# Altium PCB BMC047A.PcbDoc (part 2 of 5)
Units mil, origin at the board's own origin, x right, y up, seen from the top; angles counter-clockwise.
Board outline 4950 x 3450 mil, 6 copper layers (Top Layer, GND Layer 1, Signal Layer 1, Signal Layer 2, GND Layer 2, Bottom Layer), stack 60.7 mil thick; 322 components, 160 nets, 1128 pads, 816 vias.

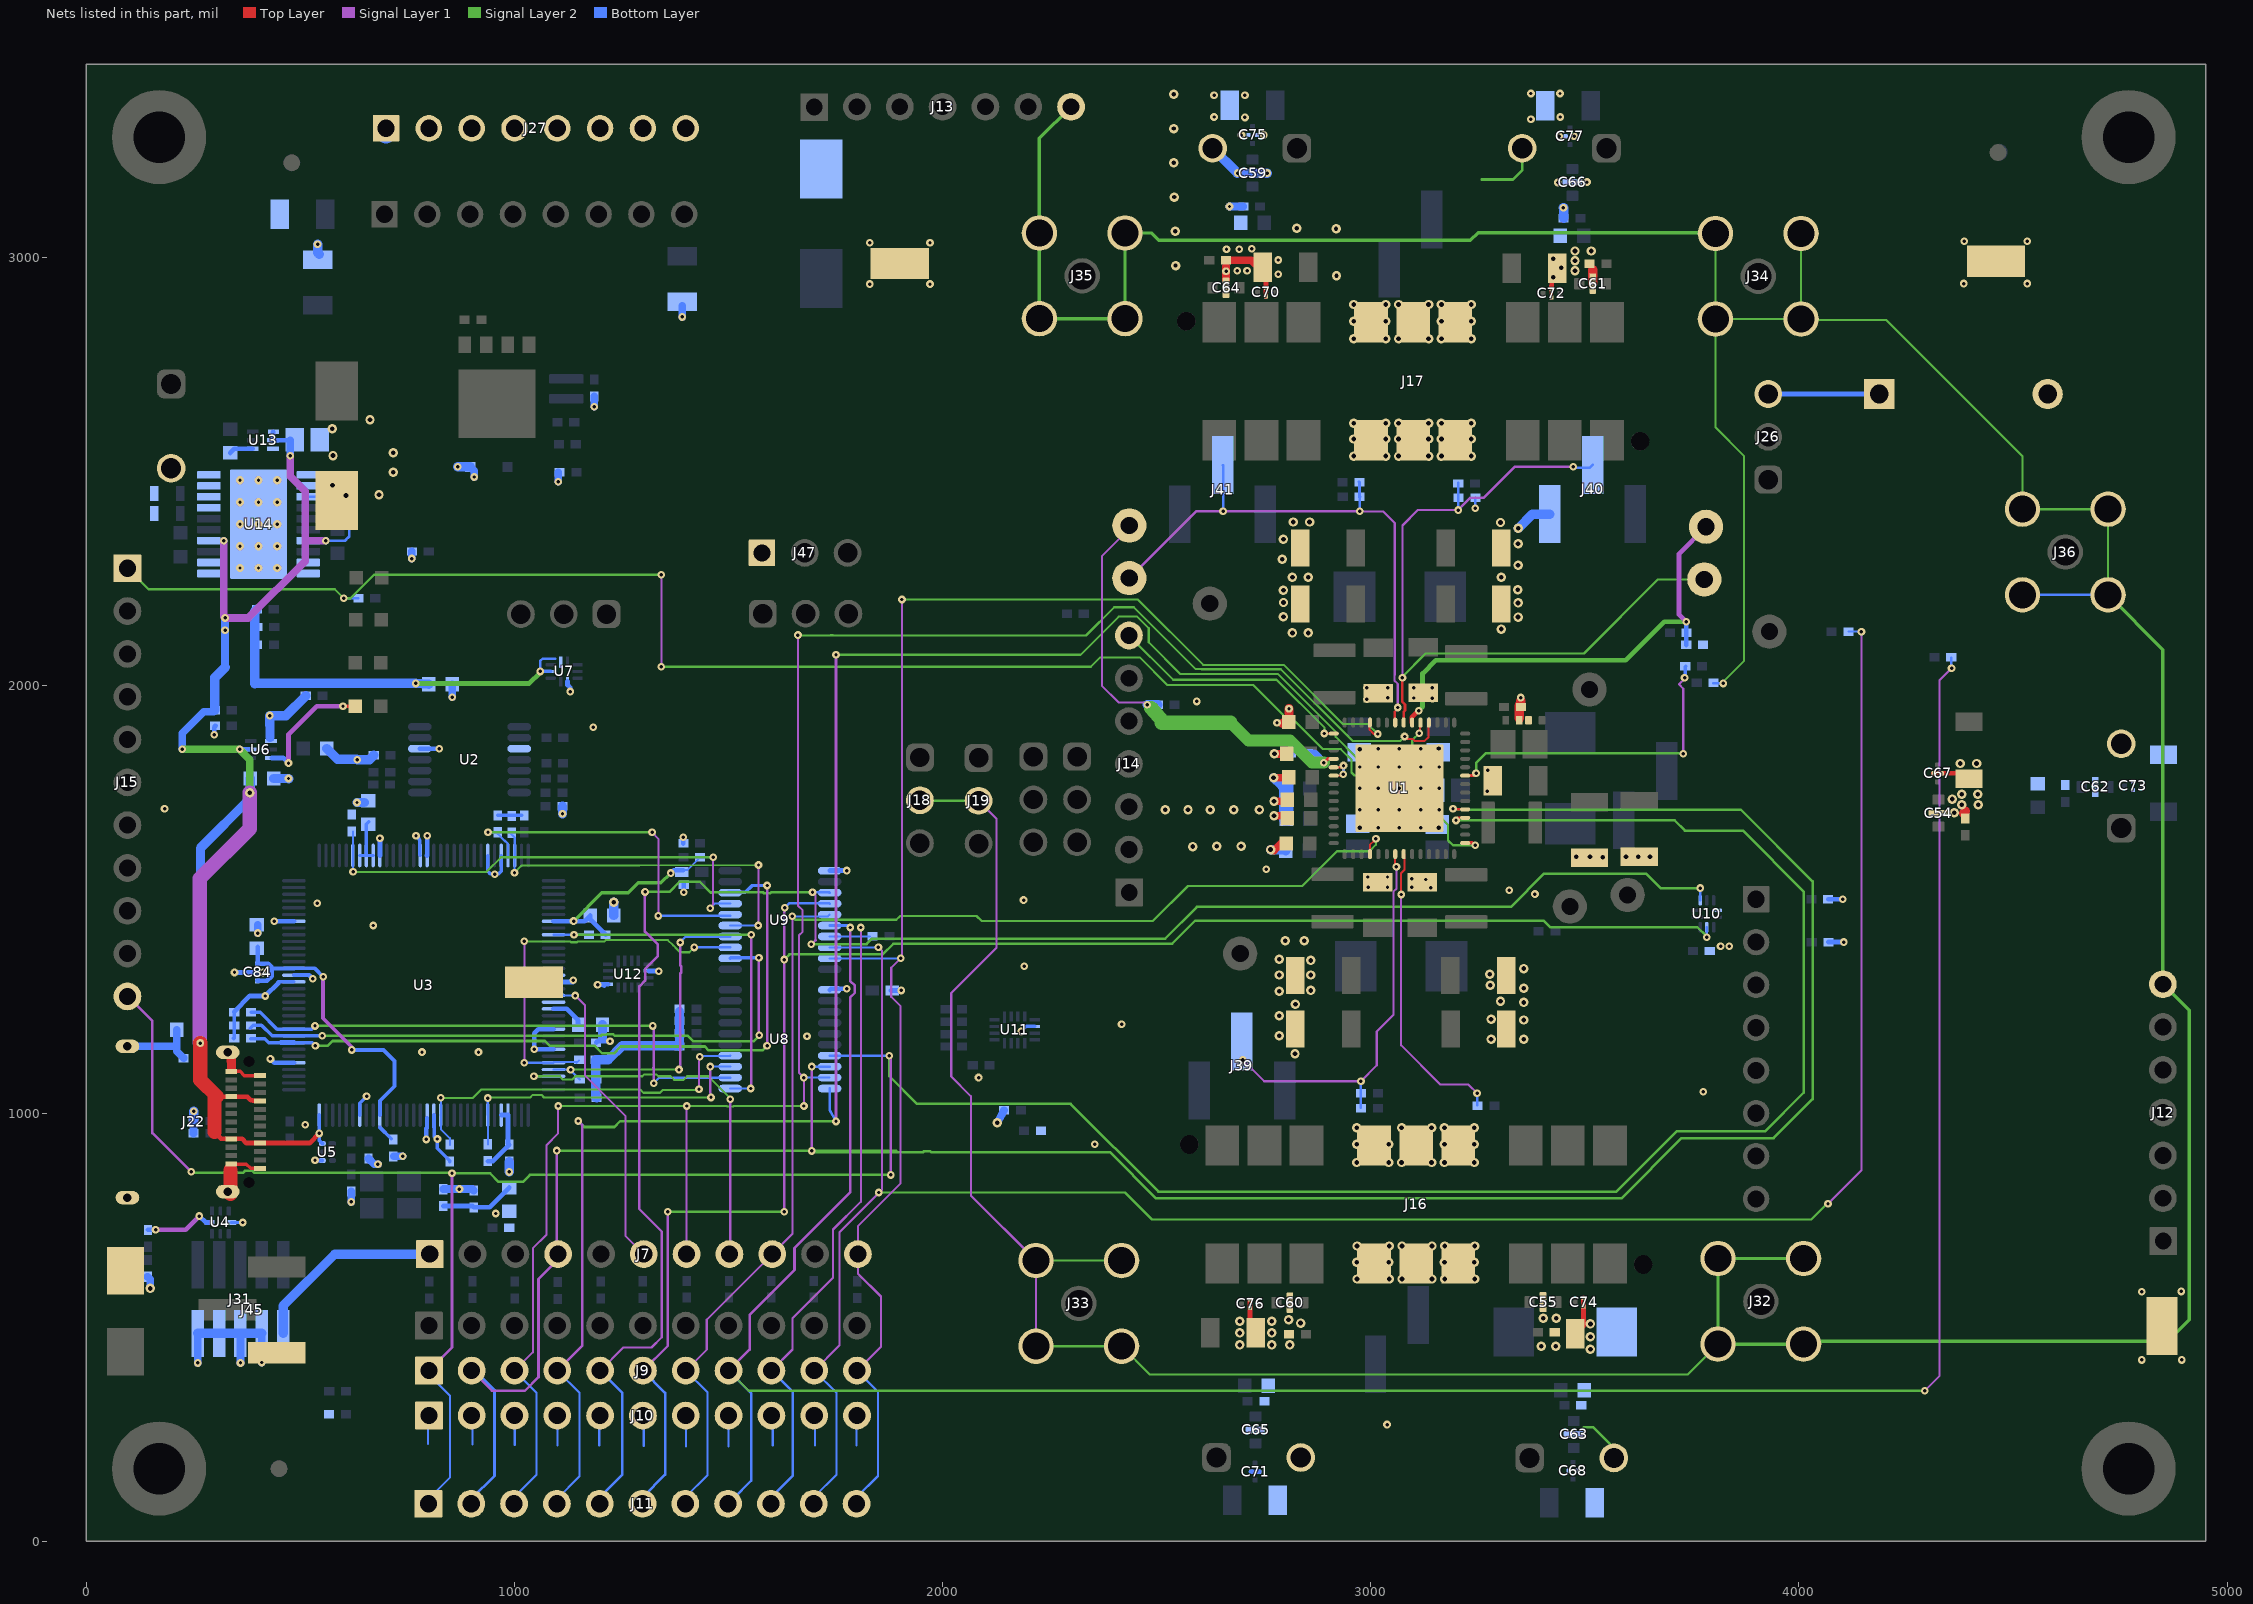
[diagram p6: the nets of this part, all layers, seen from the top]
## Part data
C1 C7 C18 C19 C20 C21 C22 C94: library part CMP-0008770-2, "CAP, CERM, 22 uF, 6.3 V, +/- 10%, X7R, AEC-Q200 Grade 1, 1206", Cap_Case=1206_180, Manufacturer=TDK, Supplier Part Number 1=445-7884-1-ND, TempCo=X7R, Tolerance_%=10%, Value1="0.001872 ohm", Value2=6.3V, ValueDisplayed=22uF
C2: library part CMP-0011150-1, "CAP, AL, 150 uF, 35 V, +/- 20%, 0.17 ohm, SMD", Cap_Case=8x10, Manufacturer=Nichicon, Supplier Part Number 1=493-2291-1-ND, Tolerance_%=20%, Value1="0.17 ohm", Value2=35V, ValueDisplayed=150uF
C3: library part CMP-0012293-3, "CAP, Electric Double Layer, 47000 uF, 5.5 V, +80/-20%, TH", Manufacturer=Elna, Supplier Part Number 1=604-1021-ND, Tolerance_%=80%, Value1=Unknown, Value2=5.5V, ValueDisplayed=47000uF
C4 C5 C6 C8 C10 C11 C12 C13 C15 C81 C85 C86 C88 C91 C96 C97 C109 C111 C115 C116: library part CMP-0007068-4, "CAP, CERM, 2.2 uF, 16 V, +/- 20%, X7S, AEC-Q200 Grade 1, 0603", Cap_Case=0603, Manufacturer=TDK, Supplier Part Number 1=445-16105-1-ND, TempCo=X7S, Tolerance_%=20%, Value1=Unknown, Value2=16V, ValueDisplayed=2.2uF
C9 C14 C108 C110: library part CMP-0064967-2, "CAP, CERM, 0.47 uF, 10 V,+/- 10%, X7S, 0402", Cap_Case=0402, Manufacturer=MuRata, Supplier Part Number 1=490-14427-1-ND, TempCo=X7S, Tolerance_%=10%, Value1=Unknown, Value2=10V, ValueDisplayed=0.47uF
C16 C17: library part CMP-0087302-2, "CAP CER 6PF 50V C0G 0402", Manufacturer=Murata, TempCo=30ppm/°C, ValueDisplayed=6pF
C23 C34 C35 C37 C38 C39 C40 C41 C42 C43 C44 C93 C99 C100 C106: library part CMP-0080702-1, "CAP, CERM, 0.1 µF, 16 V,+/- 5%, X7R, AEC-Q200 Grade 1, 0402", Cap_Case=0402, Manufacturer=MuRata, Supplier Part Number 1=490-16433-1-ND, TempCo=X7R, Tolerance_%=5%, Value2=16V, ValueDisplayed=0.1µF
C24 C25 C26 C27 C28 C29 C30 C31 C32 C33: library part CMP-0009173-2, "CAP, CERM, 47 uF, 6.3 V, +/- 20%, X7R, 1210", Cap_Case=1210, Manufacturer=MuRata, PartNumber=GCM32ER70J476ME19L, Supplier Part Number 1=490-8064-1-ND, TempCo=X7R, Tolerance_%=20%, Value1=Unknown, Value2=6.3V
C36 C47 C58 C69 C78 C114: library part CMP-0007965-2, "CAP, CERM, 10 uF, 16 V, +/- 10%, X7S, AEC-Q200 Grade 1, 0805", Cap_Case=0805, Manufacturer=TDK, Supplier Part Number 1=445-16110-1-ND, TempCo=X7S, Tolerance_%=10%, Value1=Unknown, Value2=16V, ValueDisplayed=10uF
C45 C46 C48 C49 C50 C51 C52 C53 C56 C57: library part CMP-0086484-2, "Chip Multilayer Ceramic Capacitors for Automotive", Manufacturer=Murata, TempCo=+22/-33%, Tolerance_%=20%
C54 C55 C59 C60 C61 C62 C63 C64 C65 C66: library part CMP-0082680-1, "CAP, CERM, 10 µF, 4 V,+/- 20%, 1.6x0.8mm", Cap_Case=0603, Manufacturer=MuRata, PartNumber=NFM18HC106D0G3, TempCo=Unknown, Tolerance_%=20%, Value2=4V, ValueDisplayed=10µF
C67 C68 C70 C71 C72 C73 C74 C75 C76 C77 C84: library part CMP-0086486-3, "3 Terminals Chip Multilayer Ceramic Capacitor (EMIFIL)", Manufacturer=Murata, Tolerance_%=20%, ValueDisplayed=1µF
C79: library part CMP-0750066-1, "CAP, TA, 680 µF, 6.3 V, +/- 10%, 0.023 ohm, AEC-Q200 Grade 1, SMD", Cap_Case=7343, Manufacturer=Kemet, Tolerance_%=10%, Value1="0.023 ohm", Value2=6.3V, ValueDisplayed=680µF
C80 C101 C102 C103 C104 C105: library part CMP-0006922-4, "CAP, CERM, 3300 pF, 50 V, +/- 10%, X7R, 0603", Cap_Case=0603, Manufacturer=Kemet, Supplier Part Number 1=399-1086-1-ND, TempCo=X7R, Tolerance_%=10%, Value1=Unknown, Value2=50V, ValueDisplayed=3300pF
C82 C83 C87 C89 C90 C107: library part CMP-0006351-2, "CAP, CERM, 0.1 uF, 16 V, +/- 10%, X7R, 0402", Cap_Case=0402, Manufacturer=MuRata, Supplier Part Number 1=490-4759-2-ND, TempCo=X7R, Tolerance_%=10%, Value1=Unknown, Value2=16V, ValueDisplayed=0.1uF
C92 C95: library part CMP-0085816-1, "CAP, CERM, 12 pF, 50 V,+/- 5%, C0G/NP0, AEC-Q200 Grade 1, 0402", Cap_Case=0402, Manufacturer=MuRata, TempCo=C0G/NP0, Tolerance_%=5%, Value2=50V, ValueDisplayed=12pF
C98: library part CMP-0006351-2, "CAP, CERM, 0.1 uF, 16 V, +/- 10%, X7R, 0402", Cap_Case=0402, Manufacturer=MuRata, Supplier Part Number 1=490-4759-2-ND, TempCo=X7R, Tolerance_%=10%, Value1=Unknown, Value2=16V
C112 C113: library part CMP-0007306-5, "CAP, CERM, 22 uF, 6.3 V, +/- 20%, X5R, 0603", Cap_Case=0603, Manufacturer=MuRata, Supplier Part Number 1=490-7611-1-ND, TempCo=X5R, Tolerance_%=20%, Value1=Unknown, Value2=6.3V, ValueDisplayed=22uF
C117: library part CMP-0011130-1, "CAP, AL, 470 uF, 16 V, +/- 20%, 0.17 ohm, SMD", Cap_Case=8x10, Manufacturer=Nichicon, Supplier Part Number 1=493-2266-1-ND, Tolerance_%=20%, Value1="0.17 ohm", Value2=16V, ValueDisplayed=470uF
D1: library part CMP-0085753-1, "Diode, Zener, 10 V, 300 mW, SOD-323", Manufacturer="ON Semiconductor", Power_W=300mW, Value1=0.3W
D3 D4 D5 D6: library part CMP-0002849-2, "LED, Blue, SMD", Color=blue, Manufacturer=OSRAM, Value1=W, Value2=2.85V
FID1 FID2 FID3 FID4 FID5 FID6: library part CMP-0077181-1, "Fiducial mark.  There is nothing to buy or mount.", Manufacturer=N/A
J1 J2 J3 J4 J5 J6: library part CMP-0055529-1, "Terminal Block, 5mm, 2x1, R/A, TH", Color=Green, Current_A=16A, Manufacturer="Phoenix Contact", Supplier Part Number 1=277-2518-ND, Voltage_V=400V
J7 J8 J9 J10 J11 J15: library part CMP-0075454-1, "Header, 100mil, 11x1, Gold, TH", Color=Black, Current_A=6.3A, Manufacturer=Samtec, Supplier Part Number 1=SAM1029-11-ND, Voltage_V=550V
J12 J13 J14: library part CMP-0075416-1, "Header, 100mil, 7x1, Gold, TH", Color=Black, Current_A=6.3A, Manufacturer=Samtec, Supplier Part Number 1=SAM1029-07-ND, Voltage_V=550V
J16 J17: library part CMP-0054892-1, "Receptacle, 2.5mm, 3x2, Gold, SMT", Color=Black, Current_A=25A, Manufacturer="TE Connectivity", Supplier Part Number 1=A101959-ND
J18 J19 J20 J21 J26 J30 J37 J47: library part CMP-0054796-2, "Header, 2.54 mm, 3x1, Gold, TH", Color=Black, Manufacturer="Wurth Elektronik", Supplier Part Number 1=732-5316-ND
J22: library part CMP-0075218-1, "Receptacle, 0.5mm, USB TYPE C, R/A, SMT", Color=Black, Current_A=5A, Manufacturer="Amphenol Canada", Supplier Part Number 1=12401610E4#2ACT-ND
J23 J24 J25: library part CMP-0075020-1, "JUMPER TIN SMD", Manufacturer=Harwin, Supplier Part Number 1=952-1740-1-ND
J27 J28 J29: library part CMP-0087040-2, "Board-To-Board Connector, Vertical, ESQ Series, 8 Contacts, Receptacle, 2.54 mm, Through Hole", Current_A=5.7A, Manufacturer=Samtec, Voltage_V=550V
J31: library part CMP-0075670-2, "Header (Shrouded), 1.27mm, 5x2, Gold, SMT", Color=Black, Current_A=3.3A, Manufacturer=Samtec, PartNumber=FTSH-105-01-F-DV-K, Supplier Part Number 1=SAM8796-ND
J32 J33 J34 J35 J36: library part CMP-0075495-1, "SMA Jack, Straight, 50 Ohm, Gold, TH", Manufacturer=Samtec, Supplier Part Number 1=SMA-J-P-H-ST-TH1-ND
J39 J40 J41 J45: library part CMP-0075402-1, "Header, 100mil, 3x1, Gold, SMT", Manufacturer=Samtec, Supplier Part Number 1=TSM-103-01-L-SV-ND
J42 J43 J44: library part CMP-0075491-1, "Header, 100mil, 2x1, Tin, SMD", Color=Black, Current_A=5.4A, Manufacturer=Samtec, Supplier Part Number 1=77P4673, Voltage_V=475V
L1 L2 L3 L4 L5: library part CMP-0085838-1, "Inductor, Thin Film, 470 nH, 5.3 A, 0.021 ohm, AEC-Q200 Grade 0, SMD", Manufacturer=TDK, PartNumber=TFM322512ALMAR47MTAA, Value1="0.021 ohm", Value2=5.3A
LBL1: library part CMP-0003625-1, Manufacturer=Brady, Supplier Part Number 1=97C5133
LOGO1: library part CMP-0074837-1, "IEC 61010-1 Hot Surface Warning"
Logo2: library part CMP-0074838-1, "Texas Instrument Corporate Signature"
Logo3: library part CMP-0074769-1
Logo4: library part CMP-0074844-1
Logo5: library part CMP-0074847-1, "FCC_disclaimer"
NT1 NT2 NT3: library part CMP-0078142-4, "Single point connection between nets.", Manufacturer=N/A
Q1: library part CMP-0100008-1, "MOSFET, N-CH, 30 V, 27.2 A, AEC-Q101, SO-8FL", Alternate Manufacturer=None, Manufacturer="ON Semiconductor", Value1="? ohm", Value2="30 nC"
R1 R2 R3 R4 R5 R6 R7 R19 R26 R35 R36 R39 R40 R58 R65 R67 R83: library part CMP-0027007-2, "RES, 0, 5%, 0.063 W, AEC-Q200 Grade 0, 0402", Manufacturer="KOA Speer", Power_W=63mW, Supplier Part Number 1=660-RK73Z1ETTP, TempCo=ppm/C, Tolerance_%=5%, Value2=0.063W, Value_Code=0000, ValueDisplayed=0
R8 R9 R10 R11 R12 R13 R14 R15 R16 R17 R18 R28 R29 R31 R33 R37 R38 R42 R44 R46 R47 R49 R70 R71 R72 R73 R74 R75 R76 R77 R78 R79 R80 R81 R82 R93 R94 R95: library part CMP-0026825-5, "RES, 10 k, 5%, 0.063 W, AEC-Q200 Grade 0, 0402", Manufacturer=Vishay-Dale, Power_W=63mW, Supplier Part Number 1=541-10KJCT-ND, TempCo="200 ppm/C", Tolerance_%=5%, Value2=0.063W, Value_Code=10k0, ValueDisplayed=10k
R20 R21 R30: library part CMP-0026882-3, "RES, 240, 5%, 0.063 W, AEC-Q200 Grade 0, 0402", Manufacturer=Vishay-Dale, Power_W=63mW, Supplier Part Number 1=541-240JCT-ND, TempCo="200 ppm/C", Tolerance_%=5%, Value2=0.063W, Value_Code=240R, ValueDisplayed=240
R22 R23 R24 R50 R59: library part CMP-0026854-5, "RES, 1.2 k, 5%, 0.063 W, AEC-Q200 Grade 0, 0402", Manufacturer=Vishay-Dale, Power_W=63mW, Supplier Part Number 1=541-1.2KJCT-ND, TempCo="200 ppm/C", Tolerance_%=5%, Value2=0.063W, Value_Code=1k20, ValueDisplayed=1.2k
R25: library part CMP-0015357-3, "RES, 0.002, 2%, 1 W, 0508", Manufacturer="Susumu Co Ltd", PartNumber=KRL2012E-M-R002-G-T5, Power_W=1W, Supplier Part Number 1=408-1592-1-ND, TempCo="100 ppm/C", Tolerance_%=2%, Value_Code=2L000, ValueDisplayed=0.002
R32 R45 R51 R54: library part CMP-0026824-3, "RES, 100, 5%, 0.063 W, AEC-Q200 Grade 0, 0402", Manufacturer=Vishay-Dale, Power_W=63mW, Supplier Part Number 1=541-100JCT-ND, TempCo="200 ppm/C", Tolerance_%=5%, Value2=0.063W, Value_Code=100R, ValueDisplayed=100
R34 R53: library part CMP-0026873-2, "RES, 200 k, 5%, 0.063 W, AEC-Q200 Grade 0, 0402", Manufacturer=Vishay-Dale, Power_W=63mW, Supplier Part Number 1=541-200KJCT-ND, TempCo="200 ppm/C", Tolerance_%=5%, Value2=0.063W, Value_Code=200k
R41 R43 R52: library part CMP-0026413-2, "RES, 4.87 k, 1%, 0.063 W, AEC-Q200 Grade 0, 0402", Manufacturer=Vishay-Dale, Power_W=63mW, Supplier Part Number 1=541-4.87KLCT-ND, TempCo="100 ppm/C", Tolerance_%=1%, Value2=0.063W, Value_Code=4k87, ValueDisplayed=4.87k
R48 R55 R60 R68 R69: library part CMP-0026859-2, "RES, 1.0 M, 5%, 0.063 W, AEC-Q200 Grade 0, 0402", Manufacturer=Vishay-Dale, Power_W=63mW, Supplier Part Number 1=541-1.0MJCT-ND, TempCo="200 ppm/C", Tolerance_%=5%, Value2=0.063W, Value_Code=1M00, ValueDisplayed=1.0M
R61 R62 R63 R64: library part CMP-0026852-3, "RES, 1.0 k, 5%, 0.063 W, AEC-Q200 Grade 0, 0402", Manufacturer=Vishay-Dale, Power_W=63mW, Supplier Part Number 1=541-1.0KJCT-ND, TempCo="200 ppm/C", Tolerance_%=5%, Value2=0.063W, Value_Code=1k00
R66: library part CMP-0026317-2, "RES, 374 k, 1%, 0.063 W, AEC-Q200 Grade 0, 0402", Manufacturer=Vishay-Dale, Power_W=63mW, Supplier Part Number 1=541-374KLCT-ND, TempCo="100 ppm/C", Tolerance_%=1%, Value2=0.063W, Value_Code=374k
S1: library part CMP-0002216-1, "Switch, SPST, Off-On,  50 mA,24V, SMD", CurrentRating_mA=50A, Manufacturer="TE Connectivity", Supplier Part Number 1=23R8896
SH-J1 SH-J2 SH-J3 SH-J4 SH-J5 SH-J6 SH-J7 SH-J8 SH-J9 SH-J10 SH-J11 SH-J12 SH-J13 SH-J14 SH-J15 SH-J16: library part CMP-0003677-2, "Shunt, 100mil, Gold plated, Black", Manufacturer="TE Connectivity", Supplier Part Number 1=A26242-ND
TP1 TP2: library part CMP-0055137-1, "Test Point, Miniature, Red, TH", Color=Red, Manufacturer=Keystone, Supplier Part Number 1=36-5000-ND
TP3 TP4 TP5 TP14: library part CMP-0075188-1, "Test Lead clips and hooks, SMT", Current_A=2A, Manufacturer=Harwin, Supplier Part Number 1=S1751-46-ND
TP6 TP7 TP8 TP9 TP10 TP11 TP12 TP13: library part CMP-0055141-1, "Test Point, Miniature, Yellow, TH", Color=Yellow, Manufacturer=Keystone, Supplier Part Number 1=36-5004-ND
U1: library part CMP-0085385-6, "Power Management IC (PMIC) With 4-Phase 14-A Buck for Processors, RVJ0056A (VQFN-56)", Alternate Manufacturer="Texas Instruments"
U2: library part CMP-0065405-2, "AEC-Q100 Quad Comparator, PW0014A (TSSOP-14)", Alternate Manufacturer="Texas Instruments", Operating Temperature Range="-40 to 125 C", Rating=Automotive
U3: library part CMP-0077954-1, "MSP432E401YTPDT, PDT0128A (TQFP-128)", Alternate Manufacturer="Texas Instruments", Alternate PartNumber=MSP432E401YTPDT
U4: library part CMP-0043125-4, "Low-Capacitance 6-Channel +/-15 kV ESD Protection Array for High-Speed Data Interfaces, RSE0008A (UQFN-8)", Breakdown Voltage(Min)(V)=6, IO Capacitance(Typ)(pF)=1.6, IO Leakage Current(nA)=1, Manufacturer="Texas Instruments"
U5: library part CMP-0043122-3, "4-Channel USB ESD Solution with Power Clamp, DRY0006A (USON-6)", Breakdown Voltage(Min)(V)=6, IO Capacitance(Typ)(pF)=0.8, IO Leakage Current(nA)=10, Manufacturer="Texas Instruments", Operating Temperature Range="-40 to 85 C", Rating=Catalog
U6 U13: library part CMP-0073729-1, "Automotive Catalog, Dual, 200mA, Low-IQ Low-Dropout Regulator for Portable Devices, DSE0006A (WSON-6)", Alternate Manufacturer="Texas Instruments"
U7 U10: library part CMP-0085520-1, "0.5? Dual SPDT Bidirectional Analog Switch, RSW0010A (UQFN-10)", Alternate Manufacturer="Texas Instruments", Operating Temperature Range="-40 to 85 C", Rating=Catalog
U8 U9: library part CMP-0066429-1, "8-BIT BIDIRECTIONAL LOW-VOLTAGE TRANSLATOR, PW0020A (TSSOP-20)", Alternate Manufacturer="Texas Instruments", Alternate PartNumber=SN74GTL2003PW
U11 U12: library part CMP-0067415-1, "10-Ohm Quad SPDT Analog Switch, RSV0016A (UQFN-16)", Alternate Manufacturer="Texas Instruments"
U14: library part CMP-0037269-2, "5 V, Boost Charge Pump, 300 mA, 2.7 to 5.4 V Input with Synchonrization pin, -40 to 85 degC, 20-pin SOP (PWP20), Green (RoHS & no Sb/Br)", Manufacturer="Texas Instruments", Switching Frequency(Max)(kHz)=400
Y1: library part CMP-0860001-1, "Crystal, 32.768 KHz, 9 pF, AEC-Q200 Grade 1, SMD", Frequency_Fixed=32.768kHz, Load Capacitance="9 pF", Manufacturer=NDK
Y2: library part CMP-0004652-3, "Crystal, 25 MHz, 8pF, SMD", Frequency_Fixed=25MHz, Frequency Stability=+/-30ppm, Manufacturer=NDK, Supplier Part Number 1=644-1259-1-ND
ZZ1: library part CMP-0003616-3
ZZ2: library part CMP-0077236-1
ZZ3: library part CMP-0077237-1
ZZ4: library part CMP-0077238-1

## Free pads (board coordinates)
  round 220 hole 120: 1(170,3280) 2(170,170) 3(4770,170) 4(4770,3280)

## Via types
v1: diameter 18, hole 8, Top Layer to Bottom Layer, tented both sides, 476 vias
v2: diameter 22, hole 11, Top Layer to Bottom Layer, tented both sides, 261 vias
v3: diameter 22, hole 10, Top Layer to Bottom Layer, tented both sides, 36 vias
v4: diameter 19.68, hole 8, Top Layer to Bottom Layer, 21 vias
v5: diameter 19.68, hole 7.87, Top Layer to Bottom Layer, 9 vias
v6: diameter 19.68, hole 7.87, Top Layer to Bottom Layer, tented both sides, 6 vias
v7: diameter 20, hole 10, Top Layer to Bottom Layer, tented both sides, 4 vias
v8: diameter 18, hole 8, Top Layer to Bottom Layer, tented top, 2 vias
v9: diameter 66, hole 40, Top Layer to Bottom Layer, tented both sides, 1 vias

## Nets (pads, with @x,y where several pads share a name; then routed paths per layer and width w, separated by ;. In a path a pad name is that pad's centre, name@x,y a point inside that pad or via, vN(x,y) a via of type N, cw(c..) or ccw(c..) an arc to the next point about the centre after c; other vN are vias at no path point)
+VBUS: C80.1 C81.1 C114.1 J22.A4 J22.A9 J22.B4 J22.B9 R39.1 R60.1 U3.96 U5.6 U6.2 U13.1 U13.2 U14.3 U14.7 U14.14 | length 3699.3
  Top Layer w11: 299,956 314.6,940.4 J22.B4@338.52,940.4 363.6,940.4 373.44,930.56 J22.A9@405.45,930.56 521.56,930.56 v1(544,953) ; 299,1038.83 305.17,1038.83 J22.B9@338.52,1038.83 376.17,1038.83 384.5,1030.5 388.08,1030.5 389.08,1029.5 389.49,1029.5 390.01,1028.98 J22.A4@405.45,1028.98
  Top Layer w33: v1(266,1164) 266,1078 305.17,1038.83 ; 299,956 299,1038.83
  Signal Layer 1 w18: v1(321,2337.61) 321,2160 v1(324,2157) 378.39,2157 511,2289.61 511,2338 ; v1(476,2536) 476,2488 511,2453 511,2338 ; v1(559,2337.61) 511.39,2337.61 511,2338
  Signal Layer 1 w22: v1@265,1165 v1(266,1164)
  Signal Layer 1 w33: v1@265,1165 265,1548 381.73,1664.73 v2(381.73,1749)
  Signal Layer 2 w18: v1(224,1850) 357.69,1850 v1(358,1850.33) 358,1849.69 381.73,1825.96 v2(381.73,1749)
  Bottom Layer w6: U14.3@518.3,2439.98 582.02,2439.98 614,2408 614,2347.23 611.29,2344.52 606.61,2339.81 604.39,2337.61 v1(559,2337.61)
  Bottom Layer w9: U3.96@543.91,995.85 543.91,936.44 U5.6@551.29,929.06
  Bottom Layer w11: v1(358,1850.33) U6.2@385.08,1850.33 ; U13.1@436.69,2591.69 435.91,2590.9 U13.2@435.91,2572 C114.1@476,2572 ; U14.7@518.3,2337.61 v1(559,2337.61)
  Bottom Layer w18: v1(224,1850) 224,1888 274,1938 297.32,1938 R39.1@300.32,1941 ; 324,2041.5 v1(324,2128) v1(324,2157) ; v1(476,2536) C114.1@476,2572
  Bottom Layer w22: R60.1@266,1135.68 v1(266,1164) ; C80.1@266.56,1195 266.56,1619.36 381.73,1734.53 v2(381.73,1749) 382.44,1749.71 C81.1@382.44,1782 ; R39.1@300.32,1941 300.32,2017.82 324,2041.5
AMUXOUT: J14.7 U1.1 | length 593.5
  Top Layer w5: v1@2891.68,1884 2894.64,1886.95 U1.1@2913.46,1886.95
  Signal Layer 2 w5: J14.7@2435,2116 2538.31,2012.69 2779.84,2012.69 2892.22,1900.32 2892.22,1884 v1@2891.68,1884 ; v1@2890.26,1882 v1@2892.01,1883.75 ; v1@2892.01,1883.75 2892.76,1883 2893,1883.24 v1@2892.25,1883.99 ; v1@2892.01,1883.75 v1@2892.25,1883.99 ; v1@2892,1883.76 v1@2892.23,1883.99
  Bottom Layer w5: J14.7@2434,2115 J14.7@2435,2116
  other v1: 2891,1887
EN_DRV: J15.1 R35.1 U1.29 | length 3714.9
  Top Layer w8: U1.29@3219.7,1631.5 v1@3237.54,1631.5
  Signal Layer 1 w5: v1(1343,2043) v1(1343,2258)
  Signal Layer 2 w5: J15.1@96,2273 145,2224 580.2,2224 v1(601.2,2203) 617,2203 672,2258 v1(1343,2258) ; v1(1343,2043) 2346,2043 2368,2065 2460.06,2065 2525.06,2000 2726.08,2000 2810.08,1916 2823,1916 2888.5,1850.5 2930.15,1850.5 2955,1825.65 2955,1796 2961.94,1789.06 2986.08,1789.06 2986.14,1789 3021,1789 3043,1767 3043,1749 3054,1738 3115,1738 3135,1718 3135,1705 3151,1689 3165.67,1689 3180.5,1674.17 3180.5,1637.83 3181.5,1636.83 3181.5,1636.17 3191.17,1626.5 3191.83,1626.5 3192.33,1626 v1(3244,1626)
  Bottom Layer w5: v1(601.2,2203) R35.1@635.32,2203
FB_B1: R1.1 U1.22 | length 703
  Top Layer w5: v1(3071,1511) 3071,1561.27 3072,1562.27 3079.05,1569.32 3079.05,1602.86 U1.22@3076,1605.91
  Signal Layer 1 w5: v1(3071,1511) 3071,1158.85 3162.85,1067 3228.32,1067 v1(3248.32,1047)
  Bottom Layer w6: R1.1@3248.32,1019.31 v1(3248.32,1047)
FB_B2: J39.2 R2.1 R3.1 U1.21 | length 931.6
  Top Layer w5: U1.21@3056.31,1605.91 3056.31,1573.24 3059.08,1576 v1(3060,1576)
  Signal Layer 1 w5: v1(2701,1125) 2751,1075 v1(2977,1075) 3014,1112 3014,1191.15 3053.5,1230.65 3053.5,1518.25 3060,1524.75 v1(3060,1576)
  Bottom Layer w6: R3.1@2977,1013 v1(2977,1075)
FB_B3: J40.2 R4.1 R5.1 TP6.1 U1.49 | length 1834.3
  Top Layer w6: v1(3074,2017) 3074,1960.81 3080,1954.81 3080,1940.73 3077,1937.73 3077,1914 U1.49@3076,1913
  Signal Layer 1 w5: v1(3074,2017) 3074,2372.94 3110.06,2409 v1(3204,2409)
  Signal Layer 1 w6: v1(3204,2409) 3233,2438 3264,2438 3336,2510 v1(3473,2510)
  Signal Layer 2 w5: v1(3074,2017) 3074,2020 3128,2074 3498,2074 3671,2247 TP6.1@3779,2247
  Bottom Layer w6: v1(3204,2409) R5.1@3204,2472.68 ; v1@3471.91,2508.09 3511.59,2508.09 J40.2@3518,2514.5
FB_B4: J41.2 R6.1 R7.1 TP7.1 U1.50 | length 1448.5
  Top Layer w5: U1.50@3056.16,1912.54 3056,1912.7 3056,1938 3063,1945 v1(3063,1947.77)
  Signal Layer 1 w5: v1(2974,2406) 3028.63,2406 3055.89,2378.74 3055.89,2024.2 3055.5,2023.81 3055.5,2010.58 3063,2003.08 v1(3063,1947.77)
  Signal Layer 1 w6: TP7.1@2436,2250 2592,2406 2881,2406 ; v1(2655,2406.5) 2757.5,2406.5 ; 2880.91,2406.09 2881,2406 ; v1(2974,2406) 2881,2406
  Bottom Layer w6: J41.2@2654,2514 2655,2513 v1(2655,2406.5) ; R7.1@2972.53,2475.16 R7.1@2973.68,2474 ; R6.1@2973.94,2440 2974,2439.94 v1(2974,2406)
  Bottom Layer w7.87: R7.1@2973.68,2474 2973.68,2440.25 R6.1@2973.94,2440
FB_B5: R67.1 U1.37 | length 761.5
  Top Layer w6: U1.37@3219.7,1788.98 3240.85,1788.98 v1(3245.87,1794)
  Signal Layer 1 w5: v1(3730,1840) 3730,1992 3720,2002 3733,2015 v1(3733,2017)
  Signal Layer 2 w6: v1(3245.87,1794) 3245.87,1818.33 3268.73,1841.2 3728.8,1841.2 v1(3730,1840)
  Bottom Layer w5: v1(3733,2017) v1@3734.07,2017
  Bottom Layer w8: v1@3734.07,2017 3734.07,2042.51 R67.1@3735.31,2043.76
GND: C1.2 C2.2 C3.2 C4.2 C5.2 C6.2 C7.2 C8.2 C9.1 C10.2 C11.2 C12.2 C13.2 C14.1 C15.2 C16.1 C17.1 C18.2 C19.2 C20.2 C21.2 C22.2 C23.2 C24.1 C25.1 C26.1 C27.1 C28.1 C29.1 C30.1 C31.1 C32.1 C33.1 C34.2 C35.2 C36.1 C37.2 C38.2 C39.2 C40.2 C41.2 C42.2 C43.2 C44.2 C45.2 C46.2 C47.2 C48.2 C49.2 C50.2 C51.2 C52.2 C53.2 C54.2 C55.2 C56.2 C57.2 C58.2 C59.2 C60.2 C61.2 C62.2 C63.2 C64.2 C65.2 C66.2 C67.2 C68.2 C69.2 C70.2 C71.2 C72.2 C73.2 C74.2 C75.2 C76.2 C77.2 C78.2 C79.2 C80.2 C81.2 C82.2 C83.2 C84.2 C85.2 C86.2 C87.1 C88.2 C89.2 C90.2 C91.2 C92.2 C93.2 C94.2 C95.2 C96.1 C97.1 C98.2 C99.2 C100.2 C101.2 C102.2 C103.2 C104.2 C105.2 C106.1 C107.1 C108.1 C109.2 C110.1 C111.1 C112.2 C113.2 C114.2 C117.2 D1.2 J1.2 J2.2 J3.2 J4.2 J5.2 J6.2 J10.1 J10.2 J10.3 J10.4 J10.5 J10.6 J10.7 J10.8 J10.9 J10.10 J10.11 J16.3 J16.4 J17.3 J17.4 J22.A1 J22.A12 J22.B1 J22.B12 J22.S1 J22.S2 J22.S3 J22.S4 J27.1 J27.2 J27.3 J27.4 J27.5 J27.6 J27.7 J27.8 J31.3 J31.5 J31.7 J31.9 J40.1 J45.3 J47.1 NT1.2 NT2.2 NT3.1 R4.2 R31.1 R34.1 R38.1 R41.2 R43.2 R46.1 R52.2 R59.2 R60.2 R66.1 R68.1 R69.1 R95.2 S1.1 TP3.1 TP4.1 TP5.1 TP14.1 U1.5 U1.6 U1.57 U2.12 U3.10 U3.17 U3.48 U3.55 U3.58 U3.80 U3.114 U4.4 U5.4 U6.4 U7.6 U8.1 U9.1 U10.6 U11.6 U12.6 U12.13 U13.3 U13.4 U14.1 U14.2 U14.9 U14.10 U14.11 U14.12 U14.17 U14.18 U14.19 U14.20 U14.21@402.16,2376 | length 5189.3
  Top Layer w5: C53.2@2743.91,2967 C53.2@2755.12,2955.8 ; U1.6@2912.63,1789 v1@2934,1789 ; U1.5@2913.46,1808.21 2932.42,1808.21 v1(2936.35,1812.15)
  Top Layer w8: J22.S2@330.25,817.17 337,823.92 J22.S2@338.52,825.44 ; J22.B1@338.52,881.35 373.65,881.35 383.5,871.5 J22.A12@405.45,871.5 ; J22.B12@338.52,1097.88 359.12,1097.88 368.96,1088.04 J22.A1@405.45,1088.04 ; C72.2@3422,2905.16 C72.2@3422,2924.84
  Top Layer w11: C76.2@2718,564.84 C76.2@2718,545.16 2718,500.15 C51.2@2731.15,487 ; C70.2@2755,2908 2755.12,2922.69 C53.2@2755.12,2955.8 ; C72.2@3422,2924.84 3422,2932.12 3422.47,2932.58 C52.2@3422.47,2959.32 ; C50.2@3478,485 3497,504 C74.2@3497,549.16 C74.2@3497,568.84 ; C67.2@4314.16,1794 C67.2@4333.84,1794 4384.11,1794 C49.2@4397,1781.11
  Top Layer w18: C64.2@2662,2947.69 v1(2662,2967) 2662,2977.94 ; C37.2@2662,2992.78 2721.07,2992.78 C53.2@2743.85,2970 ; v2(2766,1616) 2770.51,1616 2772.51,1614 2772.98,1614 2773.75,1613.24 C8.2@2795.44,1634.93 ; v2(2773,1784) 2806.96,1784 C12.2@2807.96,1783 ; v2(2774,1729) 2803.51,1729 C11.2@2804.44,1729.93 ; v2@2779,1695 2797.48,1695 2802.48,1690 C10.2@2804.48,1692 ; v2@2783,1839 C13.2@2807.44,1839 ; C8.2@2796.44,1633 2799.44,1630 C8.2@2804.44,1635
  Top Layer w22: J22.S1@330.25,1142.37 338.52,1134.1 J22.B12@339,1103 ; C15.2@2794.53,1911.29 2808.17,1910.31 2812.44,1910 2809,1913.44 v1(2809,1945) ; C16.1@3346.69,1922.94 3346.69,1950 3346.74,1950.18 3350.69,1963.31 v1@3350,1964 ; C61.2@3518.35,2937.65 3518.35,2970.65 ; 4384.51,1701 4389,1705.49
  Top Layer w33: J22.S2@337,811.09 337,823.92 337,867
  Signal Layer 1 w5: v4@3016.32,1851.98 v4@3016.32,1856.39 ; v4@3158,1759 v4@3158.57,1759.57
  Signal Layer 2 w5: v4(3067,1759) 3076,1768 3076,1780
  Signal Layer 2 w6: 3259,3181 3332,3181 3353.57,3202.57 J3.2@3353.57,3254 ; 3498,267 3519,267 3567.85,218.15 J1.2@3567.85,195
  Bottom Layer w5: 427.68,1879.62 429,1878.31 U6.4@435.62,1871.68 ; 798,227.68 798,292 J10.1@800,294 ; J10.2@900,294 902.09,291.91 902.09,226 ; J10.3@1000,294 1000.6,293.4 1000.6,225.68 ; J10.4@1100,294 1100.63,293.37 1100.63,224.68 ; 1198,223.68 1198,292 J10.5@1200,294 ; J10.6@1300,294 1302,292 1302,222.68 ; J10.7@1400,294 1401,293 1401,221.68 ; 1500,221.68 J10.8@1500,294 ; J10.9@1600,294 1603.19,290.81 1603.19,223.68 ; J10.10@1700,294 1701.65,292.35 1701.65,223.68 ; 1799,224.68 1799,293 J10.11@1800,294
  Bottom Layer w6: v1@3244,2415 3244,2418.08 3244.37,2418.45 R4.2@3244.37,2438
  Bottom Layer w7.87: C6.2@2792,1765 C6.2@2802.44,1765
  Bottom Layer w8: R41.2@250.31,982 R41.2@251,982.69 ; U4.4@338.59,745 v1(365,745) ; v1(2183.54,1191.24) 2195.17,1202.87 U11.6@2215.24,1202.87 ; v1(2936,1792) 2936.35,1792.35 v1(2936.35,1812.15)
  Bottom Layer w9: U3.114@484.85,1322.62 520.38,1322.62 ; v1(534,890) U5.4@550.98,890 ; 795.56,965.83 U3.80@795.56,989.37
  Bottom Layer w11: v1(298.49,1884) 298.49,1900.99 302.5,1905 R31.1@300.32,1905 ; C111.1@336,2542.44 345.87,2552.32 U13.4@388.66,2552.32 ; v1(346,1329) C84.2@389.66,1329 C84.2@409.35,1329 ; 520.38,1322.62 v1(529,1314) ; U3.10@685.64,1602.15 v1(685.64,1642.64) v1@686,1643 ; U2.12@778.86,1851.59 v1(824.49,1851.59) ; v1(794,939) 794,964.27 ; U3.17@795.87,1602.15 796,1602.28 v1(796,1648) ; U3.58@1091.15,1149.39 v1(1046,1149.39) 1046,1186.92 1055.72,1196.64 U3.55@1091.15,1196.64 ; U3.48@1091.15,1306.87 1136.87,1306.87 1137,1307 v1(1137,1311) ; U7.6@1123.94,2008.38 1123.94,2000.5 1130,1994.43 v1(1130,1985) ; R52.2@1190.69,1165.14 1190.83,1165 1193.83,1168 1212,1168 ; 1205.56,1174.44 1212,1168 ; U12.13@1209.78,1297.6 1206.38,1301 1194,1301 U12.13@1218.51,1301.25 ; v1(1223,1168) 1212,1168 ; U12.6@1313,1332.75 1313.25,1333 1313.82,1332.44 1329.57,1332.44 1330.01,1332 v1(1337,1332) ; v1(1394,1645) R66.1@1394.32,1630.32 ; v1@1395.31,1519.69 C98.2@1395.31,1534 C98.2@1395.31,1536 ; U8.1@1736.14,1288.2 1736.34,1288 1739.34,1291 v1(1776,1291) ; U9.1@1736.14,1566.51 1736.63,1567 v1(1776,1567) ; R34.1@1878.68,1287 v1(1903,1287) ; C71.2@2720.16,163 C71.2@2739.84,163 ; R68.1@4068.37,1500.19 v1(4102.69,1500.19) ; R69.1@4069.22,1400 v1(4104.53,1400)
  Bottom Layer w18: J22.S3@96,1156.54 209.98,1156.54 211.44,1158 ; C82.2@143,618.31 149,612.31 v2(149,591) ; C80.2@211.44,1195 211.44,1158 ; R60.2@227.31,1129 211.44,1144.87 211.44,1158 ; R43.2@250.31,953 R41.2@250.31,982 ; v1(260,417) J31.9@260,486 ; v1(360,417) J31.5@360,486 ; v1(400,1421) C86.2@400,1440 ; v1(410,418) J31.3@410,486 ; v1(619,793) C95.2@619,817.31 ; C92.2@659,894.31 672.31,881 v1(681,881) ; C90.2@718,900 v1(739,900) ; v1(760.31,2295.69) C100.2@760.31,2312.2 ; C83.2@834,822.69 834.31,823 v1(871.32,823) 901.68,823 C89.2@905,819.69 ; v1(854.93,1972) C88.2@854.93,2002 ; D1.2@896.69,2509.69 906.15,2500.22 v1(906.15,2486.15) ; v1(1102,2475) 1102,2496.69 C93.2@1102.31,2497 ; v1(1186,2650) C99.2@1186,2674.31 ; v1(1392,2860) C94.2@1392,2885.4 ; v2(2127.68,977.68) C107.1@2143.32,1006.86 ; v1(2670,3118) C42.2@2702.31,3118 ; v1@2688.57,3196 v1(2689,3196) C59.2@2724,3196 ; v2(2775,1840) 2812.84,1840 C14.1@2813.31,1840.47
  Bottom Layer w22: R41.2@251,982.69 v1(251,1005) ; J31.9@260,486 J31.7@310,486 J31.5@360,486 J31.3@410,486 ; 429,1878 429,1878.31 v1(428.6,1929) 466.31,1929 R59.2@512.31,1975 ; C81.2@437.56,1782 v1(472.2,1782) v1@472.56,1781.65 ; v1(540,3030) 540,3010.2 C1.2@543.91,3006.3 ; C109.2@561.56,1852 586.56,1827 631.46,1827 v1(632.46,1826) 661.31,1826 R95.2@671.31,1836 ; v1(632.16,1726) C97.1@649.44,1726 ; v1(867.73,2510) 896.38,2510 D1.2@896.69,2509.69 ; v1(988,863) C87.1@988,887.32 ; v1(1112.1,1699.65) R38.1@1112.1,1717 ; 1205.56,1174.44 C85.2@1205.56,1207 ; C96.1@1232.12,1462 v2(1232.12,1492.88) ; J4.2@2630.57,3254 v1@2688.57,3196 ; C59.2@2724,3196 v1(2758,3196) ; v2(2766,1616) 2798.44,1616 C4.2@2801.44,1613 ; v2(2773,1784) C6.2@2792,1765 ; v2(3344.25,2366.2) 3377.55,2399.5 J40.1@3418,2399.5 ; v1(3450,3115) 3450.31,3114.69 C41.2@3450.31,3091
  Bottom Layer w33: C5.2@2802.44,1688 C6.2@2802.44,1758.78 C6.2@2802.44,1765
  Bottom Layer w44: J27.1@700,3287.15 J27.1@700,3300.54
  other v1: 3038,273 4801,424 4894,424 4801,583 4893,584 956,766 2355,928 510.99,973 3776.55,1050 2084,1083.47 784,1143 916,1143 1683.25,1180 2418,1208.29 1194,1300 412,1329 2190.77,1343.77 3817,1390 3837,1390 670,1438.56 539,1490.68 2189,1498 3383.4,1512 1395,1516 3323.3,1521.09 3140,1527 2994,1528 3039,1528 3096,1528 3128,1546 3096,1548 2993,1552 3039,1552 2756,1570 182.77,1711 3272,1752 3273,1801 1183.62,1902 2781,1912 2593.23,1962.02 2991,1967 3144,1969 3100.5,1970 3040,1971 3350,1971 2991,1994 3040,1994 3100,1994 3144,1994 3244,2413 1829.54,2936.81 1970.46,2936.81 4385,2938 4533,2938 2784,2960.05 2688,2968 2711,2968 2784,2993 2663,3018 2693,3018 2722,3019 1829.54,3033.19 1970.46,3033.19 4386,3037 4533,3037 3437,3174 3505,3175 3440,3282 3474.84,3282 2697.84,3285 2750.16,3285 3374,3322 2706,3326 2634,3327 3442.44,3327 2634,3378 2706,3378 3374,3382 3442,3382
  other v2: 3513,449 3398,456 3432,456 2694,459 2769,459 2811,459 3513,478 2694,487 2769,487 3513,508 2836,510 2694,514 2769,514 2808,518 3403,521 3433,521 2968,613 3043,613 3073,613 3143,613 3173,613 3243,613 2967,652.41 3042,652.41 3172,652.41 3242,652.41 2968,690 3043,690 3073,690 3143,690 3173,690 3243,690 2967,885 3042,885 3072,885 3142,885 3172,885 3242,885 2967,928 3042,928 3172,928 3242,928 2967,966 3072,966 3142,966 3172,966 3242,966 2823,1139 3281,1173 3357,1173 2786,1181 3357,1218 3281,1220 2786,1228 2824,1255 3357,1259 3303,1262 2786,1285 2860,1287 3357,1292 3279,1299 2786,1323 2860,1323 3278,1325 3357,1338 2860,1357 2786,1360 2800,1403 2844.86,1403 3542,1598 3480,1599 3512,1599 3596,1599 3625,1599 3652,1599 2584,1623 2640,1624 2697,1624 2774,1695 4363,1702 2520,1709 2573.12,1709 2624.85,1709 2680,1709.16 2740,1709 4380,1721 4419,1721 4358,1734 4380,1745 4418,1745 4377,1817 4415,1817 2817,2122 2854,2122 3305,2131 3344,2159 2796,2160 3344,2192 2796.14,2193 2796,2222 3343,2223 2817,2252 2854,2252 3304.96,2252 3344,2280 2793,2294 3344,2330 2796,2341 3303,2380 2819,2381 2857,2381 606.46,2443 683.46,2445 574.91,2466.59 717.13,2497 2960,2535 3035,2535 3065,2535 3135,2535 3165,2535 3235,2535 576,2536.17 716.83,2543 2960,2575 3035,2575 3065,2575 3135,2575 3165,2575 3235,2575 574,2599 2960,2612 3035,2612 3065,2612 3135,2612 3165,2612 3235,2612 662.5,2620 2960,2809 3035,2809 3065,2809 3135,2809 3165,2809 3235,2809 2960,2850 3035,2850 3165,2850 3235,2850 2960,2889 3035,2889 3065,2889 3135,2889 3165,2889 3235,2889 3477,2968 3445,2975 3477,2991 3426,2996 3477,3014 3515,3014
  other v3: 3426,2953 2920,2956 2544.05,2980 2543,3060 2919,3066 2827.43,3067 2541.16,3140 2540,3220 2540,3300 2540,3380
  other v4: 3017.16,1666.48 3067,1666.48 3116.84,1666.48 2974.48,1709.16 3017.16,1709.16 3067,1709.16 3116.84,1709.16 3159.52,1709.16 2974.48,1759 3017.16,1759 3116.84,1759 3159.52,1759 2974.48,1808.84 3017.16,1808.84 3067,1808.84 3116.84,1808.84 3159.52,1808.84 3017.16,1851.52 3067,1851.52 3116.84,1851.52
  other v5: 358.85,2324.82 402.16,2324.82 445.46,2324.82 358.85,2376 402.16,2376 445.46,2376 358.85,2427.18 402.16,2427.18 445.46,2427.18
  other v6: 358.85,2273.64 402.16,2273.64 445.46,2273.64 358.85,2478.36 402.16,2478.36 445.46,2478.36
  other v7: 2974,1667 3159,1667 2974,1850 3159,1852
GNDS: J12.7 J13.7 J18.2 J19.2 J32.2 J32.3 J32.4 J32.5 J33.2 J33.3 J33.4 J33.5 J34.2 J34.3 J34.4 J34.5 J35.2 J35.3 J35.4 J35.5 J36.2 J36.3 J36.4 J36.5 R19.1 | length 11941.4
  Signal Layer 1 w5: J19.2@2083,1731 J19.2@2084,1730 2126,1688 2126,1387 2020,1281 2020,1086 2066,1040 2066,808 J33.2@2218,656 J33.5@2218,456
  Signal Layer 2 w5: J18.2@1947,1731 1947,1730 J19.2@2084,1730 ; J33.5@2218,456 J33.4@2418,456 2484,390 3740.12,390 J32.5@3811,460.88 ; J33.2@2218,656 J33.3@2418,656 ; J34.2@3805,3055 J34.5@3805,2855 ; v1(3823,2004) 3823,2008.07 3872,2057.07 3872,2535 3805,2602 J34.5@3805,2855 ; J34.4@3989,2839 4003,2853 4204,2853 4522.18,2534.82 J36.2@4522.18,2411 J36.3@4722.18,2411 J36.4@4722.18,2211 ; J34.3@4005,3055 J34.4@4005,2855 J34.5@3805,2855
  Signal Layer 2 w7.87: J13.7@2300,3351 2226,3277 J35.2@2226,3056 J35.5@2226,2856 J35.4@2426,2856 J35.3@2426,3056 2488,3056 2505,3039 3232.87,3039 3250.87,3057 3803,3057 J34.2@3805,3055 ; J32.3@4011,660.88 J32.2@3811,660.88 J32.5@3811,460.88 J32.4@4011,460.88 4018.12,468 4862,468 4912,518 4912,1241 4851.5,1301.5 J12.7@4850,1301.5 4850,2083.18 J36.4@4722.18,2211
  Bottom Layer w5: R19.1@3798.97,2004.4 3819.33,2004.4 3819.73,2004 v1(3823,2004) ; J36.5@4522.18,2211 J36.4@4722.18,2211
GPIO1: J9.1 J11.1 J15.11 U1.32 U8.7 | length 7167
  Top Layer w6: v1(3199,1684) v1@3200.12,1684 ; v1@3203,1681.12 v1@3200.12,1684 ; U1.32@3219.7,1690.56 3203.56,1690.56 3201,1688 3202,1687 3199.56,1684.56 v1@3200.12,1684
  Signal Layer 1 w6: J15.11@96,1300 96,1274 154,1216 154,954 v1@244.26,863.74 ; J9.1@800,399 854,453 854,814.86 853.32,815.54 853.32,830.45 854,831.13 v1(854,860) ; v1@1876,1134 1879,1131 v1(1879,856)
  Signal Layer 2 w6: v1@244.26,863.74 v1(245,863.74) 247.74,861 365.7,861 370.44,865.74 388.49,865.74 393.23,861 849,861 850,860 v1(854,860) 943,860 963,840 1020.04,840 1036.04,856 v1(1879,856) ; v1(1875.35,1134.65) 1875.35,1086.65 1940,1022 2299,1022 2503.83,817.17 3573.77,817.17 3714.6,958 3921,958 4011,1048 4011,1517.9 3868.9,1660 3734,1660 3710,1684 v1(3199,1684)
  Bottom Layer w5: J11.1@800,100 849,149 849,341 800,390 J9.1@800,399
  Bottom Layer w6: U8.7@1736.14,1134.65 v1(1875.35,1134.65)
GPIO2: J7.4 J9.2 J11.2 U1.33 U8.8 | length 6037.7
  Top Layer w6: v1(3192,1711) 3192,1710 3193,1709 3194.24,1710.24 U1.33@3219.7,1710.24
  Signal Layer 1 w6: J9.2@900,399 947,352 1024.31,352 1056,383.69 1056,613 1102,659 J7.4@1102,671 1099,674 v1(1099,913) ; 1694.06,921.06 v1(1694.06,1109.06)
  Signal Layer 2 w6: v1(1099,913) 1891,913 ; v1(1694.06,912.06) 1696.63,909.5 1955.04,909.5 1956.54,911 1971.46,911 1972.96,909.5 2390.86,909.5 2498.86,801.5 3585.44,801.5 3725.94,942 3940.84,942 4032,1033.16 4032,1541.53 3864.53,1709 3193,1709 3192,1710 v1(3192,1711)
  Bottom Layer w6: J11.2@900,100 953.35,153.35 953.35,353.35 907.71,399 J9.2@900,399 ; v1(1694.06,1109.06) U8.8@1736.14,1109.06
GPIO3: J7.7 J9.3 J11.3 U1.46 U8.9 | length 4771.1
  Top Layer w5: v1(3079,1880) 3084.46,1874.54 3097.46,1874.54 3102.18,1869.82 3125.82,1869.82 3135.06,1879.06 U1.46@3135.06,1913
  Signal Layer 1 w5: J9.3@1000,399 1043,442 1043,685 1075,717 1075,926 1102,953 v1(1102,1017) ; J7.7@1402,671 v1(1402,1017) ; v1(1662,2117) 1662,1485 1673,1474 1673,1424 1664.5,1415.5 1664.5,1094.44 v1(1675.47,1083.47) ; v1(1676,1017) v1@1676,1082.94
  Signal Layer 2 w5: v1(1102,1017) v1(1402,1017) 1495.25,1017 1496.75,1015.5 1511.25,1015.5 1512.75,1017 v1(1676,1017) ; v1@1668,2116 1743.25,2116 1743.75,2116.5 ; v1(1675.47,1083.47) v1@1676,1082.94 ; 1738.5,2116.5 1743.75,2116.5 ; v1@3079,1877 v1(3079,1880) 3068.5,1869.5 2957.62,1869.5 2789.83,2037.29 2604.27,2037.29 2604.07,2037.5 2590.96,2037.5 2446.46,2182 2401,2182 2335,2116 1744.25,2116 1743.75,2116.5
  Bottom Layer w5: J11.3@1000,104 1051,155 1051,348 J9.3@1000,399 ; v1(1675.47,1083.47) U8.9@1736.14,1083.47
GPIO4: J9.4 J11.4 U1.47 U8.10 | length 4365.6
  Top Layer w5: v1@3114,1885 3114,1887.93 3115.37,1889.3 U1.47@3115.37,1913
  Signal Layer 1 w6: J9.4@1100,399 1158,457 1158,973 v1(1149,982) ; v1(1751,981) v1(1751,2071)
  Signal Layer 2 w5: v1(1751,2071) 2322.3,2071 2411.29,2159.99 2454.19,2159.99 2481.39,2132.79 2481.39,2099.91 2555.46,2025.84 2783.54,2025.84 2918,1891.38 2918,1879.35 2967.35,1830 3075.48,1830 3097,1851.52 3097,1872 v1(3113,1888)
  Signal Layer 2 w6: v1(1149,982) 1163,968 1233.16,968 1247,981.84 v1(1751,981)
  Bottom Layer w5: J9.4@1100,399 1152,347 1152,152 1100,100 J11.4@1102,100
  Bottom Layer w6: U8.10@1736.14,1057.88 1736.14,1006.86 v1(1751,981)
GPIO5: J9.5 J11.5 U9.3 U10.3 | length 4376.3
  Signal Layer 1 w5: J9.5@1200,399 1254,453 1320,453 1344,477 1344,724 1291.5,776.5 1291.5,1296.5 ; v1(1696,1516) 1703,1509 1703,1404.14
  Signal Layer 1 w6: 1291.5,1296.5 1305,1310 1305,1337.04 1334.98,1367.02 1334.98,1394.02 1304.5,1424.5 1304.5,1508.01 1305,1508.51 v1(1305,1517) ; v1@1695.86,1397 1703,1404.14
  Signal Layer 2 w6: v1(1305,1517) 1362,1517 1386,1541 1432.69,1541 1458.69,1515 1459.69,1516 1580.54,1516 1582.54,1514 1597.46,1514 1599.46,1516 v1(1696,1516) ; v1(1693,1395) v1@1695,1395 ; v1@1693,1397 v1@1695,1395 ; v1(3769.25,1526) 3677,1526 3643,1560 3405,1560 3327,1482 2594,1482 2520,1408 1835.5,1408 1822.5,1395 v1@1695,1395
  Bottom Layer w6: J11.5@1200,104 1252,156 1252,347 J9.5@1200,399 ; v1(1696,1516) 1734.81,1516 1735.81,1515 U9.3@1736.14,1515.33 ; U10.3@3769.25,1497.5 v1(3769.25,1526)
GPIO6: J9.6 J11.6 U9.4 U10.9 | length 4052.7
  Signal Layer 1 w6: J9.6@1300,399 1358,457 v1(1358,770) ; v1(1630,770) v1(1630,1359) 1630,1473 v1@1631,1474
  Signal Layer 2 w6: v1(1358,770) v1(1630,770) ; v1(1630,1359) 1642,1371 1860,1371 1885,1396 2536,1396 2590,1450 3403.85,1450 3418.85,1435 3762.54,1435 3785,1412.54 v1(3785,1411)
  Bottom Layer w6: J11.6@1300,104 1352,156 1352,347 J9.6@1300,399 ; v1(1631,1480) 1631.7,1480 1642.39,1490.68 1735.2,1490.68 U9.4@1736.14,1489.74 ; v1(3785,1411) U10.9@3785,1434.5
GPIO7: J7.9 J9.7 J11.7 U1.18 U9.5 | length 3103.4
  Top Layer w5: U1.18@2998.1,1605.46 2998,1605.56 2998,1606.65 2998,1627 3007.74,1636.74 v1(3012,1641)
  Top Layer w8: U1.18@2997.26,1605.91 U1.18@2998,1606.65 ; v1@3007.74,1636.74 v1@3007.74,1643.74
  Signal Layer 1 w5: J9.7@1400,399 1449,448 1449,518 J7.9@1602,671 1649,718 1649,724 v1(1649,1460)
  Signal Layer 2 w5: v1(1649,1460) 1649,1458.35 1655.35,1452 1892,1452 1901,1461 2079,1461 2091,1449 2491.12,1449 2573.12,1531 2840,1531 2921,1612 2997,1612 3012,1627 v1(3012,1641)
  Bottom Layer w5: J11.7@1400,104 1451,155 1451,348 J9.7@1400,399 ; v1(1649,1460) 1731.99,1460 U9.5@1736.14,1464.15
GPIO8: J9.8 J11.8 R51.1 U9.6 | length 6115.8
  Signal Layer 1 w5: v1(4294,352) 4328,386 4328,2010.84 v1(4356.58,2039.42)
  Signal Layer 1 w6: J9.8@1500,399 1549,448 1549,529 1654,634 1654,685.39 1784,815.39 1784,1270.54 1795,1281.54 1795,1298 1784,1309 v1(1784,1434)
  Signal Layer 2 w5: J9.8@1500,399 1547,352 v1(4294,352)
  Bottom Layer w5: J11.8@1500,100 J11.8@1511,100 ; R51.1@4355.7,2065 4355.7,2040.3 v1(4356.58,2039.42)
  Bottom Layer w6: J9.8@1500,399 1553,346 1553,142 J11.8@1511,100 ; U9.6@1736.14,1438.56 1783.56,1438.56 v1(1784,1434)
GPIO9: J9.9 J11.9 R54.1 U9.7 | length 1572.9
  Signal Layer 1 w5: J9.9@1600,399 1649.2,448.2 1649.2,521.2 1744,616 1744,728.46 1809,793.46 v1(1809,1434)
  Bottom Layer w5: U9.7@1736.14,1412.97 1809,1412.97 ; v1(1809,1434) 1809,1412.97 ; R54.1@1830.03,1412.97 1809,1412.97
  Bottom Layer w6: J11.9@1600,104 1650,154 1650,349 J9.9@1600,399
GPIO10: J9.10 J11.10 R32.1 U9.8 | length 5163.6
  Signal Layer 1 w5: J9.10@1700,399 1759,458 1759,722 1858,821 1858,1380 v1(1850,1388) ; v1(4068,789) 4146,867 v1(4146,2125)
  Signal Layer 2 w5: v1(1851,815) 2426,815 2489,752 4029,752 v1@4065,788
  Bottom Layer w5: J11.10@1700,104 1752,156 1752,347 J9.10@1700,399 ; U9.8@1736.14,1387.38 1849.38,1387.38 v1(1850,1388) ; R32.1@4115.68,2125 v1(4146,2125)
GPIO11: J7.11 J9.11 J11.11 U1.53 U9.9 | length 3690.1
  Top Layer w5: U1.53@2997.26,1913 2997.26,1895.74 3007,1886 v1(3016,1886)
  Signal Layer 1 w5: J9.11@1800,399 1856,455 1856,572 1802,626 J7.11@1802,671 1802,736.26 1902,836.26 1902,1250 1880,1272 1880,1340 v1(1902,1362) 1905,1365 v1(1905,2200)
  Signal Layer 2 w5: v1(1905,2200) 2455.71,2200 2608.41,2047.29 2796.97,2047.29 2935.26,1909 2993,1909 v1(3016,1886)
  Bottom Layer w5: U9.9@1736.14,1361.79 1901.79,1361.79 v1(1902,1362) ; J11.11@1800,104 1849,153 1849,350 J9.11@1800,399
IO1: R74.1 U3.78 U8.14 | length 887.6
  Signal Layer 1 w5: v1(1431,1056) v1@1431,1134
  Signal Layer 2 w5: v1(828,1036) 903,1036 923,1056 1293,1056 1301,1048 1340,1048 1346.5,1054.5 1429.5,1054.5 v1(1431,1056)
  Bottom Layer w5: v1(828,1036) 828,996.48 U3.78@827.37,995.85 828,995.22 828,963 849,942 R74.1@849,926.68 ; v1@1431,1134 1503.2,1134 U8.14@1503.86,1134.65
  other v1: 1433,1132
IO2: R75.1 U3.71 U8.13 | length 754.7
  Signal Layer 1 w5: v1(1457.06,1109.06) 1457.06,1038.94 v1(1459,1037)
  Signal Layer 2 w5: v1(937.61,1035.61) 939,1037 1037,1037 1043,1043 1063,1043 1069,1037 v1(1459,1037)
  Bottom Layer w5: v1(937.61,1035.61) U3.71@937.61,995.85 938,995.46 R75.1@938,927.68 ; v1(1457.06,1109.06) U8.13@1503.86,1109.06
IO3: R76.1 U3.106 U8.12 | length 1280.5
  Signal Layer 1 w6: v1(1323,1204) v1@1325,1202 ; 1324.47,1106 1325,1105.47 ; v1(1325,1070) 1325,1105.47 ; v1@1327,1200 v1@1325,1202 ; 1325,1105.47 v1@1325,1202
  Signal Layer 2 w6: v1(534,1204) v1(1323,1204)
  Bottom Layer w6: v1(1325,1070) 1338,1083 1503.39,1083 U8.12@1503.86,1083.47
  Bottom Layer w8: R76.1@384.68,1236 406,1236 445.36,1196.64 U3.106@484.85,1196.64 526.64,1196.64 v1(534,1204)
IO4: R77.1 U3.41 U8.11 | length 904.2
  Signal Layer 1 w5: v1(1552,1058) 1553,1059 v1(1553,1417.11)
  Signal Layer 2 w5: v1(1139,1417.11) v1(1553,1417.11)
  Bottom Layer w5: U3.41@1091.15,1417.11 v1(1139,1417.11) 1173.52,1417.11 R77.1@1173.63,1417 ; U8.11@1503.86,1057.88 1551.88,1057.88 v1(1552,1058)
IO5: R78.2 U3.104 U9.18 | length 1716.8
  Signal Layer 1 w6: v1(1590,1158) v1(1590,1532)
  Signal Layer 2 w6: v1(535,1158) 564.29,1158 575.18,1168.89 1071.11,1168.89 1082,1158 1187,1158 1205,1140 1232,1140 1248,1156 1444.64,1156 1453.64,1147 1579,1147 v1(1590,1158) v1@1591,1158
  Bottom Layer w8: R78.2@383.69,1174 416.73,1174 425.59,1165.14 454.43,1165.14 ; U3.104@484.85,1165.14 527.86,1165.14 v1(535,1158) ; U9.18@1499.19,1516 1539,1516 1555,1532 v1(1590,1532)
  Bottom Layer w11: 454.43,1165.14 U3.104@484.85,1165.14
IO6: R79.2 U3.6 U9.17 | length 1122.9
  Signal Layer 1 w5: v1(1457.06,1479) 1457.06,1481.01 1463.99,1487.94 v1(1463.99,1598.14)
  Signal Layer 2 w5: v1(623,1564) 934.78,1564 968.92,1598.14 v1(1463.99,1598.14)
  Bottom Layer w5: v1(623,1564) 623,1601.8 U3.6@622.65,1602.15 R79.2@623,1658.3 ; v1(1457.06,1479) 1467.8,1489.74 U9.17@1503.86,1489.74
IO7: R80.2 U3.29 U9.16 | length 839.9
  Signal Layer 1 w5: v1(1321.31,1656.31) 1321,1656 1336,1641 v1(1336,1461)
  Signal Layer 2 w5: v1(938.18,1656.31) v1(1321.31,1656.31)
  Bottom Layer w5: v1(938.18,1656.31) R80.2@961,1656.31 961,1652.78 976.47,1637.32 976.8,1637.32 984.85,1629.27 U3.29@984.85,1602.15
  Bottom Layer w6: v1(1336,1461) U9.16@1504,1461
IO8: R81.2 U3.30 U9.15 | length 882.7
  Signal Layer 1 w5: v1(1569.56,1438.56) 1570,1439 v1(1570,1580)
  Signal Layer 2 w5: v1(1000,1562) 1016.1,1578.1 v1(1570,1580)
  Bottom Layer w5: R81.2@989,1655.63 1000.6,1644.03 U3.30@1000.6,1602.15 1000,1601.55 v1(1000,1562) ; U9.15@1503.86,1438.56 v1(1569.56,1438.56)
IO9: R82.2 U3.61 U9.14 | length 746.9
  Signal Layer 1 w6: v1(1384.15,1102.15) 1387,1105 1387,1326.54 1389,1328.54 1389,1343.46 1387,1345.46 v1(1387,1399)
  Signal Layer 2 w5: v1(1131,1102) 1384,1102 v1(1384.15,1102.15)
  Bottom Layer w5: U3.61@1091.15,1102.15 1091.3,1102 v1(1131,1102) 1131,1100.31 R82.2@1152.31,1079
  Bottom Layer w6: v1@1387,1400 1399.97,1412.97 U9.14@1503.86,1412.97
IO10: R49.2 U3.60 U9.13 | length 913.5
  Signal Layer 1 w5: v1(1023.1,1117.9) v1(1023.1,1401.9)
  Signal Layer 2 w5: v1(1023.1,1401.9) 1032.39,1401.61 1129.75,1401.61 1131.75,1399.61 1146.25,1399.61 1148.25,1401.61 1210.11,1401.61 1213,1404.5 1358.24,1404.5 1370.5,1392.24 1370.5,1392.17 1380.17,1382.5 1380.24,1382.5 1386.74,1376 1408.39,1376 v1(1419.76,1387.38)
  Bottom Layer w5: v1(1023.1,1117.9) U3.60@1091.15,1117.9 ; U3.60@1090.94,1120 R49.2@1145,1120 ; R49.2@1145.21,1117.9 R49.2@1150.31,1123
  Bottom Layer w6: v1(1419.76,1387.38) U9.13@1503.86,1387.38
IO11: R42.2 U3.105 U9.12 | length 1468.3
  Signal Layer 1 w6: v1(1571,1363) 1571,1185 v1@1573,1183
  Signal Layer 1 w8: v1(1572,1182) v1@1573,1183
  Signal Layer 2 w6: v1(550.89,1180.89) 1202.15,1180.89 1204.4,1183.14 1214.1,1183.14 1215.96,1185 1230.04,1185 1234.15,1180.89 1405.11,1180.89 1418,1168 1558,1168 v1(1572,1182)
  Signal Layer 2 w8: v1(550.89,1180.89) v1@551.78,1180
  Bottom Layer w8: R42.2@382.69,1199 389.63,1205.94 409.06,1205.94 434.11,1180.89 U3.105@484.85,1180.89 v1(550.89,1180.89) ; U9.12@1503.86,1361.79 1505.07,1363 v1(1571,1363)
MCUVCC: C83.1 C85.1 C87.2 C88.1 C89.1 C91.1 C96.2 C97.2 D6.1 J7.1 J31.1 R22.2 R23.2 R24.2 R42.1 R44.1 R47.2 R48.2 R49.1 R53.1 R55.2 R70.1 R71.1 R72.1 R73.1 R74.2 R75.2 R76.2 R77.2 R78.1 R79.1 R80.1 R81.1 R82.1 U2.3 U3.7 U3.8 U3.9 U3.16 U3.26 U3.28 U3.39 U3.47 U3.51 U3.52 U3.68 U3.69 U3.79 U3.90 U3.101 U3.113 U3.122 U4.8 U6.6 U7.1 U7.9 | length 4024.6
  Top Layer w8: v1(599.4,1951) D6.1@628.47,1951
  Signal Layer 1 w11: v1(161.68,727.69) 231.69,727.69 v1(264,760) ; v1(472.2,1818) 472.2,1885.2 538,1951 v1(599.4,1951)
  Signal Layer 2 w8: v1(1138,1449.01) 1203.99,1515 1266,1515 1289,1538 1341.9,1538 v1(1365,1561.1)
  Signal Layer 2 w11: v1(769.26,2004) 1034.66,2004 1060,2029.34 v1(1060,2032)
  Bottom Layer w5: R53.1@1394.31,1568 1403.68,1568 R55.2@1433.68,1598
  Bottom Layer w6: v1(1060,2032) 1060,2056 1066,2062 1095.25,2062
  Bottom Layer w8: R78.1@343.31,1175 R78.1@344.32,1174 ; R78.1@345.31,1175 R42.1@345.31,1205 R76.2@345.31,1236 ; 448.5,1305.17 448.5,1305.3 450.07,1306.87 U3.113@484.85,1306.87 ; U3.90@638.39,995.85 638.39,1023.89 v1(654.5,1040) ; U3.7@638.39,1602.15 U3.8@654.14,1602.15 ; C97.2@660,1681.44 654.14,1675.58 U3.8@654.14,1602.15 ; U3.9@669.89,1602.15 U3.8@654.14,1602.15 ; v1(770,1648) 777,1641 777,1640.13 778.87,1638.26 778.87,1603.4 U3.16@780.13,1602.15 ; 811.62,967.38 813,966 813,945 818,940 v1(820,940) 820,918.31 849,889.31 R74.2@849,887.31 ; U3.26@937.61,1602.15 937.61,1565.39 944,1559 962.4,1559 969.1,1565.7 U3.28@969.1,1602.15 ; R80.1@961,1695.68 R44.1@1017,1695.68 ; v1(1060,2032) U7.9@1084.57,2032
  Bottom Layer w9: 811.62,967.38 U3.79@811.62,995.85
  Bottom Layer w11: R47.2@144,727.69 v1(161.68,727.69) ; v1(264,760) 279,745 U4.8@287.41,745 ; R76.2@345.31,1236 345.31,1237.16 382.16,1274 v1(417.7,1274) 449,1305.3 ; v1(430,1127) 439.1,1117.9 U3.101@484.85,1117.9 ; U6.6@432.97,1830 460.2,1830 v1(472.2,1818) ; v1(439,1448.61) U3.122@484.85,1448.61 ; C83.1@834,783.32 902,783.32 C89.1@905,780.32 941.76,780.32 C91.1@988,826.56 ; R75.2@938,888.31 949.63,888.31 C87.2@988,926.69 984.85,929.83 U3.68@984.85,995.85 U3.69@969.1,995.85 ; U3.52@1091.15,1243.88 1122.25,1243.88 1148.56,1217.57 1148.56,1208.88 C85.1@1150.44,1207 ; U3.39@1091.15,1448.61 1163.61,1448.61 C96.2@1177,1462 1177,1453 R77.2@1213,1417 ; v1(1365,1561.1) 1371.9,1568 R53.1@1394.31,1568
  Bottom Layer w22: R22.2@398.31,2177 393.49,2172.18 393.49,2003 394.49,2004 v1(769.26,2004) C88.1@799.81,2002 ; J31.1@460,486 460,550.85 580.15,671 J7.1@802,671 ; R49.1@1189.68,1123 1189.68,1037.89 R48.2@1191.68,1035.89 ; R49.1@1189.68,1125 1219,1125 1252,1158 R73.1@1385.31,1158 ; R73.1@1385.31,1156 R73.1@1385.31,1158 ; R70.1@1385.32,1237.02 R73.1@1385.32,1158 ; R73.1@1386.32,1157 R73.1@1385.32,1158
  other v1: 954,1558
nERR_MCU: J7.8 U3.62 | length 907.4
  Signal Layer 1 w5: J7.8@1502,671 1504,673 v1(1504,1033)
  Signal Layer 2 w5: v1(1045.4,1086.4) 1105.6,1086.4 1113,1079 1135,1079 1142.4,1086.4 1298.4,1086.4 1303,1091 1331.38,1091 1335.98,1086.4 1364.6,1086.4 1373,1078 1395,1078 1403.4,1086.4 1452.6,1086.4 1504,1035 v1(1504,1033)
  Bottom Layer w5: v1(1045.4,1086.4) U3.62@1091.15,1086.4
nERR_SoC: J7.6 U3.50 | length 723.3
  Signal Layer 1 w5: v1(1141.68,1275) 1165,1251.68 1165,1088 1259,994 1259,714 J7.6@1302,671 J7.6@1303,672
  Bottom Layer w5: U3.50@1091.15,1275.38 1090.77,1275 v1(1141.68,1275)
NetC3_1: C3.1 J26.3 | length 258.9
  Bottom Layer w11: J26.3@3928.37,2680 C3.1@4187.26,2680
NetC9_2: C9.2 R65.2 TP2.1 U1.48 | length 1100.7
  Top Layer w11: U1.48@3095.68,1913 3095.68,1924.93 v1@3112,1941.24
  Signal Layer 1 w11: v1(3736.78,2148.11) 3720,2164.89 3720,2307 TP2.1@3783,2370
  Signal Layer 2 w11: v1(3112,1940) 3120.5,1948.5 3120.5,1949.08 3121,1949.58 3121,2027 3152,2058 3265.49,2058 3265.99,2058.5 3595.56,2058.5 3685.17,2148.11 v1(3736.78,2148.11)
  Bottom Layer w11: C9.2@3736.78,2094 v1(3736.78,2148.11)
NetC14_2: C14.2 R58.2 TP1.1 U1.4 | length 1081
  Top Layer w8: v1(2890.31,1819) 2890.31,1819.31 2899.35,1828.35 U1.4@2912.61,1828.35
  Signal Layer 1 w5: TP1.1@2436,2373 2436,2365 2372,2301 2372,1998.48 2411.02,1959.46 2472.54,1959.46 v1(2478,1954)
  Signal Layer 2 w28: 2672.78,1912.22 2714,1871 2811,1871 2863,1819 v1(2890.31,1819)
  Signal Layer 2 w33: 2487,1947 2513.78,1916.22 ; 2511.78,1912.22 2672.78,1912.22
  Bottom Layer w5: R58.2@2508.5,1952 R58.2@2508.81,1952.31
  Bottom Layer w18: C14.2@2852.68,1840.47 2868.53,1840.47 2890,1819 v1(2890.31,1819)
  Bottom Layer w22: v1(2478,1954) R58.2@2502.31,1954
NetC84_1: C84.1 C84.3 C86.1 C90.1 U3.87 U3.115 | length 751.5
  Signal Layer 1 w9: v1(553,1319) 553,1222 620,1155 v1(620,1148)
  Bottom Layer w8: U3.115@484.85,1338.37 533.63,1338.37
  Bottom Layer w9: 433,1341 435.63,1338.37 U3.115@484.85,1338.37 ; 533.63,1338.37 v1(553,1319) ; v1(620,1148) 694.17,1148 719.69,1122.49 719.69,1063.29 685.64,1029.24 U3.87@685.64,995.85 ; 685.64,966.88 C90.1@712,940.52
  Bottom Layer w11: C84.3@399.5,1309.32 421.82,1309.32 433,1320.5 433,1341 424.5,1349.5 C84.1@400,1349.5 ; C84.1@399.5,1348.68 399.5,1349.5 C84.1@400,1349.5 ; C86.1@400,1388.44 C84.1@400,1349.5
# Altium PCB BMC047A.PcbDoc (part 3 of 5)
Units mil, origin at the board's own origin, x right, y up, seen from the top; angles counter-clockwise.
Board outline 4950 x 3450 mil, 6 copper layers (Top Layer, GND Layer 1, Signal Layer 1, Signal Layer 2, GND Layer 2, Bottom Layer), stack 60.7 mil thick; 322 components, 160 nets, 1128 pads, 816 vias.

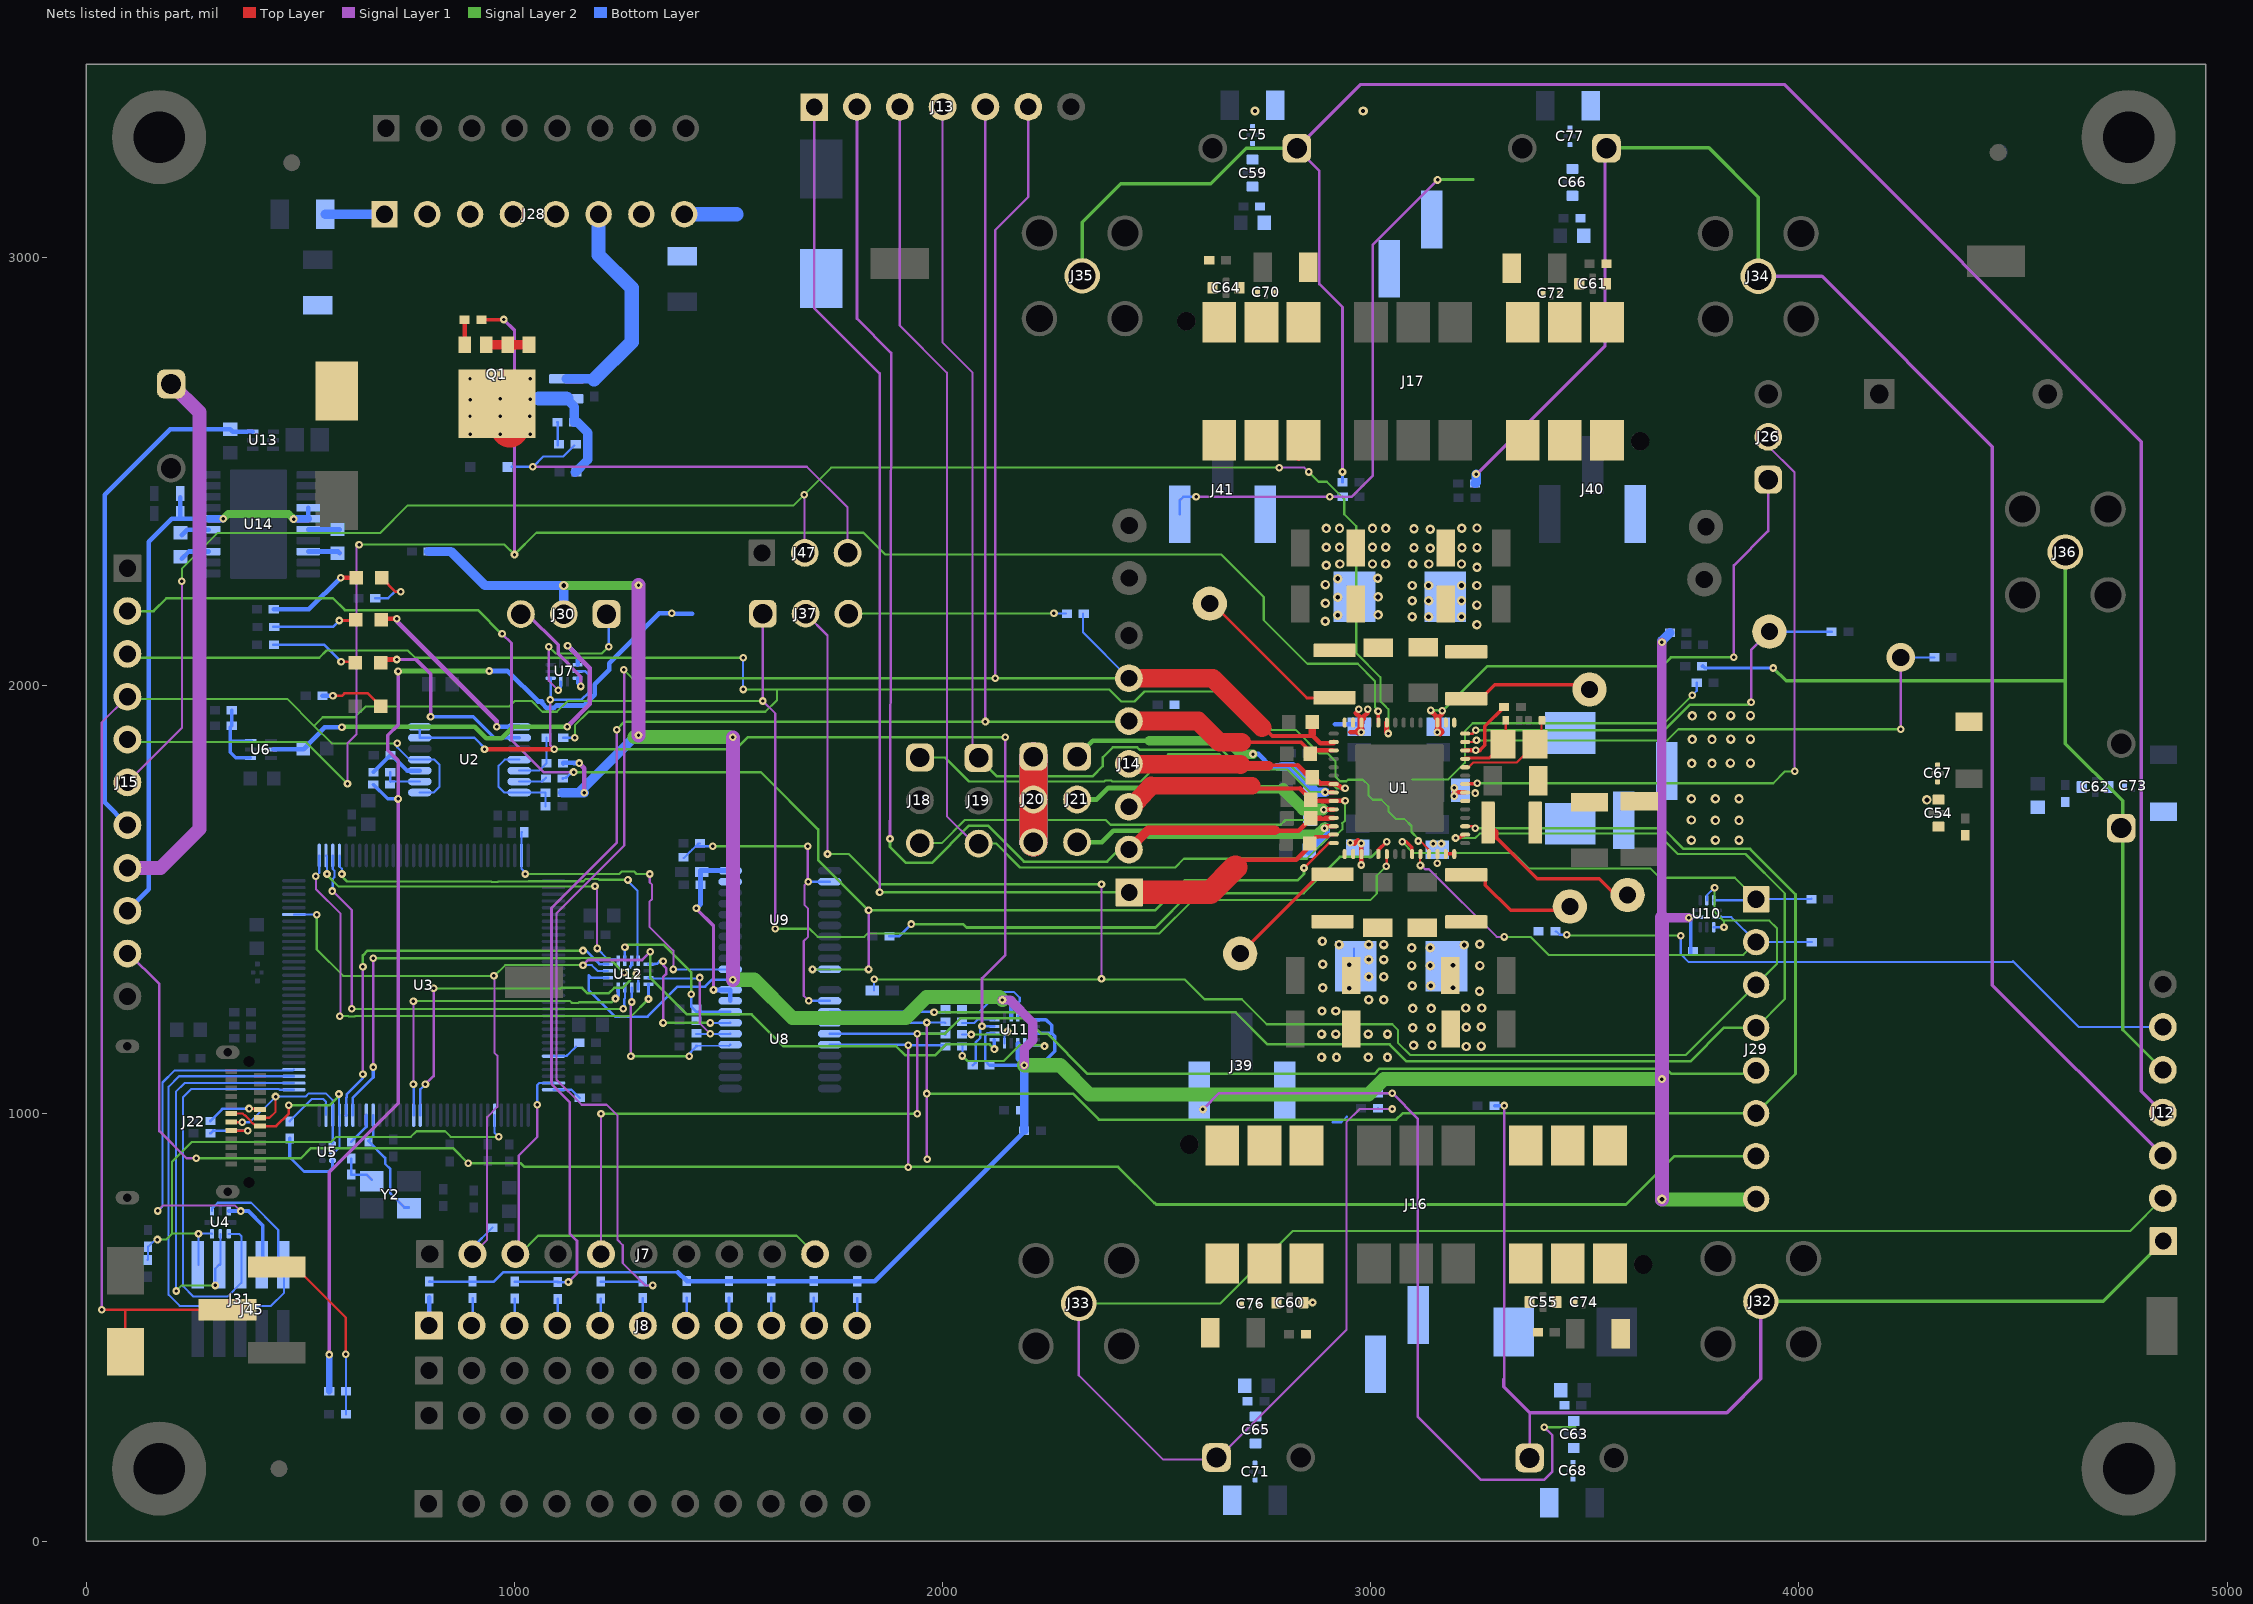
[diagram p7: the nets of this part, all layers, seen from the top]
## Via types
v1: diameter 18, hole 8, Top Layer to Bottom Layer, tented both sides, 476 vias
v2: diameter 22, hole 11, Top Layer to Bottom Layer, tented both sides, 261 vias
v3: diameter 22, hole 10, Top Layer to Bottom Layer, tented both sides, 36 vias
v4: diameter 19.68, hole 8, Top Layer to Bottom Layer, 21 vias
v5: diameter 19.68, hole 7.87, Top Layer to Bottom Layer, 9 vias
v6: diameter 19.68, hole 7.87, Top Layer to Bottom Layer, tented both sides, 6 vias
v7: diameter 20, hole 10, Top Layer to Bottom Layer, tented both sides, 4 vias
v8: diameter 18, hole 8, Top Layer to Bottom Layer, tented top, 2 vias
v9: diameter 66, hole 40, Top Layer to Bottom Layer, tented both sides, 1 vias

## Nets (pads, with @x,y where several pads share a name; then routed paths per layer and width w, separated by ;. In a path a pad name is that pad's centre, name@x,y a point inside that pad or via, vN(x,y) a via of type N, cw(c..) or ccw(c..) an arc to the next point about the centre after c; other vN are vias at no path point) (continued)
NetC92_1: C92.1 U3.88 Y2.1 | length 265.6
  Bottom Layer w6: U3.88@669.89,995.85 669.89,946.89 658.5,935.5 698,896 698,882.18 710,870.18 710,813 743,780 Y2.1@753,780
NetC95_1: C95.1 R50.2 Y2.3 | length 90.4
  Bottom Layer w6: R50.2@619,894.31 C95.1@619,856.68 654.5,856.68 Y2.3@666.69,844.5
NetC98_1: C98.1 R53.2 U8.19 U8.20 U9.19 U9.20 | length 459.3
  Signal Layer 1 w8: v1@1425,1477.69 1464.8,1437.88 v1(1464.8,1288.2)
  Signal Layer 1 w11: v1@1425,1477.69 v1(1425,1479)
  Bottom Layer w6: U9.20@1503.37,1567 U9.20@1503.86,1566.51
  Bottom Layer w11: v1(1425,1479) 1425.69,1479 1434.68,1488 1434.68,1536 1434.69,1567 U9.20@1503.37,1567 ; v1(1464.8,1288.2) U8.20@1503.86,1288.2 U8.19@1503.86,1262.61 ; U9.19@1503.86,1540.92 U9.20@1503.86,1566.51
NetC106_2: C106.2 J45.1 R33.2 | length 436.5
  Top Layer w5: J45.1@444.5,641 488,641 606,523 v1(606,437)
  Bottom Layer w5: v1(606,437) 606.24,436.76 C106.2@606.24,297
NetC115_1: C115.1 U14.13 | length 70
  Bottom Layer w6: U14.13@285.83,2312.2 U14.13@286.02,2312.02
  Bottom Layer w11: C115.1@223,2295.44 239.76,2312.2 U14.13@285.83,2312.2
NetC115_2: C115.2 U14.15 | length 68.3
  Bottom Layer w11: C115.2@223,2350.56 235.65,2363.2 U14.15@286.02,2363.2
NetC116_1: C116.1 U14.8 | length 75.2
  Bottom Layer w11: U14.8@518.3,2312.02 588.42,2312.02 C116.1@592,2308.44
NetC116_2: C116.2 U14.6 | length 73.8
  Bottom Layer w11: U14.6@518.3,2363.2 518.65,2363.56 C116.2@592,2363.56
NetD1_1: D1.1 J47.3 R21.2 | length 1048.6
  Signal Layer 1 w5: v1(1042.93,2510) 1683,2510 1778,2415 J47.3@1778,2309
  Bottom Layer w5: D1.1@992.77,2510 v1(1042.93,2510) 1043.24,2509.69 1067.56,2534 1114,2534 R21.2@1140,2560
NetD3_1: D3.1 R22.1 | length 223.4
  Top Layer w11: v1(594,2251) D3.1@630.47,2251
  Bottom Layer w11: R22.1@437.68,2177 520,2177 v1(594,2251)
NetD3_2: D3.2 R35.2 | length 123.7
  Top Layer w6: D3.2@689.53,2251 722.53,2218 v1(734,2218)
  Bottom Layer w6: R35.2@674.69,2203 704.73,2203 719.73,2218 v1(734,2218)
NetD4_1: D4.1 R23.1 | length 199.8
  Top Layer w6: v1(591,2151) 627.47,2151 D4.1@629.47,2153
  Bottom Layer w6: R23.1@436.68,2136 437.68,2136 576,2136 v1(591,2151)
NetD4_2: D4.2 U2.1 | length 439.5
  Top Layer w11: D4.2@688.53,2153 690.53,2155 v1(725,2155)
  Signal Layer 1 w11: v1(725,2155) 725,2149.36 957.68,1916.68 957.73,1916.73 958.23,1916.22 v1(958.23,1902.77)
  Bottom Layer w11: v1@958,1903 v1(958.23,1902.77) U2.1@1011.14,1902.77
NetD5_1: D5.1 R24.1 | length 209.2
  Top Layer w6: v1(595,2055) 625.47,2055 D5.1@628.47,2052
  Bottom Layer w6: R24.1@436.68,2094 556,2094 v1(595,2055)
NetD5_2: D5.2 U2.2 | length 465.9
  Top Layer w11: D5.2@679.53,2060 v1(725,2060)
  Signal Layer 1 w8: v1(725,2060) 770,2060 804,2026 v1(804,1926)
  Bottom Layer w8: v1(804,1926) 904,1926 952.82,1877.18 U2.2@1011.14,1877.18
NetD6_2: D6.2 R59.1 | length 150.8
  Top Layer w6: v1(576,1975) 597,1975 603,1981 657.53,1981 D6.2@687.53,1951
  Bottom Layer w11: R59.1@551.68,1975 v1(576,1975)
NetJ8_1: J8.1 R8.1 | length 69.1
  Bottom Layer w11: J8.1@801.18,501.18 R8.1@801.18,570.32
NetJ8_2: J8.2 R9.1 | length 65.1
  Bottom Layer w6: J8.2@900,504 902,506 R9.1@902,568.32
NetJ8_3: J8.3 R10.1 | length 63.7
  Bottom Layer w6: J8.3@1000,504 1001,505 R10.1@1001,567.32
NetJ8_4: J8.4 R11.1 | length 62.7
  Bottom Layer w6: J8.4@1100,504 1101,505 R11.1@1101,566.32
NetJ8_5: J8.5 R12.1 | length 63.7
  Bottom Layer w6: J8.5@1200,504 1201,505 R12.1@1201,567.32
NetJ8_6: J8.6 R13.1 | length 64.3
  Bottom Layer w6: J8.6@1300,504 R13.1@1300,568.32
NetJ8_7: J8.7 R14.1 | length 66.1
  Bottom Layer w6: J8.7@1400,504 1402,506 R14.1@1402,569.32
NetJ8_8: J8.8 R15.1 | length 65.7
  Bottom Layer w6: J8.8@1500,504 1501,505 R15.1@1501,569.32
NetJ8_9: J8.9 R16.1 | length 65.3
  Bottom Layer w6: J8.9@1600,504 R16.1@1600,569.32
NetJ8_10: J8.10 R17.1 | length 65.7
  Bottom Layer w6: R17.1@1699,569.32 1699,505 J8.10@1700,504
NetJ8_11: J8.11 R18.1 | length 64.7
  Bottom Layer w6: J8.11@1800,504 1801,505 R18.1@1801,568.32
NetJ22_A5: J22.A5 R41.1 | length 128.7
  Top Layer w6: v1(380,1011) 403.15,1011 404.15,1010 405.15,1009 J22.A5@405.45,1009.3
  Bottom Layer w6: R41.1@289.68,982 316.68,1009 317.68,1010 318.68,1011 v1(380,1011)
NetJ22_B5: J22.B5 R43.1 | length 129.6
  Top Layer w6: J22.B5@338.52,960.09 338.61,960 339.61,959 v1(377,959)
  Bottom Layer w6: R43.1@289.68,953 296.77,960.09 296.86,960 297.86,959 v1(377,959)
NetJ26_2: J26.2 U1.36 | length 1570.3
  Top Layer w8: U1.36@3217.22,1769.3 U1.36@3219.7,1769.3 ; U1.36@3219.81,1769.3 3247.7,1769.3 3249,1770.6 v1(3249,1771)
  Signal Layer 1 w5: J26.2@3928.37,2558.34 3990,2496.71 v1(3990,1798.59)
  Signal Layer 2 w5: v1(3249,1771) 3940,1771 3967.59,1798.59 v1(3990,1798.59)
NetJ30_1: J30.1 U7.7 | length 373.3
  Signal Layer 1 w5: v1(1080,2090) 1080,2009.91 v1(1101.91,1988)
  Signal Layer 2 w5: v1(1080,2090) 1096,2074 1204,2074 v1(1220,2090)
  Bottom Layer w5: v1(1101.91,1988) 1108.19,1994.28 U7.7@1108.19,2008.38 ; v1@1220,2088.04 J30.1@1220,2174.04
NetJ30_3: J30.3 U7.5 | length 258.2
  Signal Layer 1 w8: J30.3@1015,2166 1030,2166 1101.91,2094.09 1101.91,2073.09 1155,2020 v1(1155,1997)
  Bottom Layer w8: U7.5@1147.56,2016.25 1147.56,2004.44 v1(1155,1997)
NetJ37_3: J37.3 R30.2 | length 508.6
  Signal Layer 2 w5: J37.3@1780,2167 1780.63,2167.63 v1(2260,2167.63)
  Bottom Layer w5: v1(2260,2167.63) R30.2@2288.32,2167.63
NetJ39_1: J39.1 NT1.1 R2.2 | length 1840
  Signal Layer 1 w6: v1(2608,1009) 2646,1047 v8(3050.29,1047) 3109.54,987.75 3109.54,291.46 3257,144 3405,144 3424,163 3424,248 v1(3405,267)
  Signal Layer 2 w6: v1(3405,267) 3478,267
  Bottom Layer w6: R2.2@3016.81,1047.21 3017.01,1047 v8(3050.29,1047)
NetJ41_1: J41.1 NT2.1 R6.2 | length 1379
  Signal Layer 1 w6: v1@2587.77,2440 v1(2592,2440) v1(2904,2440) 2955.31,2440 3005,2489.69 3005,2662 3005,3029 v1(3156,3180)
  Signal Layer 2 w6: v1(3156,3180) 3157,3181 3239,3181
  Bottom Layer w6: J41.1@2554,2399 2554,2432 2562,2440 v1(2592,2440) ; v1(2904,2440) R6.2@2934.57,2440
NetNT3_2: NT3.2 R19.2 | length 813.3
  Signal Layer 2 w5: 3096,1780 3181,1780 3219.72,1818.72 3219.72,1892.46 3238.17,1910.91 3685.23,1910.91 v1(3751,1976.68)
  Bottom Layer w5: v1(3751,1976.68) 3761.31,1987 R19.2@3761.31,2006
NetQ1_4: Q1.4 R26.2 | length 58.8
  Top Layer w11: Q1.4@884,2794.95 R26.2@884,2853.73
NetR20_2: R20.2 R21.1 | length 54.5
  Bottom Layer w6: R20.2@1100.31,2614.39 1100.63,2614.08 R21.1@1100.63,2560
NetR28_1: R28.1 R36.2 U2.5 | length 130.1
  Bottom Layer w5: U2.5@1011.14,1800.41 1057.54,1800.41 R28.1@1074.32,1817.18 1074.59,1817.46 R36.2@1074.59,1877
NetR31_2: R31.2 R39.2 U6.1 U6.3 | length 198
  Bottom Layer w8: 339.69,1869.41 385.69,1869.41 U6.3@385.72,1869.37 ; R39.2@339.69,1941 R31.2@339.69,1905 336,1901.31 336,1843 349,1830 U6.1@383.03,1830
NetR37_1: R37.1 R38.2 U2.4 U2.7 | length 251.1
  Bottom Layer w5: U2.4@1011.14,1826 977,1826 963,1812 963,1762 975.77,1749.23 U2.7@1011.14,1749.23 1011.37,1749 R37.1@1072.73,1749 R38.2@1072.73,1717
NetR48_1: R48.1 U3.64 | length 69
  Bottom Layer w5: U3.64@1091.15,1054.91 1133.3,1054.91 R48.1@1152.31,1035.89
NetR50_1: R50.1 U3.89 | length 76.7
  Bottom Layer w6: R50.1@619,933.68 U3.89@654.14,968.83
  Bottom Layer w8: U3.89@654.14,968.83 U3.89@654.14,995.85
NetR51_2: R51.2 U1.41 | length 1277.1
  Top Layer w5: U1.41@3219.54,1867.27 U1.41@3220.54,1867.27 3243.27,1867.27 v1(3247,1871)
  Signal Layer 1 w5: v1(4237.91,1897) v9(4237.91,2065)
  Signal Layer 2 w5: v1(3247,1871) 3692.42,1871 3718.42,1897 v1(4237.91,1897)
  Bottom Layer w5: v9(4237.91,2065) R51.2@4316.33,2065
NetR52_1: R52.1 U3.59 | length 61.9
  Bottom Layer w5: U3.59@1091.15,1133.65 1121.65,1133.65 1128,1140 R52.1@1143.85,1155.85
NetR54_2: R54.2 U1.19 | length 1287.4
  Top Layer w8: U1.19@3016.94,1613.94 v1(3037,1634)
  Signal Layer 2 w6: v1(1927,1442) 2048,1442 2056,1434 2497,1434 2577,1514 2843,1514 2928,1599 3002,1599 v1(3037,1634)
  Bottom Layer w6: R54.2@1875.68,1414 1899,1414 v1(1927,1442)
NetR55_1: R55.1 R66.2 U8.2 U9.2 | length 791.5
  Signal Layer 1 w5: v1(1685.86,1540.92) 1677,1532.07 1677,1487 1685.86,1478.14 1685.86,1412.6 1675.5,1402.25 1675.5,1274.5 v1(1687.39,1262.61)
  Signal Layer 1 w6: v1(1684.86,1624) 1684.86,1541.92 v1(1685.86,1540.92)
  Signal Layer 2 w6: v1(1463,1624) v1(1684.86,1624)
  Bottom Layer w5: R55.1@1395.32,1596 1408.47,1609.16 1415.13,1615.81 1423.32,1624 1429.63,1630.32 R66.2@1433.69,1630.32
  Bottom Layer w6: R66.2@1423.32,1624 v1(1463,1624) ; v1(1685.86,1540.92) U9.2@1736.14,1540.92 ; v1(1687.39,1262.61) U8.2@1736.14,1262.61
NetR61_1: R61.1 U11.16 | length 79.5
  Bottom Layer w5: R61.1@2045.68,1211 2074.06,1211 2082.56,1219.5 2120.75,1219.5 U11.16@2120.75,1218.62
NetR62_1: R62.1 U11.3 | length 204
  Bottom Layer w5: R62.1@2045.68,1237.02 2085.93,1237.02 2131.92,1283 2167,1283 2180,1270 2180,1261 2177.16,1258.16 2177.16,1227.78 U11.3@2175.87,1226.5
NetR63_1: R63.1 U11.9 | length 288
  Signal Layer 2 w5: v1(2046,1134) 2058,1122 2142.46,1122 2179.46,1159 v1@2234.38,1159
  Bottom Layer w5: R63.1@2045.68,1158 2046,1157.68 v1(2046,1134) ; U11.9@2191.62,1163.5 2198.12,1157 ; U11.9@2192,1157 v1(2238,1157)
NetR64_1: R64.1 U11.12 | length 139.5
  Signal Layer 2 w5: v1(2067,1184) 2144.22,1184 v1(2151.46,1191.24)
  Bottom Layer w5: R64.1@2045.68,1184 v1(2067,1184) ; U11.12@2144.38,1163.5 2144.38,1181 2151.46,1188.09 v1(2151.46,1191.24)
NetR83_2: R83.2 U2.6 | length 66.2
  Bottom Layer w5: U2.6@1011.14,1774.82 1064.32,1774.82 R83.2@1073.5,1784
NetR93_2: R93.2 R94.2 U2.9 | length 91.7
  Bottom Layer w5: R94.2@709.69,1797 709.69,1774.78 710,1774.46 710.36,1774.82 U2.9@778.86,1774.82
NetR94_1: R94.1 R95.1 U2.10 | length 140.7
  Bottom Layer w9: R94.1@670.32,1797 709.32,1836 R95.1@710.68,1836 ; R95.1@710.68,1839 749.28,1800.41
  Bottom Layer w11: 749.28,1800.41 U2.10@778.86,1800.41
nINT: J15.2 R83.1 U1.14 U9.10 | length 3710.7
  Top Layer w6: v1(2844,1573) 2876.27,1605.27 2876.62,1605.27 2881.31,1609.95 2881.31,1610.31 2902.5,1631.5 U1.14@2912.61,1631.5
  Signal Layer 1 w6: v1(971,2120) 993,2098 993,1872.24 1068.24,1797 v1(1138,1797) ; v1(1827,1336) v1(1827,1474)
  Signal Layer 2 w5: v1(1696,1336) v1@1824,1336
  Signal Layer 2 w6: J15.2@96,2173 157,2173 187,2203 575.73,2203 603.73,2175 915,2175 970,2120 v1(971,2120) ; v1(1138,1797) 1575.19,1797 1709.19,1663 1709.19,1591.81 v1(1827,1474) ; v1@1832,1474 2496,1474 2566,1544 2829,1544 2844,1559 v1(2844,1573)
  Bottom Layer w5: v1(1696,1336) 1735.94,1336 U9.10@1736.14,1336.2
  Bottom Layer w6: R83.1@1112.68,1782 1121,1784.27 1124,1787.27 1130.68,1794 1133.68,1797 v1(1138,1797)
nINT3P3: R44.2 U3.31 U9.11 | length 781.2
  Signal Layer 1 w5: v1(1316,1559) 1316,1539 1321.5,1533.5 1321.5,1500.5 1315,1494 1315,1435.9 1371,1379.9 v1(1371,1336)
  Signal Layer 2 w5: v1(1025,1559) 1245,1559 1251,1565 1279,1565 1285,1559 v1(1316,1559)
  Bottom Layer w5: R44.2@1017,1656.31 1016.35,1655.66 U3.31@1016.35,1602.15 1016.35,1571.25 1025,1562.6 v1(1025,1559) ; v1(1371,1336) 1503.66,1336 U9.11@1503.86,1336.2
nPWRON: J15.4 J37.1 J45.2 S1.2 U1.20 U2.8 U2.11 | length 6153.6
  Top Layer w5: v1(36,541) 93,541 ; 91,539 93,541 ; J45.2@329.5,541 175,541 93,541 ; v1(3036,1577) 3037.47,1578.47 U1.20@3037.47,1605.46
  Top Layer w6: 91,539 S1.2@91,443.12 S1.2@93.62,440.5
  Signal Layer 1 w5: v1(36,541) 36,1913 J15.4@96,1973 ; J37.1@1580,2167 v1(1580,1963) 1609,1934 v1(1609,1431)
  Signal Layer 2 w5: J15.4@96,1973 101,1968 469,1968 531.5,1905.5 ; v1(726,1864) 573,1864 531.5,1905.5 ; v1(1580,1963) 1124,1963 1099,1938 1065,1938 1040,1963 1000.42,1963 987.42,1950 652.25,1950 627.25,1925 552,1925 532.5,1905.5 531.5,1905.5 ; v1(1609,1431) 1689,1431 1708,1412 1817,1412 1825,1420 2506,1420 2583.82,1497.82 2998.82,1497.82 3014,1513 3014,1555 v1(3036,1577)
  Bottom Layer w5: v1(726,1864) 726,1855.09 755.09,1826 U2.11@778.86,1826 813,1826 825,1814 825,1763 811.23,1749.23 U2.8@778.86,1749.23
nPWRON_S: J29.3 J37.2 R34.2 U10.4 U10.8 | length 4161.2
  Signal Layer 1 w5: J37.2@1680,2167 1731,2116 v1(1731,1605.67) ; v1(2371,1314) v1(2371,1535)
  Signal Layer 2 w5: v1(1731,1605.67) 1780.83,1605.67 1851.5,1535 v1@2367,1535 ; v1(1840,1313) 2371,1312.55 2565.62,1312.38 2611.5,1266.5 2698.5,1266.5 2757,1208 3050,1208 3064,1194 3064,1164 3092,1136 3736,1136 3949,1349 3949,1432 3931,1450 3824,1450 ; v1(3803,1527) 3803,1471 3824,1450 ; v1(3825,1434.5) 3825,1449 3824,1450
  Bottom Layer w5: R34.2@1839.31,1287 1839.31,1312.31 v1(1840,1313) ; U10.4@3785,1497.5 3785,1509 v1(3803,1527) ; U10.8@3800.75,1434.5 v1(3825,1434.5)
nRST_MCU: C82.1 J31.10 R47.1 U3.70 U4.7 | length 1289.1
  Signal Layer 2 w5: v1(166,705) 186,705 200,719 ; v1(262,719) 200,719 ; v1(963,945) 851,945 838,958 771,958 758,945 584,945 572,933 246,933 200,887 200,719
  Bottom Layer w5: C82.1@143,657.68 144,658.68 R47.1@144,688.32 144.32,688.32 162,706 164,704 165,705 v1(166,705) ; J31.10@262,645.53 v1(262,719) 292.74,719 U4.7@293.31,718.43 ; U3.70@953.35,995.85 953.35,954.65 v1(963,945)
nRSTOUT: J15.3 R36.1 U1.25 | length 3954
  Top Layer w5: v1(3111,1636) 3111,1637 3112,1638 3113,1637 3114,1638 3134.9,1617.1 U1.25@3134.9,1605.46
  Signal Layer 2 w5: J15.3@96,2073 105,2064 544,2064 561,2081 751,2081 768,2064 v1(1534,2064) ; J15.3@96,2098.5 J15.3@96,2100 ; v1(1141,1877) 1141,1906 1173,1938 1586,1938 1613,1965 1613,1990 ; v1(1534,1990) 1613,1990 ; v1(3111,1636) 3111,1641 3095,1657 3095,1671 3079,1687 3059,1687 3041,1705 3041,1716 3024.5,1732.5 3004.5,1732.5 2995,1742 2995,1766 2981.94,1779.06 2946.4,1779.06 2942.83,1775.5 2927.94,1775.5 2918,1785.44 2918,1821.71 2899.21,1840.5 2879.5,1840.5 2824.5,1895.5 2768.22,1895.5 2678.38,1985.34 2471.34,1985.34 2448,1962 2417,1962 2389,1990 1613,1990
  Bottom Layer w5: R36.1@1113.96,1877 v1(1141,1877) ; v1(1534,1990) v1(1534,2064)
OSC32KCAP: C23.1 U1.40 | length 159.1
  Top Layer w8: 3254.04,1848.04 3266,1860 3266,1903.68 C23.1@3311.32,1949
  Top Layer w11: U1.40@3219.7,1848.04 3219.74,1848 v1(3245,1848) 3254,1848 3254.04,1848.04
OSC32KIN: C17.2 U1.38 Y1.1 | length 232.2
  Top Layer w5: U1.38@3229.03,1808.67 3239.75,1819.39 3340.79,1819.39 Y1.1@3383.4,1862 ; Y1.1@3391,1874.79 3398.75,1882.54 C17.2@3398.75,1918
  Top Layer w6: U1.38@3219.7,1808.67 U1.38@3229.03,1808.67
OSC32KOUT: C16.2 U1.39 Y1.2 | length 167.5
  Top Layer w6: U1.39@3219.7,1828.35 3219.7,1829.89 3276.48,1829.89 Y1.2@3308.6,1862 3315.25,1868.65 C16.2@3315.25,1918 ; Y1.2@3284.79,1862 Y1.2@3284.79,1867
OVPGDRV: J15.5 R26.1 U1.52 | length 4416.2
  Top Layer w7.87: R26.1@922.68,2853.73 974.83,2853.73 v1(975.1,2854)
  Top Layer w8: U1.52@3016.94,1913 3017,1913.06 v1(3017,1939)
  Signal Layer 1 w5: v1(610,1770) 610,1864.27 631,1885.27 631,2322.2 v1(637,2328.2)
  Signal Layer 1 w7.87: v1(975.1,2854) 1000,2829.1 v1(1000,2305)
  Signal Layer 2 w5: J15.5@96,1873 102,1867 513,1867 v1(610,1770) ; v1(637,2328.2) 976.8,2328.2 v1(1000,2305) 1051,2356 1815,2356 1866,2305 2651,2305 2750.16,2205.84 2750.16,2151.84 2852,2050 2969.48,2050 3010,2009.48 3010,1949 3017,1942 v1(3017,1939)
PB0: R45.1 U3.95 | length 140.9
  Bottom Layer w5: R45.1@475,980.68 475,982 526,1033 554,1033 559.65,1027.35 U3.95@559.65,995.85
PVIN_LDO3: C5.1 J18.3 J21.2 U1.10 | length 1671.2
  Top Layer w9: v1(2890,1709) v1@2890.79,1709.79
  Top Layer w11: v1@2890.79,1709.79 U1.10@2913.46,1709.79
  Signal Layer 2 w5: J18.3@1947,1631 1998,1631 2052,1685 2381,1685 2392,1674 2790,1674 2801,1685 2867.51,1685 v1@2891.51,1709 ; v1(2890,1709) v1@2891.51,1709 ; v1@2891.51,1709 v1@2892.49,1709 ; v1@2891.51,1709 2892,1709.49 v1@2892.49,1709 ; v1@2892.49,1709 2893.87,1709 2894,1708.87 2893.31,1708.18 v1@2892.49,1709
  Signal Layer 2 w11: J21.2@2314,1733 2359.94,1733 2386.94,1760 2476,1760
  Signal Layer 2 w20: 2476,1757 2795,1757
  Signal Layer 2 w22: v1@2887,1710 2889,1708 v1(2890,1709)
  Signal Layer 2 w28: 2795,1757 2842,1710 v1@2887,1710
  Bottom Layer w22: C5.1@2854.56,1688 2876.8,1710.24 2879.05,1708 2880.05,1709 v1(2890,1709)
PVIN_LDO4: C6.1 J18.1 J21.1 U1.8 | length 1711.5
  Top Layer w11: v1@2891.77,1749 v1@2892.39,1749.61 ; v1(2893.31,1750.31) 2893.08,1750.31 v1@2892.39,1749.61 ; U1.8@2912.61,1749.61 v1@2892.39,1749.61
  Signal Layer 2 w5: J18.1@1947,1831 2005.45,1831 2061.45,1775 2377.76,1775 2379.86,1777.09 2394.08,1777.09 2396.17,1775 2463,1775 2526.74,1838.74 2646.63,1838.74 2682.5,1802.87 2691.2,1802.87 2691.33,1803 2805,1803 2857.69,1750.31 v1(2893.31,1750.31)
  Signal Layer 2 w11: J21.1@2314,1833 2351,1870 2483,1870
  Signal Layer 2 w22: 2483,1870 2660,1870 ; 2664,1870 2695,1839 v1(2725,1839)
  Bottom Layer w11: J21.1@2302,1810.74 J21.1@2302,1827 ; v1(2725,1839) 2737.82,1839 2766.82,1810 2782,1810
  Bottom Layer w18: 2782.38,1809.62 2789.77,1809.62
  Bottom Layer w22: 2792,1810 2817.14,1810 ; 2816.87,1807.66 C6.1@2857.54,1766.98 ; C6.1@2856.56,1766 2873.56,1749 2874.87,1750.31 v1(2893.31,1750.31)
PVIN_LDO12: C4.1 J21.3 U1.12 | length 693.9
  Top Layer w11: v1(2892,1666) 2896.42,1670.42 U1.12@2913.46,1670.42
  Signal Layer 2 w11: J21.3@2314,1633 2372,1633 2399,1660 2474,1660 2482,1652
  Signal Layer 2 w22: 2482,1652 2874.62,1652 2890.39,1667.77 v1@2893.49,1667.77
  Bottom Layer w22: C4.1@2856.56,1613 2893.49,1649.93 v1@2893.49,1667.77
S/P: R29.2 U2.13 U2.14 U7.4 U7.8 U11.15 | length 2586.9
  Top Layer w11: v1(930,1850) v1(1093,1850)
  Signal Layer 1 w6: v1(1083.83,1966) 1083.83,1859.17 v1(1093,1850) ; v1(2092,1203) 2092,1315 2146,1369 v1(2146,1878.5)
  Signal Layer 2 w6: v1(1093,1850) 1516.64,1850 1545.14,1878.5 v1(2146,1878.5)
  Bottom Layer w6: U2.14@778.86,1902.77 U2.13@778.86,1877.18 906.33,1877.18 933.51,1850 v1(930,1850) ; U7.8@1084.57,2016.25 1084.57,1966.74 v1(1083.83,1966) 1156.35,1966 1173.73,1983.38 1173.73,2023.79 1165.52,2032 U7.4@1147.56,2032 ; R29.2@2070.31,1111.96 2077,1118.65 2077,1165.54 2087.94,1176.49 2087.94,1198.94 v1(2092,1203) 2120.63,1203 U11.15@2120.75,1202.87
SCL1: U3.91 U12.3 | length 1023.1
  Signal Layer 1 w6: v1(670,1108) v1(670,1362)
  Signal Layer 2 w5: v1(670,1362) 1152.67,1362 1153.17,1362.5 1166.83,1362.5 1167.33,1362 1222,1362
  Signal Layer 2 w6: 1222,1362 v1(1256,1328)
  Bottom Layer w6: U3.91@622.65,995.85 622.65,1036.65 670,1084 ; v1(1256,1328) 1263.56,1335.56 1265.55,1335.56 1270.82,1340.83 1270.82,1342.82 1273.63,1345.63 U12.3@1273.63,1356.37
  Bottom Layer w8: 670,1084 v1(670,1108)
SCL1/SCK: R71.2 U8.17 U12.5 | length 380.5
  Signal Layer 1 w6: v1(1347,1211) 1347,1317.96 1354,1324.96 1354,1339.04 1347,1346.04 v1(1347,1355)
  Signal Layer 2 w6: v1(1347,1211) v1(1457,1211)
  Bottom Layer w5: R71.2@1424.69,1211 v1(1457,1211) 1503.43,1211 U8.17@1503.86,1211.43
  Bottom Layer w6: U12.5@1313,1348.5 1327.45,1348.5 1327.96,1349 1332.74,1349 1338.74,1355 v1(1347,1355) ; R71.2@1420,1211 R71.2@1424.69,1211
SCL2: U3.82 U12.12 | length 774.3
  Signal Layer 1 w5: v1@760,1068 764,1072 v1(764,1262)
  Signal Layer 2 w5: v1(764,1262) 1129.94,1262 1134.44,1257.5 1148.93,1257.5 1150.93,1259.5 1226,1259.5
  Signal Layer 2 w6: 1227.5,1259.5 v1(1236,1268)
  Bottom Layer w6: v1@760,1068 764.38,1063.62 U3.82@764.38,995.85
  Bottom Layer w8: v1(1236,1268) 1242.13,1274.13 U12.12@1242.13,1293.38
  other v1: 764,1068
SCL2/CS: R73.2 U8.15 U12.10 | length 419
  Signal Layer 1 w6: v1(1272,1133) 1272,1258 v1(1274,1260)
  Signal Layer 2 w6: v1(1272,1133) v1(1408,1133)
  Bottom Layer w5: R73.2@1423.69,1158 1425.7,1157.97 1500.61,1157 U8.15@1503.86,1160.24
  Bottom Layer w6: U12.10@1273.63,1293.38 1273.63,1270.37 v1(1274,1260) ; v1(1408,1133) 1401.69,1133 R73.2@1425.69,1157
SCL_I2C1/SCK_SPI: J29.6 R61.2 U1.31 U8.4 | length 3946.2
  Top Layer w6: U1.31@3219.7,1670.87 v1@3239.67,1670.87
  Signal Layer 1 w6: v1(1963,1212) v1(1963,1046) 1963,895 v1@1964,894
  Signal Layer 2 w6: v1(1963,1046) 2304,1046 2365,985 3059.2,985 3074.2,1000 J29.6@3900,1000 3992,1092 3992,1511.19 3885.78,1617.41 3730.59,1617.41 3682,1666 v1(3244,1666) ; v1(3244,1666) 3242.04,1666 3244,1667.96 v1(3244,1666)
  Bottom Layer w5: U8.4@1736.44,1211.72 U8.4@1736.14,1211.43 1962.43,1211.43 v1(1963,1212) 2005.31,1212 R61.2@2006.31,1211
  other v1: 1964,893
SCL_I2C2/CS_SPI: J15.10 J29.7 R63.2 U8.6 | length 4897.7
  Signal Layer 1 w6: J15.10@96,1400 96,1376 170.46,1301.54 170.46,958.54 234,895 v1(257,895) ; v1(1920,874) v1(1920,1159)
  Signal Layer 2 w6: v1(257,895) 501,895 524,918 857,918 v1(892,883) 1015,883 1023,875 1916,875 1917,874 v1(1920,874) 1920,875 2409.8,875 2494.3,790.5 2495.5,790.5 2499,787 3596,787 3709,900 J29.7@3900,900
  Bottom Layer w5: U8.6@1737.16,1159.22 U8.6@1736.14,1160.24 1918.76,1160.24 v1(1920,1159) 2005.31,1159 R63.2@2006.31,1158
SCLK_SPMI: J29.1 R68.2 U1.23 U10.5 | length 1161.8
  Top Layer w7.87: v1(3073.75,1634.07) 3082.93,1634.07 3095.68,1621.32 U1.23@3095.68,1605.91
  Signal Layer 1 w5: J29.1@3893.87,1506.13 J29.1@3900,1500
  Signal Layer 2 w5: v1(3073.75,1634.07) 3099.83,1608 3333,1608 3369,1572 3653,1572 3675,1550 3850,1550 J29.1@3900,1500
  Bottom Layer w5: U10.5@3800.75,1497.5 3895.5,1497.5 J29.1@3899,1501 ; J29.1@3900,1500.19 R68.2@4029,1500.19
SDA1: U3.92 U12.16 | length 971.5
  Signal Layer 1 w6: v1(646,1091) v1(646,1342)
  Signal Layer 2 w6: v1(646,1342) 646,1369 657,1380 v1(1160,1380)
  Bottom Layer w6: U3.92@607,995.95 607,1036.54 608,1037.54 608,1044 646,1082 ; v1(646,1091) v1@647,1091 ; v1(1160,1380) 1167,1380 1198.5,1348.5 U12.16@1218.51,1348.5
  Bottom Layer w8: U3.92@606.9,995.85 U3.92@607,995.95
SDA1/SDI: R70.2 U8.18 U12.2 | length 392.2
  Signal Layer 2 w6: v1(1257.88,1388) 1263.88,1394 1348,1394 1413,1329 v1(1413,1278)
  Bottom Layer w6: U12.2@1257.88,1356.37 v1(1257.88,1388) ; v1(1413,1278) 1413,1248.7 1424.69,1237.02 U8.18@1503.86,1237.02
SDA2: U3.81 U12.9 | length 850.7
  Signal Layer 1 w6: v1(792,1068) 811,1087 v1(811,1292)
  Signal Layer 2 w6: v1(811,1292) 1107.2,1291 1109.2,1293 1157.86,1293 1170.86,1280 1220,1280 1233,1293 1252,1293 v1(1285,1326) v1@1289,1326
  Bottom Layer w6: U3.81@780.13,995.85 780.13,1056.13 v1(792,1068) ; v1(1285,1326) 1289.38,1321.62 U12.9@1289.38,1293.38 U12.9@1289.38,1289.31
SDA2/SDO: R72.2 U8.16 U12.7 | length 343.8
  Signal Layer 1 w5: v1(1432.69,1317) 1432.69,1210.38 v1(1457.06,1186)
  Bottom Layer w5: U12.7@1313,1317 1313,1314.5 1430.19,1314.5 v1(1432.69,1317) ; R72.2@1424.69,1185 1503.02,1185 U8.16@1503.86,1185.83
SDA_I2C1/SDI_SPI: J29.4 R62.2 U1.30 U8.3 | length 3465.6
  Top Layer w8: v1(3198,1643) 3206,1643 3207.77,1644.77 3210.28,1644.77 U1.30@3212.51,1647 ; U1.30@3215.51,1648 3216.01,1648.5 3216.51,1648 U1.30@3219.7,1651.19
  Signal Layer 2 w5: v1(3198,1643) 3244.33,1643 3254.6,1653.27 3669.73,1653.27 3717.33,1605.67 3875.11,1605.67 3967,1513.78 3967,1267 J29.4@3900,1200
  Signal Layer 2 w6: v1(1980,1236) 2684,1236 2759,1161 3044,1161 3083.5,1121.5 3746.78,1121.5 3825.28,1200 J29.4@3900,1200
  Bottom Layer w6: U8.3@1736.14,1237.02 1978.98,1237.02 v1(1980,1236) 2005.3,1236 R62.2@2006.31,1237.02
SDA_I2C2/SDO_SPI: J7.5 J29.5 R64.2 U8.5 | length 3566.6
  Signal Layer 1 w5: J7.5@1202,671 v1(1202,999)
  Signal Layer 1 w6: v1(1941,999) v1(1941,1186)
  Signal Layer 2 w6: v1(1202,999) v1(1941,999) ; v1(1941,1186) 2006,1186 2042,1222 2194,1222 2230,1186 2244.5,1186 2338.52,1091.98 2969.93,1091.98 2984.04,1092 3008.33,1091.98 3020.85,1104.5 3690.15,1104.5 3702.67,1091.98 3891.98,1091.98 J29.5@3900,1100
  Bottom Layer w6: U8.5@1736.14,1185.83 1940.83,1185.83 v1(1941,1186) 2004.31,1186 R64.2@2006.31,1184
SDATA_SPMI: J29.2 R69.2 U1.24 U10.7 | length 1157.1
  Top Layer w5: U1.24@3115.21,1605.46 3115.21,1578.79 3116,1578 v1(3116,1579)
  Signal Layer 1 w5: v1(3116,1579) 3117.72,1579 3126.78,1569.94 3136.06,1569.94 3294,1412 v1(3312,1412)
  Signal Layer 2 w5: v1(3312,1412) 3373,1412 3415,1370 3870,1370 J29.2@3900,1400
  Bottom Layer w5: U10.7@3808.62,1458.13 3841.87,1458.13 J29.2@3900,1400 R69.2@4029.85,1400
SPI_CLK: U3.4 U12.4 | length 935.1
  Signal Layer 2 w5: v1(597,1559) 592.7,1559 592,1558.3 608.8,1541.5 945.75,1541.5 946.75,1540.5 961.25,1540.5 962.25,1541.5 1032.25,1541.5 1032.75,1542 1161,1542 1166.5,1547.5 1195.25,1547.5 1197.25,1545.5 1261.5,1545.5 v1@1265,1542
  Bottom Layer w5: U3.4@591.15,1602.15 592,1601.3 592,1575.84 597,1570.84 v1(597,1559) ; v1(1265,1545) 1265,1541.78 1287.5,1519.28 1287.5,1358.25 U12.4@1289.38,1356.37
SPI_CS: U3.3 U12.11 | length 1067.1
  Signal Layer 1 w5: v1(574,1519) 576,1519 620,1475 v1(620,1244)
  Signal Layer 2 w5: v1(620,1244) v1@1253,1244
  Bottom Layer w5: v1(574,1519) 575.4,1520.4 575.4,1547.65 579.5,1551.75 579.5,1566.25 575.4,1570.35 U3.3@575.4,1602.15 ; v1@1255,1244 1257.88,1246.88 1257.88,1251.37 1256.5,1252.75 1256.5,1267.25 1257.88,1268.63 U12.11@1257.88,1293.38
  other v1: 1254,1244
SPI_EN: J7.2 R46.2 U3.123 U11.13 U12.15 | length 2760.5
  Signal Layer 1 w5: J7.2@902,671 936,705 936,991 960,1015 960,1134.5 953,1141.5 953,1320 v1(952,1321)
  Signal Layer 1 w6: v1(1160,1346) 1172,1358 1298,1358 v8(1317,1377)
  Signal Layer 2 w5: v1(538,1464) 538,1384 537.5,1383.5 600,1321 v1(952,1321) 953.25,1321 978.25,1346 v1(1160,1346)
  Signal Layer 2 w6: v8(1317,1377) 1317,1317 1403,1231 1553.91,1231 1628.36,1156.54 1891.7,1156.54 1912.24,1136 1983,1136 2008,1161 2110,1161 v1(2121,1150)
  Bottom Layer w5: U3.123@484.85,1464.35 485.2,1464 v1(538,1464) ; J7.2@902,671 902,686.69 R46.2@948.31,733 ; v1(1160,1346) 1180.5,1346 1193.75,1332.75 U12.15@1218.51,1332.75
  Bottom Layer w8: U11.13@2120.75,1171.38 2121,1171.13 v1(2121,1150)
SPI_MISO: U3.1 U12.8 | length 1175.9
  Signal Layer 1 w5: v1(536,1554) 536,1524 594,1466 594,1229 v1(592,1227)
  Signal Layer 2 w5: v1(592,1227) 612.25,1227 612.75,1226.5 627.25,1226.5 627.75,1227 1246.25,1227 1246.75,1226.5 1261.25,1226.5 1261.75,1227 1273,1227 v1(1313,1267)
  Bottom Layer w5: v1(536,1554) 543.91,1561.91 U3.1@543.91,1602.15
  Bottom Layer w6: v1(1313,1267) U12.8@1313,1301.25
SPI_MOSI: U3.2 U12.1 | length 891.8
  Signal Layer 1 w5: v1(1188,1530) 1193,1525 v1(1193,1385)
  Signal Layer 2 w5: v1(562,1559) 562,1556.65 588.65,1530 941.69,1530 942.19,1529.5 965.81,1529.5 966.31,1530 v1@1187,1530
  Bottom Layer w5: U3.2@559.65,1602.15 562,1599.8 v1(562,1559) ; v1(1193,1385) 1218.07,1359.93 1236.6,1359.93 U12.1@1242.13,1354.4
SW_B1: L1.1 TP9.1 U1.27 U1.28 | length 248.1
  Top Layer w7.87: U1.27@3174.43,1605.91 U1.28@3194.11,1605.91 ; L1.1@3267,1550 3267.2,1532.34 3326.86,1474 3440,1474 TP9.1@3450,1484
SW_B2: L2.1 TP10.1 U1.15 U1.16 | length 290.9
  Top Layer w7.87: L2.1@2899.88,1547 L2.1@2911,1558.12
  Top Layer w8: TP10.1@2695,1373 2870,1548 L2.1@2897.73,1548
SW_B3: L3.1 TP11.1 U1.43 U1.44 | length 315
  Top Layer w7.87: L3.1@3221,1957.88 L3.1@3227,1963.88 ; L3.1@3223,1967.88 3256.57,1967.88 3289.98,2001.29 3499.71,2001.29 TP11.1@3511,1990
SW_B4: L4.1 TP12.1 U1.55 U1.56 | length 389.7
  Top Layer w6: TP12.1@2648,2190 2624.85,2166.85 2654.06,2166.85 2850.91,1970 ; 2851,1969.91 2850.91,1970 ; L4.1@2900.1,1970 2874.26,1970 2850.91,1970
SW_B5: L5.1 TP13.1 U1.34 | length 429.1
  Top Layer w7.87: L5.1@3273.88,1679 3294,1658.88 3294,1643 3389,1548 3533.6,1548 3574.6,1507 3595,1507 3600,1512 TP13.1@3585.31,1512 ; 3290,1645 3294,1641
SYNCCLKIN: R32.2 TP8.1 U1.42 | length 1027
  Top Layer w6: U1.42@3219.54,1886.95 U1.42@3220.54,1886.95 3237.54,1886.95 v1(3245,1894.41)
  Signal Layer 1 w6: v1(3888.31,1960) 3888.31,2082.31 TP8.1@3931,2125
  Signal Layer 2 w6: v1(3245,1894.41) 3685.04,1894.41 3744.63,1954 3882.31,1954 v1(3888.31,1960)
  Bottom Layer w6: TP8.1@3931,2125 R32.2@4076.31,2125
TCK: J31.4 U3.100 U4.3 | length 1014
  Signal Layer 1 w5: v1(167,772) 180,785 347,785 v1(360.43,771.57)
  Bottom Layer w5: v1(167,772) 177.79,782.79 177.79,1071.79 206.21,1100.21 482.91,1100.21 U3.100@484.85,1102.15
  Bottom Layer w9: U4.3@332.68,771.57 v1(360.43,771.57) 378.43,771.57 412,738 J31.4@412,645.53
TDI: J31.8 U3.98 U4.6 | length 971.5
  Signal Layer 2 w5: v1(210,585) 223,598 v1(301,598)
  Bottom Layer w5: v1(210,585) 210,588 209,589 209,1050 229.65,1070.65 U3.98@484.85,1070.65 ; v1(301,598) 301,637.24 J31.8@310,646.24 ; J31.8@312,645.53 313,646.53 U4.6@313,718.43
TDO: J31.6 U3.97 U4.5 | length 1009.2
  Bottom Layer w5: U4.5@332.68,718.43 356.92,718.43 362,713.34 362,604 330,572 250,572 226,596 226,1038 244.5,1056.5 383.25,1056.5 383.35,1056.4 385.25,1056.4 385.35,1056.5 449.25,1056.5 450.84,1054.91 U3.97@484.85,1054.91
TMS: J31.2 U3.99 U4.1 | length 1426.2
  Bottom Layer w5: U4.1@293.31,771.57 293.31,777.52 306.7,790.9 384.83,790.9 448.36,727.37 448.36,657.87 J31.2@460,646.24 ; J31.2@462,646.24 462,580.82 431.4,550.23 218.18,550.23 192.12,576.29 192.12,1062.1 216.42,1086.4 U3.99@484.85,1086.4
TRIG_WDG: J7.3 J7.10 U3.63 | length 1191.8
  Signal Layer 1 w5: J7.3@1002,671 1010,679 1010,901.5 1053,944.5 v1(1053,1020)
  Signal Layer 2 w5: J7.3@1002,671 1012,671 1055,714 1659,714 J7.10@1702,671
  Bottom Layer w5: v1(1053,1020) 1053,1066 1057.65,1070.65 U3.63@1091.15,1070.65
USB_ID: R45.2 U5.3 | length 177.8
  Bottom Layer w6: 475,897.56 508.56,864 565.67,864 574.91,873.24 U5.3@574.91,889.69
  Bottom Layer w9: 475,897.56 R45.2@475,941.31
USBD_N: J22.A7 J22.B7 U3.93 U5.2 | length 455.5
  Top Layer w5: J22.B7@338.52,999.46 365.21,999.46 369.17,995.5 370.17,995.5 370.83,995.5 372.83,993.5 373.83,992.5 384.17,982.17 384.17,980.6 388.56,976.21 390.13,976.21 396.41,969.93 J22.A7@405.45,969.93
  Top Layer w6: J22.A7@405.45,969.93 442.93,969.93 473,1000 v1(473,1019)
  Signal Layer 2 w6: v1(473,1019) 569,1019 590,1040 v1(590,1045)
  Bottom Layer w5: U5.2@574.91,909.37 579.69,909.37 591.15,920.83 591.15,921.81 591.29,921.95 591.29,936.16 591.15,936.3 U3.93@591.15,995.85 590,997 v1(590,1045)
USBD_P: J22.A6 J22.B6 U3.94 U5.1 | length 452.7
  Top Layer w5: J22.B6@338.52,979.77 338.75,980 339,979.75 339.25,980 340.25,981 342.25,979 v1(364,979) ; J22.A6@405.45,989.61 427.61,989.61 442,1004 v1(442,1039)
  Bottom Layer w5: v1(364,979) 382,979 v1(442,1039) 511.8,1039 511.9,1038.9 519.54,1046.54 559.46,1046.54 575.4,1030.6 U3.94@575.4,995.85 575.4,930.53 U5.1@573.93,929.06
V3V3: C111.2 J15.7 U13.6 | length 1205.2
  Bottom Layer w11: J15.7@96,1673 43,1726 43,2445 195.56,2597.56 C111.2@336,2597.56 341.87,2591.69 U13.6@388.66,2591.69
V5V0: C112.1 C113.1 J15.9 U14.4 U14.5 U14.16 | length 1362.4
  Signal Layer 2 w18: v1(320,2388.8) 331.2,2400 472,2400 v1(484,2388)
  Bottom Layer w11: J15.9@96,1473 146,1523 146,2335 200,2389 C113.1@219,2389 ; C112.1@219,2438.76 C113.1@219,2401 C113.1@219,2389 ; U14.16@286.02,2388.8 285.81,2389 C113.1@219,2389 ; U14.5@518.3,2388.8 U14.4@518.3,2414.39
  Bottom Layer w18: U14.16@286.02,2388.8 v1(320,2388.8) ; v1@484.01,2389 U14.5@518.3,2388.8
VCC1P8: C109.1 U6.5 U7.3 | length 1018.1
  Signal Layer 1 w11: v1(1123,1903) 1176,1956 1176,2039.87 v1(1123.94,2091.94)
  Signal Layer 2 w11: v1(597,1902) 598,1903 907.5,1903 934.5,1876 970,1876 997,1903 v1(1123,1903)
  Bottom Layer w11: U6.5@436.62,1850 507.44,1850 507.97,1850.56 556.44,1902 v1(597,1902) ; v1@1124,2092 v1(1123.94,2091.94) 1147.56,2068.32 U7.3@1147.56,2047.75
VCCA: C7.1 C36.2 C47.1 C58.1 C69.1 C78.1 C94.1 C99.1 C117.1 J20.1 J20.2 J20.3 J26.1 J28.1 J28.2 J28.3 J28.4 J28.5 J28.6 J28.7 J28.8 Q1.1 Q1.2 Q1.3 R25.2 R33.1 R40.2 R58.1 R93.1 U1.17 U1.26 U1.35 U1.45 U1.54 | length 5835.9
  Top Layer w11: v1(2952,1632) 2954,1632 2956,1630 2958,1632 2959,1631 2960,1632 2962,1630 2970,1638 v1(2977.69,1630.31) 2977.69,1605.91 2978,1605.6 v1(2978,1580) ; 2952.43,1890.23 2965.04,1890.23 2966.4,1891.6 ; 2965.04,1934.85 2973.96,1925.94 2973.96,1899.15 2966.4,1891.6 ; v1@2967,1937.6 2967.6,1937 2972,1941.4 v1(2972,1944) ; v1@2977,1896.29 v1@2978,1897.29 ; v1@2979,1894 v1@2979,1896.29 ; 2980,1899.29 v1@2979,1898.29 ; v1(2993,1944) 2993,1936.06 2982.88,1925.94 2982.88,1920.19 2979,1916.31 2980,1915.31 2977.69,1913 2979.65,1911.04 2977,1908.39 2979,1906.39 v1@2979,1898.29 ; v1(3140,1941) 3140,1940.02 3155,1925.02 3152.51,1922.53 3155,1920.05 v1@3155,1892.41 ; v1@3153,1894.41 v1@3155,1892.41 ; v1(3155,1890) v1@3155,1892.41 ; v1(3167,1940) 3167,1932.89 3160.04,1925.94 3160.04,1899.15 3167,1892.19 3167,1889.59 3162.41,1885 v1@3155,1892.41 ; v1@3194,1748.48 3195.13,1749.61 U1.35@3219.81,1749.61 ; 2966.4,1891.6 2970,1888 v1@2978.65,1896.65 ; v1@2978,1897.29 v1@2979,1898.29 ; v1@2978,1897.29 v1@2978.65,1896.65 ; v1@2978.65,1896.65 v1@2979,1896.29 ; v1@2978.65,1896.65 v1@2979,1897 ; v1@2979,1896.29 v1@2979,1897 ; v1@2979,1897 v1@2979,1898.29 ; v1@2979,1897 2979.65,1897.65 v1@2979,1898.29
  Top Layer w22: Q1.3@934,2794.95 Q1.2@984,2794.95 Q1.1@1034,2794.95
  Top Layer w66: J20.3@2212,1633 J20.2@2212,1733 J20.1@2212,1833
  Signal Layer 1 w6: v1(3848,2065) 3848,2279.78 3928,2359.78 3928,2479.63 J26.1@3928.37,2480
  Signal Layer 1 w8: v1(567.32,436.44) 567.32,862.32 728,1023 v1(728,1734.27) 728,1824 704,1848 704,1883 728,1907 v1(728,2032)
  Signal Layer 1 w66: J20.3@2212,1633 J20.2@2212,1733 J20.1@2212,1833
  Signal Layer 2 w6: v1(3140,1941) 3163,1941 3166,1938 3272,2044 3680,2044 3701,2065 v1(3848,2065)
  Signal Layer 2 w11: v1(728,2032) 729,2033 v1(941,2033)
  Bottom Layer w8: R93.1@670.02,1768 703.82,1734.2 703.9,1734.27 v1(728,1734.27)
  Bottom Layer w11: v1(941,2033) 984,2033 1055,1962 1064.33,1962 1064.33,1957.92 1075.75,1946.5 1091.9,1946.5 1097.9,1952.5 1161.94,1952.5 1187.23,1977.79 1187.23,2001.73 1221,2035.51 1221,2051 1337.63,2167.63 v1(1367,2167.63) 1367.63,2167 1415,2167 ; 2916.68,1909 2972.53,1909 C69.1@2973,1908.53
  Bottom Layer w15: v1@567,436.76 v1(567.32,436.44) R33.1@567.32,351
  Bottom Layer w22: C7.1@557.59,3100 J28.1@696.38,3100 ; R25.2@1121,2715.18 1184.5,2715.18 C99.1@1186,2713.69
  Bottom Layer w33: C99.1@1186,2713.69 1274,2801.69 1274,2927.5 1196.38,3005.12 J28.6@1196.38,3100 ; J28.8@1396.38,3100 1518.4,3100 1518.71,3099.69
  Bottom Layer w66: J20.3@2212,1633 J20.2@2212,1733 J20.1@2212,1833
  other v1: 3155,1584 3146,1630 3165,1630 3195,1741 3244,1748 3195,1760 2978,1890
VCCA_S: J12.6 R40.1 | length 1537.9
  Signal Layer 2 w5: v1(3458,1417) 3460,1415 v1(3724,1415)
  Bottom Layer w5: R40.1@3431.5,1425 3433.5,1425 3441.5,1417 v1(3458,1417) ; v1(3724,1415) 3724,1372 3743,1353 4498,1353 4500,1355 4653.5,1201.5 J12.6@4850,1201.5
VIO_IN: C100.1 C107.2 C108.2 C110.2 J29.8 J30.2 R8.2 R9.2 R14.2 R15.2 R16.2 R17.2 R18.2 R28.2 R29.1 R37.2 R65.1 U10.1 U11.2 U11.5 U11.7 U11.10 U11.14 U12.14 | length 8914.2
  Signal Layer 1 w11: v1(1151.07,1818) 1163,1806.07 v1(1163,1749)
  Signal Layer 1 w22: v1(2139.59,1264.59) 2157.41,1264.59 2210.5,1211.5 2210.5,1170.48 2190.77,1150.75 v1(2190.77,1112.23) ; v1(3680,2100) 3680,1457 3682,1459 3684,1457 v1(3743,1457)
  Signal Layer 1 w33: v1(1289.68,1882.68) v1(1289.68,2233.68) ; v1(1510,1312) v1(1510,1878.04) ; v2(3680,799) v1(3680,1080) 3680,1457
  Signal Layer 2 w22: v2(1115,2232.68) v1(1289.68,2233.68) ; J29.8@3899,799 J29.8@3900,800
  Signal Layer 2 w33: 1280,1879 v1@1502,1879 ; v1(1510,1312) 1560,1312 1649,1223 1914,1223 1962.24,1271.24 2132.94,1271.24 v1(2139.59,1264.59) ; v1(2190.77,1112.23) 2274.77,1112.23 2343,1044 2995,1044 3031,1080 v1(3680,1080) ; v2(3680,799) J29.8@3899,799
  Bottom Layer w6: R8.2@802,607.5 R8.2@801.18,606.69 951.69,606.69 974,629 1381.69,629 ; U12.14@1218.51,1317 1178.62,1317 1173,1322.62 1173,1288 1235,1226 1311,1226 1381,1296 1445,1296 1461,1312 v1(1510,1312) ; R29.1@2109.68,1111.96 2100,1121.65 2100,1181.83 2105.29,1187.13 U11.14@2120.75,1187.13
  Bottom Layer w8: R29.1@2109.68,1111.96 2190.5,1111.96 v1(2190.77,1112.23) ; v1(2190.77,1112.23) 2229.24,1112.24 2262,1145 2262,1179.66 2254.54,1187.13 ; U11.7@2215.24,1187.13 2254.54,1187.13 ; U11.5@2215.24,1218.62 2241.38,1218.62 2254.54,1205.46 2254.54,1187.13 ; C110.2@3746.91,1371.31 v1@3746.91,1457.22
  Bottom Layer w11: R28.2@1113.69,1817.18 1113.69,1818.5 1138.35,1818.5 1138.51,1818.34 1150.73,1818.34 v1(1151.07,1818) ; 1381.69,629 R14.2@1402,608.69 1403,607.69 R18.2@1801,607.69 1841.46,607.69 C108.2@2190.77,957 ; U11.2@2160.12,1226.5 2160.13,1264.06 2160.66,1264.59 ; U11.10@2175.87,1163.5 2175.87,1127.13 v1(2190.77,1112.23)
  Bottom Layer w18: v1(2139.59,1264.59) 2160.66,1264.59
  Bottom Layer w20: C108.2@2190.49,959.24 2191.04,959.79 2191.04,1111.96 v1(2190.77,1112.23)
  Bottom Layer w22: C100.1@799.68,2312.2 851.52,2312.2 931.04,2232.68 v2(1115,2232.68) J30.2@1115,2166 ; R37.2@1112.1,1749 1151.18,1749 ; v1(1163,1749) 1151.18,1749 ; 1280.5,1878.68 1151,1749.18 1151.18,1749 ; v1(3680,2100) 3680,2103.54 R65.1@3698.46,2122
VOUT_B1: C18.1 C24.2 C29.2 C35.1 C39.1 C46.1 C50.1 C55.1 C55.3 C63.1 C63.3 C68.1 C68.3 C74.1 C74.3 C79.1 C103.1 J1.1 J12.1 J16.1 J16.2 J23.1 J24.2 J32.1 J42.2 J43.1 L1.2 R1.2 | length 2623.1
  Signal Layer 1 w6: 3311,379 3312,380 v1(3312,1018) ; J1.1@3371,195 3371,301
  Signal Layer 1 w8: 3311,379 3311,361 3371,301 3832,301 3911,380 J32.1@3911,560.88
  Signal Layer 2 w8: J32.1@3911,560.88 4710.38,560.88 J12.1@4851,701.5
  Bottom Layer w7.87: R1.2@3289,1018 v1(3312,1018)
  other v2: 3223,1156 3258,1157 3100,1159 3143,1159 3098,1200 3141,1200 3223,1201 3258,1202 3098,1245 3141,1245 3222,1246 3259,1246 3254,1285 3192,1293 3097,1298 3140,1298 3096,1345 3139,1345 3255,1345 3192,1346 3096,1387 3139,1387 3218,1393 3254.28,1395
VOUT_B2: C19.1 C25.2 C30.2 C40.1 C43.1 C51.1 C56.1 C60.1 C60.3 C65.1 C65.3 C71.1 C71.3 C76.1 C76.3 C102.1 J2.1 J12.2 J16.5 J16.6 J23.2 J33.1 J39.3 J42.1 L2.2 R3.2 | length 4350.4
  Signal Layer 1 w5: J33.1@2318,556 2318,388 2515,191 2634.57,191 J2.1@2639.57,196 2645,196 2943,494 2943,979 2974,1010 v1(3050,1010)
  Signal Layer 2 w5: J33.1@2318,556 2649,556 2818,725 4773.5,725 J12.2@4850,801.5
  Bottom Layer w5: 2911,979 2931,979 2944,992 ; J23.2@2961.09,1346 J23.2@2961.09,1385.22 ; R3.2@3016.68,1012 3018.69,1010 v1(3050,1010)
  other v1: 2864,558
  other v3: 2885.04,1131 2920.04,1131 2994,1131 3039,1131 2885.04,1185 2918,1185 2994,1185 3039,1185 2886,1239 2918,1239 2995,1265 3030,1265 2950,1292 2888,1293 2995,1319 3030,1319 2950,1347 2888,1348 2995,1359 3030,1359 2926,1394 2995,1394 3030,1394 2887,1402
VOUT_B3: C20.1 C26.2 C31.2 C41.1 C44.1 C52.1 C57.1 C61.1 C61.3 C66.1 C66.3 C72.1 C72.3 C77.1 C77.3 C104.1 J3.1 J12.3 J17.1 J17.2 J24.1 J25.2 J34.1 J40.3 J43.2 J44.1 L3.2 R5.2 | length 4031.1
  Signal Layer 1 w7.87: v1(3246,2493) 3248,2493 3547,2792 3547,3250.57 J3.1@3550.43,3254 ; J34.1@3905,2955 4054,2955 4452,2557 4452,1299.5 J12.3@4850,901.5
  Signal Layer 2 w7.87: J3.1@3550.43,3254 3551.43,3255 3790,3255 3905,3140 J34.1@3905,2955
  Bottom Layer w22: R5.2@3243.68,2471 3245,2472.31 3246,2473.31 v1(3246,2493)
  other v2: 3247.96,2141.05 3097,2160 3135,2160 3212,2160 3248,2187 3097,2197 3135,2197 3212,2197 3097,2232.68 3135,2232.68 3212,2232.68 3247.96,2232.7 3248.07,2275.35 3098,2283 3135.82,2283 3212,2283 3139,2320 3101,2321 3213,2321 3248.1,2321.3 3138.92,2364 3101,2365 3212.61,2366.7 3248.07,2367
VOUT_B4: C21.1 C27.2 C32.2 C37.1 C42.1 C48.1 C53.1 C59.1 C59.3 C64.1 C64.3 C70.1 C70.3 C75.1 C75.3 C105.1 J4.1 J12.4 J17.5 J17.6 J25.1 J35.1 J41.3 J44.2 L4.2 R7.2 | length 5490.9
  Top Layer w22: J17.5@2831.09,2535.41 J17.5@2831.5,2535
  Signal Layer 1 w6: J4.1@2827.43,3254 2880,3201.43 2880,2936.98 2934,2882.98 v1(2934,2498)
  Signal Layer 1 w7.87: J4.1@2827.43,3254 2976.43,3403 3966,3403 4800,2569 4800,1051.5 J12.4@4850,1001.5
  Signal Layer 2 w7.87: J35.1@2326,2956 2326,3081 2416,3171 2626,3171 2709,3254 J4.1@2827.43,3254
  Bottom Layer w6: v1(2934,2498) 2934,2474.31 R7.2@2934.31,2474
  other v2: 2894,2149 2922.92,2163 3017,2164 2894.08,2191 2923,2205 3017,2206 2894.08,2235 2922.92,2249 3016,2250 2895.92,2280 2928,2283 3004,2283 3035,2283 2896,2322 2927,2322 3004,2322 3035,2322 2896,2366 2926.92,2366 3004,2366 3034.92,2366
  other v3: 2729.62,3341 2982,3341
VOUT_B5: C22.1 C28.2 C33.2 C34.1 C38.1 C45.1 C49.1 C54.1 C54.3 C62.1 C62.3 C67.1 C67.3 C73.1 C73.3 C101.1 J5.1 J12.5 J36.1 L5.2 R67.2 | length 2171.3
  Signal Layer 1 w7.87: J5.1@4753,1666.15 J5.1@4753,1669.18
  Signal Layer 2 w6: 4756,1195.5 J12.5@4850,1101.5
  Signal Layer 2 w7.87: v1@3940,2041 v1(3940,2040) 3970,2010 4622,2010 ; J36.1@4622.18,2311 4622.18,1863.41 4756,1729.59 4756,1195.5
  Bottom Layer w7.87: R67.2@3773.89,2043.76 3775.46,2045.33 3780.8,2040 v1(3940,2040)
  other v2: 3749,1638 3805,1638 3860,1638 3805,1684 3860,1684 3749,1685 4299,1732 3749,1735 3805,1735 3860,1735 3750,1817.18 3797,1817.18 3840,1818 3887,1818 3751,1873.18 3797,1873.18 3841,1874 3887,1874 3751,1928.18 3797,1928.18 3841,1929 3887,1929
VOUT_LDO1: C8.1 J13.1 J14.1 U1.13 | length 3187.1
  Top Layer w9: C8.1@2854.69,1630 2856.24,1631.43 2872,1646 2898.79,1646 2903.52,1650.73 U1.13@2912.46,1650.73 ; C8.1@2857.56,1630 2863,1630 C8.1@2866.69,1630
  Top Layer w11: J14.1@2446,1513 2446,1515 J14.1@2447,1516 ; 2684,1575 2701.5,1592.5 2825.5,1592.5 C8.1@2863,1630
  Top Layer w22: J14.1@2436,1516 J14.1@2447,1516
  Top Layer w55: J14.1@2447,1516 2625,1516 2684,1575
  Signal Layer 1 w6: J13.1@1700,3350 1700,2881 1852.75,2728.25 v1(1852.75,1516.25) ; 1852.75,1669.62 v1(1852.75,1516.25) ; v1@1853,1516 v1(1852.75,1516.25)
  Signal Layer 2 w6: v1(1852.75,1516.25) 2435.08,1516.25 2435.33,1516 J14.1@2436,1515.33
VOUT_LDO2: C10.1 J13.2 J14.2 U1.11 | length 2970.8
  Top Layer w11: 2776.75,1661 2777.75,1660 2831.56,1660 C10.1@2863.56,1692 ; C10.1@2862.56,1689 2863.29,1688.27 2884.04,1688.27 ; C10.1@2863.56,1690.56 2880.86,1690.56 2881.92,1689.5 2882.82,1689.5 2884.04,1688.27 ; 2901.98,1688.27 2893,1688.27 ; U1.11@2912.61,1690.56 2904.86,1690.56 U1.11@2903.8,1689.5 ; U1.11@2913.46,1690.1 2913.46,1689.5 U1.11@2903.8,1689.5 ; 2884.04,1688.27 2893,1688.27 ; 2893,1688.27 2894.23,1689.5 U1.11@2903.8,1689.5
  Top Layer w22: J14.2@2435,1616 2480,1661 2776.75,1661
  Signal Layer 1 w6: J13.2@1800,3351 1800,2856 1879.79,2776.21 1877.32,1683.15 1877,1682.83 v1(1877,1641)
  Signal Layer 2 w6: v1(1877,1641) 1877,1622 1914,1585 1975,1585 2062,1672 2106,1672 2190,1588 2384,1588 2412,1616 J14.2@2435,1616
VOUT_LDO3: C11.1 J13.3 J14.3 J19.3 U1.9 | length 3347.8
  Top Layer w9: 2723,1765 2729.48,1758.52 2834.97,1758.52
  Top Layer w11: 2834.97,1758.52 2863.56,1729.93 2882.08,1729.93 ; 2885.51,1729.5 2901.49,1729.5 2901.92,1729.93 2939.01,1729.93 v1@2938.94,1730 ; v1@2937,1731.94 v1@2938.94,1730 ; v1(2940,1730) v1@2938.94,1730
  Top Layer w22: 2473.37,1754.37 2474.6,1753.15
  Top Layer w40: 2487,1765 2723,1765
  Top Layer w44: J14.3@2435,1716 2442.25,1716 2487,1765
  Signal Layer 1 w5: J13.3@1900,3351 1900,2840 2010,2730 2010,1693.61 2073.61,1630 J19.3@2084,1630 ; J19.3@2084,1651.26 J19.3@2106.3,1651.26
  Signal Layer 2 w5: J19.3@2084,1630 2124.87,1630 2180.87,1574 2543,1574 2563.5,1594.5 2850.5,1594.5 2909.27,1653.27 2909.58,1652.96 2923.25,1652.96 2933.69,1663.4 2933.69,1677.07 2933.38,1677.38 2940,1684 v1(2940,1730)
VOUT_LDO4: C12.1 J13.4 J14.4 J19.1 U1.7 | length 3120.5
  Top Layer w9: 2762,1811.69 2763.08,1812.77 2827.12,1812.77
  Top Layer w11: 2829,1813 C12.1@2859,1783 ; C12.1@2862.12,1784 2869.01,1784 2883.51,1769.5 2884.82,1770.81 2901.8,1770.81 2903.31,1769.3 U1.7@2912.33,1769.3 ; U1.7@2912.61,1769.3 2920.7,1769.3 2924.62,1765.38 2926.26,1765.38 2932.65,1759 v1(2940,1759)
  Top Layer w22: 2608.31,1811.69 2762,1811.69
  Top Layer w44: J14.4@2435,1816 2696,1815
  Signal Layer 1 w5: J13.4@2000,3351 2000,2800 2070,2730 2070,1844 J19.1@2084,1830
  Signal Layer 2 w5: 2686.85,1813.37 2811.16,1813.37 2856.72,1767.81 2911.19,1767.81 2920,1759 v1(2940,1759)
  Signal Layer 2 w6: J19.1@2084,1830 2126.33,1787.67 2350.81,1787.67 2374,1810.86 2374,1831 2398,1855 2454.37,1855 2460.13,1849.24 2650.98,1849.24 2686.85,1813.37
VOUT_LDOVINT: C15.1 J13.6 J14.6 R12.2 R13.2 R30.1 U1.2 | length 5095.9
  Top Layer w9: 2746,1901 2750.4,1901 2769.85,1881.56 2861.56,1881.56 2863,1883
  Top Layer w11: 2863,1887 2863,1883 2881.77,1864.23 2899.88,1864.23 2900.14,1864.49 2913.46,1864.49 U1.2@2913.46,1867.27
  Top Layer w18: 2863,1887 2863.11,1910.02 C15.1@2863.12,1912
  Top Layer w44: J14.6@2435,2016 2631,2016 2746,1901
  Signal Layer 1 w5: v1(1255,2036) 1256.5,2034.5 1256.5,1625.5 1098,1467 1098,1078.7 1156.79,1019.91 1215.23,1019.91 1241,994.15 1241,704 1253,692 1253,650 1305,598 v1(1323,598) ; v1(2123,2016) 2123,3063 2200,3140 J13.6@2200,3351
  Signal Layer 2 w5: v1@1254,2038 v1@1255,2038 ; v1(1255,2036) 1275,2016 v1(2123,2016) J14.6@2435,2016
  Bottom Layer w5: R12.2@1201,606.69 1299,606.69 1307.69,598 v1(1323,598) ; R30.1@2327.69,2167.63 2327.69,2123.31 J14.6@2435,2016 J14.6@2434,2015
VOUT_LDOVRTC: C13.1 J13.5 J14.5 R10.2 R11.2 U1.3 | length 4647.3
  Top Layer w8: 2698,1866.56 2837,1866.56
  Top Layer w9: 2837,1866.56 2860.56,1843 C13.1@2860.56,1840
  Top Layer w11: 2875,1848 U1.3@2911,1848
  Top Layer w44: J14.5@2435,1916 2597,1916 2646.44,1866.56 2698,1866.56
  Signal Layer 1 w6: v1(1126,606) 1146,626 1146,702 1129,719 1129,1026.29 1086.71,1068.59 1086.71,1073.73 1086.5,1073.94 1086.5,1479.5 1239,1632 v1(1239,1896) v1@1239,1897 ; v1(2100,1915) J13.5@2100,3351
  Signal Layer 2 w6: v1@1239,1897 1257,1915 v1(2100,1915) 2434,1915 J14.5@2435,1916
  Bottom Layer w6: R10.2@1001,606.69 1100,606.69 R11.2@1101,605.69 1125.69,605.69 v1(1126,606)
VSYS: C1.1 C2.1 C93.1 J6.1 J15.8 Q1.5 R20.1 R25.1 | length 1570.3
  Top Layer w88: Q1.5@988.57,2599 Q1.5@988.57,2623.62
  Signal Layer 1 w33: J15.8@96,1573 173,1573 264,1664 264,2637.43 J6.1@198,2703.43
  Bottom Layer w22: R25.1@1121,2669.18 1139.68,2650.5 R20.1@1139.68,2614.39 1146.61,2614.39 1171,2590 1171,2526.32 C93.1@1141.68,2497
  Bottom Layer w33: 1056.82,2669.18 R25.1@1121,2669.18
  other v1: 896.38,2586 967,2586 1037,2586 896,2628 967,2628 1036,2628 896.38,2667 1037,2668 967,2669 896,2716 967,2716 1037,2716
VSYS_SENSE: J15.6 J47.2 U1.51 | length 4147.8
  Top Layer w11: U1.51@3036.63,1913 3036.63,1891.37 v1(3041,1887)
  Signal Layer 1 w5: J15.6@96,1773 223,1900 v1(223,2243) ; v1(1677,2445) 1677,2310 J47.2@1678,2309 ; v1(2786,2508) 2845,2508 v1(2855,2498)
  Signal Layer 2 w5: v1(223,2243) 223,2272 306,2355 686,2355 751,2420 1652,2420 v1(1677,2445) 1740,2508 v1(2786,2508) ; v1(2855,2498) 2878,2475 2897.38,2475 2938,2434.38 2938,2399 2966,2371 2966,2074.98 3022.5,2018.48 3022.5,1962.5 3022.58,1962.5 3031.58,1953.5 ; 3032.5,1952.5 3041,1944 v1(3041,1887)
pads on no net: FID1.1 FID2.1 FID3.1 FID4.1 FID5.1 FID6.1 J16.ALIGN1 J16.ALIGN2 J17.ALIGN1 J17.ALIGN2 J22.A2 J22.A3 J22.A8 J22.A10 J22.A11 J22.ALIGN1 J22.ALIGN2 J22.B2 J22.B3 J22.B8 J22.B10 J22.B11 LBL1.0 SH-J1.0 SH-J2.0 SH-J3.0 SH-J4.0 SH-J5.0 SH-J6.0 SH-J7.0 SH-J8.0 SH-J9.0 SH-J10.0 SH-J11.0 SH-J12.0 SH-J13.0 SH-J14.0 SH-J15.0 SH-J16.0 U3.5 U3.11 U3.12 U3.13 U3.14 U3.15 U3.18 U3.19 U3.20 U3.21 U3.22 U3.23 U3.24 U3.25 U3.27 U3.32 U3.33 U3.34 U3.35 U3.36 U3.37 U3.38 U3.40 U3.42 U3.43 U3.44 U3.45 U3.46 U3.49 U3.53 U3.54 U3.56 U3.57 U3.65 U3.66 U3.67 U3.72 U3.73 U3.74 U3.75 U3.76 U3.77 U3.83 U3.84 U3.85 U3.86 U3.102 U3.103 U3.107 U3.108 U3.109 U3.110 U3.111 U3.112 U3.116 U3.117 U3.118 U3.119 U3.120 U3.121 U3.124 U3.125 U3.126 U3.127 U3.128 U4.2 U5.5 U7.2 U7.10 U10.2 U10.10 U11.1 U11.4 U11.8 U11.11 U13.5 U14.21@402.16,2376 Y2.2 Y2.4
copper on no net: | length 3.1
  Signal Layer 1 w6: 2332,857 2333,858
  Signal Layer 2 w6: 1289,1497.15 1289,1498
  Bottom Layer w9: 2779.4,163 2780,163.6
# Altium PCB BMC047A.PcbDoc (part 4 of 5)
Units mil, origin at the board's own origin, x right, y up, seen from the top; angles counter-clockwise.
Board outline 4950 x 3450 mil, 6 copper layers (Top Layer, GND Layer 1, Signal Layer 1, Signal Layer 2, GND Layer 2, Bottom Layer), stack 60.7 mil thick; 322 components, 160 nets, 1128 pads, 816 vias.

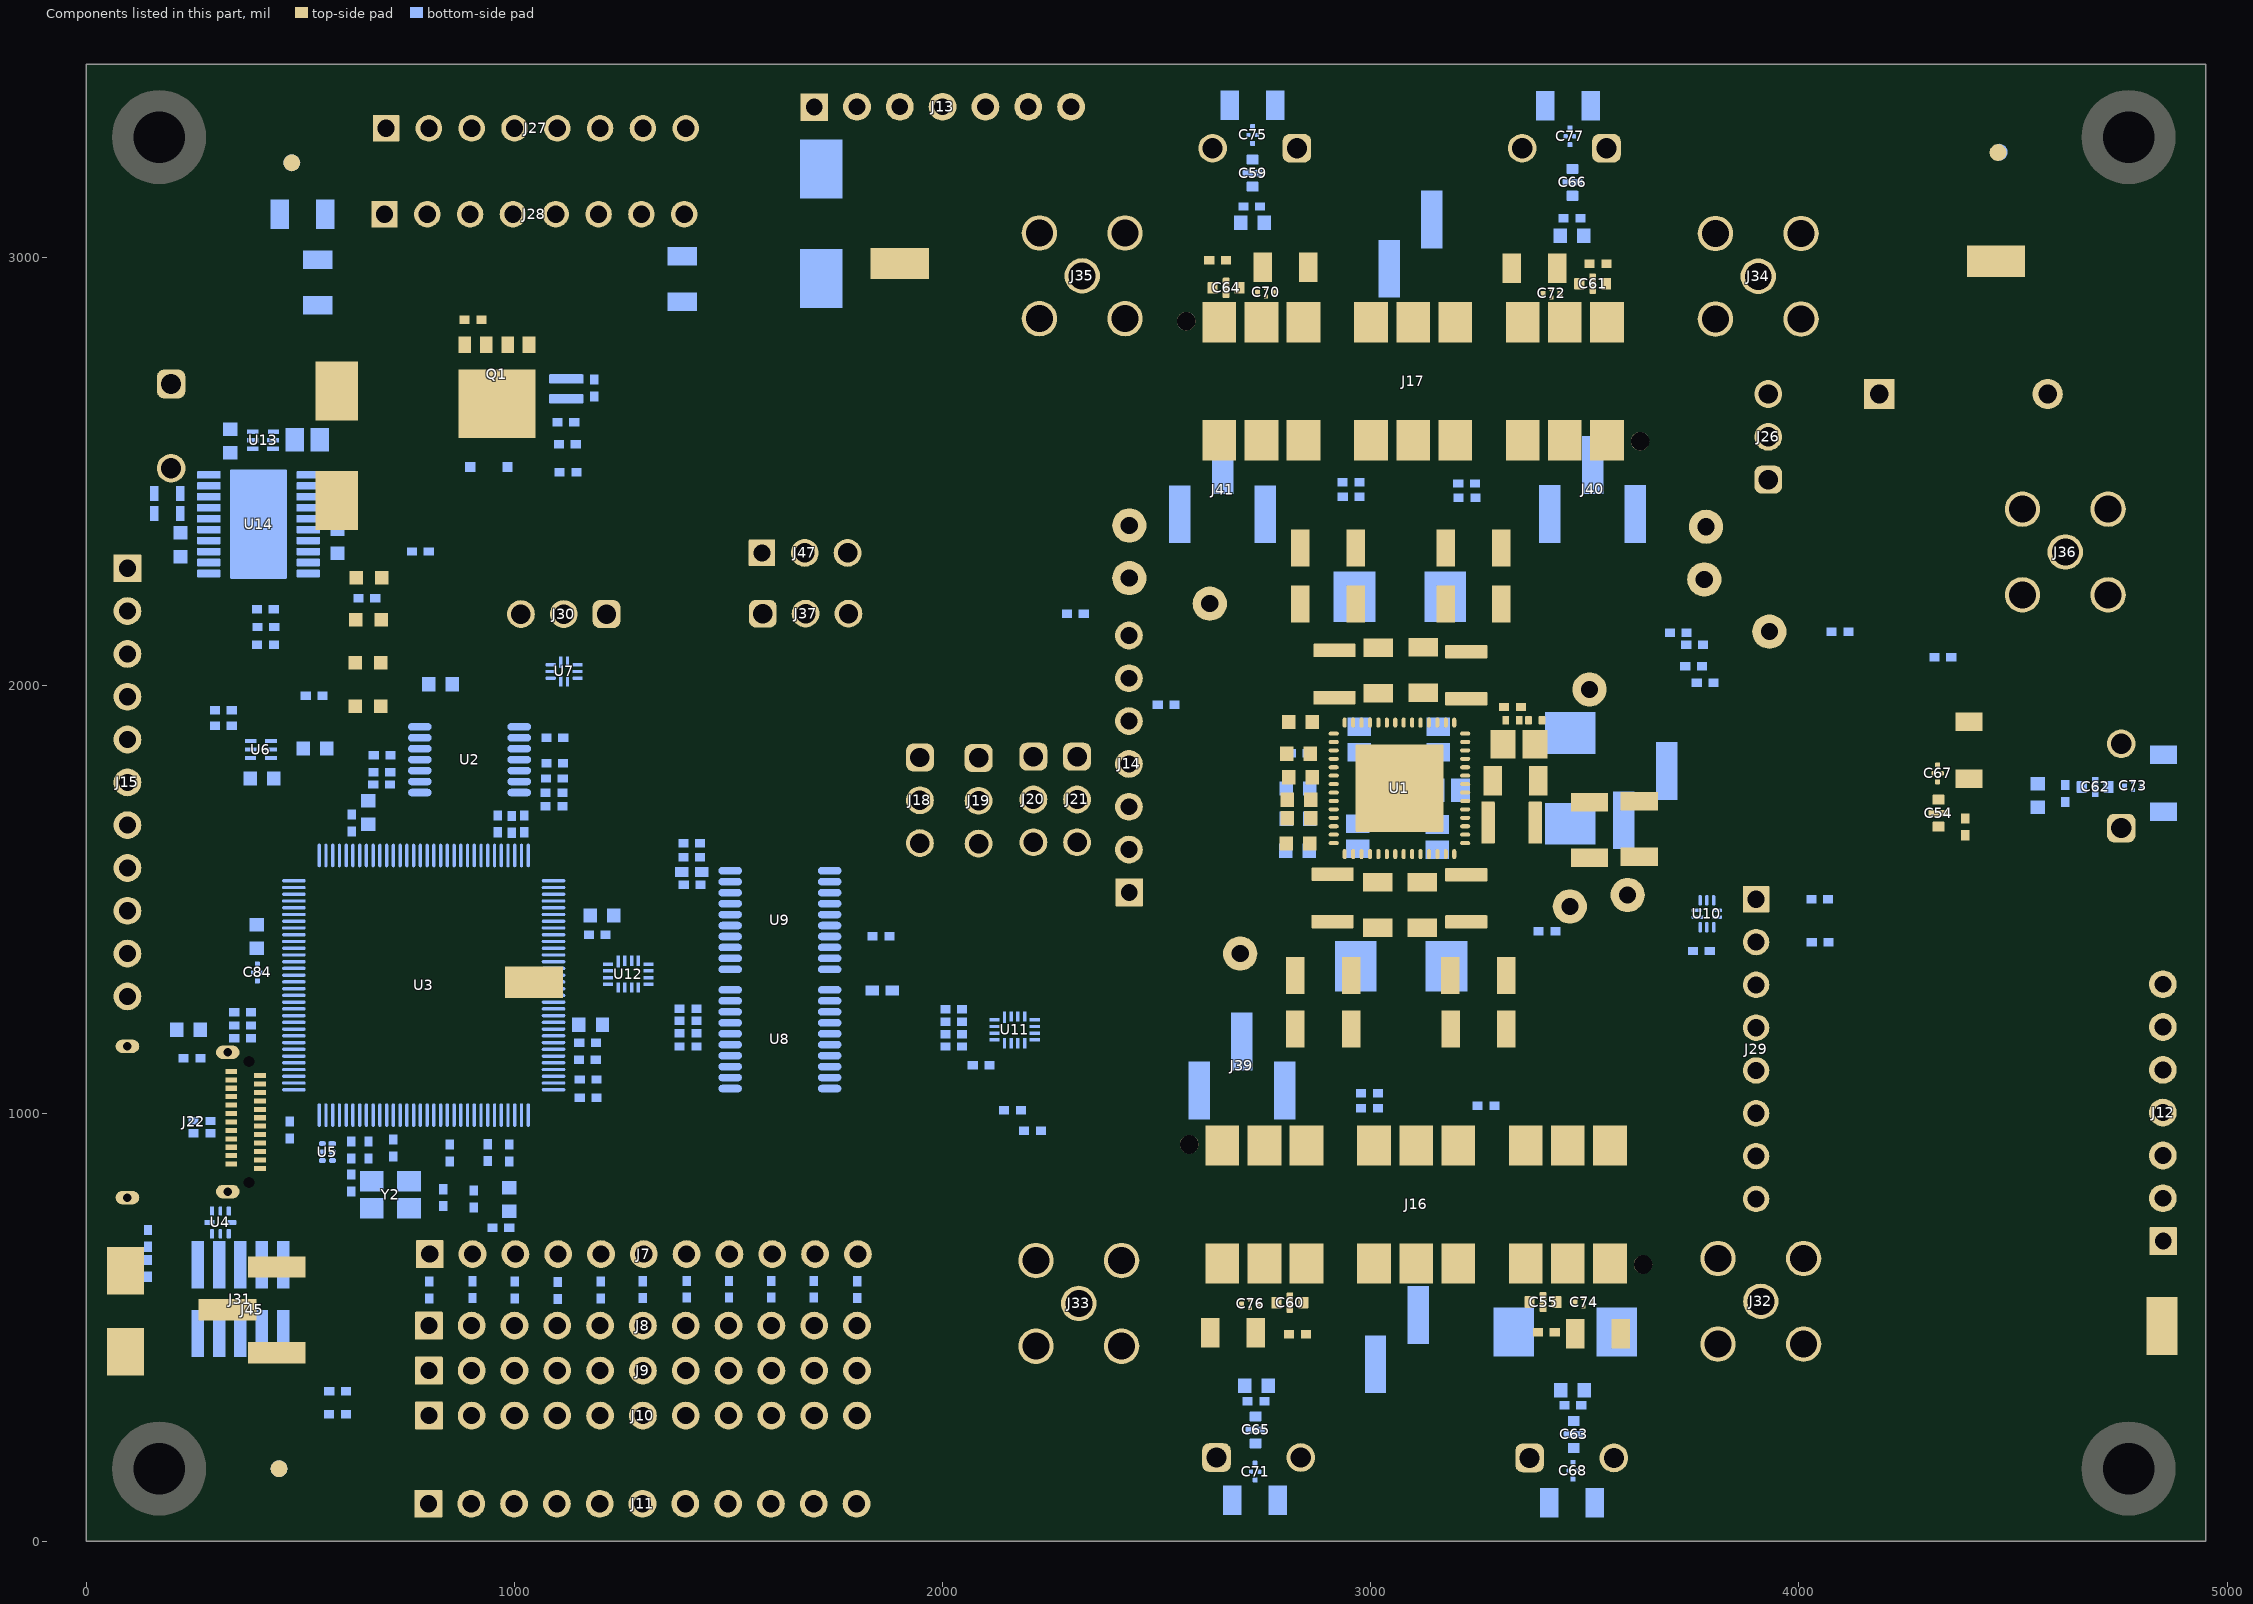
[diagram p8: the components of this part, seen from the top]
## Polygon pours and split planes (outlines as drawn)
GND on Top Layer "GND_L01_P789" (solid, remove dead copper, pour order 789): 10,3440 4940,3440 4940,10 10,10
no net on Top Layer "NONET_L01_P767" (solid, remove dead copper, pour order 767): 10,3720
no net on Top Layer "NONET_L01_P598" (solid, remove dead copper, pour order 598): 2841.83,471.19 2841.83,515.59 2823.07,534.35 2823.07,577.65 2818.5,582.22 2800.23,582.22 2800.23,546.23 2786,532 2726.93,532 2726.93,570.34 2722.89,574.38 2714.28,574.38 2678.93,539.03 2678.93,452.76 2695.69,436 2806.64,436
no net on Top Layer "NONET_L01_P589" (solid, remove dead copper, pour order 589): 4409.81,1671.87 4365.41,1671.87 4346.65,1690.63 4303.35,1690.63 4298.78,1695.2 4298.78,1713.47 4337.47,1713.47 4352,1728 4349,1731 4349,1784 4315.12,1784 4304,1795.12 4304,1805.5 4341.35,1805.5 4342.36,1806.52 4434.48,1806.52 4445,1796 4445,1707.06
VCCA on Top Layer "VCCA_L01_P749" (solid, remove dead copper, pour order 749): 2937,1880 2937,1941 2944,1948 2944.23,1947.77 2986.47,1947.77 2993,1941.24 2993,1880.79 2987,1874.79 2986.79,1875 2941,1875 2941,1876
VCCA on Top Layer "VCCA_L01_P747" (solid, remove dead copper, pour order 747): 2942,1643 2986,1643 2990,1639 2990,1571 2982.92,1563.92 2948.5,1563.92 2940,1572.42 2940,1642.4 2941.4,1642.4
VCCA on Top Layer "VCCA_L01_P745" (solid, remove dead copper, pour order 745): 3184,1767 3187.6,1770.6 3250.34,1770.6 3257.94,1763 3257.94,1733.94 3253,1729 3177.36,1729 3174,1732.36 3174,1768 3177,1771 3177.19,1770.81 3188,1770.81
no net on Top Layer "NONET_L01_P743" (solid, remove dead copper, pour order 743): 3143,1639
no net on Top Layer "NONET_L01_P741" (solid, remove dead copper, pour order 741): 3143,1639
no net on Top Layer "NONET_L01_P739" (solid, remove dead copper, pour order 739): 3143,1639
VCCA on Top Layer "VCCA_L01_P737" (solid, remove dead copper, pour order 737): 3179,1642.4 3179,1579.34 3170.66,1571 3138,1571 3137,1572 3137,1640.9 3138.5,1642.4
no net on Top Layer "NONET_L01_P715" (solid, remove dead copper, pour order 715): 3090,3430
no net on Top Layer "NONET_L01_P713" (solid, remove dead copper, pour order 713): 3080,3430
SW_B4 on Top Layer "SW_B4_L01_P705" (solid, remove dead copper, pour order 705): 2963,1983.81 2959.81,1987 2866.29,1987 2863.29,1984 2863.56,1983.73 2863.56,1954 2916.56,1901 2959,1901 2963,1905
SW_B2 on Top Layer "SW_B2_L01_P703" (solid, remove dead copper, pour order 703): 2961,1613.94 2960.81,1532.46 2957,1529 2865,1529.05 2862.12,1532 2863.11,1532.99 2863.11,1574.59 2902.46,1613.94
SW_B1 on Top Layer "SW_B1_L01_P701" (solid, remove dead copper, pour order 701): 3231,1615 3274,1572 3274,1533 3273.42,1533 3266.42,1526 3175.04,1526 3175.04,1527.69 3171,1531.73 3171,1610.96 3175.04,1615
SW_B3 on Top Layer "SW_B3_L01_P699" (solid, remove dead copper, pour order 699): 3172.95,1980.85 3172.95,1900 3222.27,1900 3273,1950.73 3273,1980.85
VOUT_B3 on Top Layer "VOUT_B3_L01_P691" (solid, remove dead copper, pour order 691): 3067,3439 3067,2034.54 3712,2034.54 3710,2036.54 3710,3439
no net on Top Layer "NONET_L01_P594" (solid, remove dead copper, pour order 594): 2651.63,3025.28 2807.68,3023.19 2807.68,2939.59 2649.97,2940.35 2649.97,3023.62
VCCA on Top Layer "VCCA_L01_P623" (solid, remove dead copper, pour order 623): 646,3180 1700,3180 1730,3150 1730,2926.87 1744.03,2912.84 2037.14,2912.84 2260.56,2689.43 2260.56,1591.61 2213.95,1545 1820,1545 603.51,2761.49 603.51,3131.51 646,3174
no net on Top Layer "NONET_L01_P591" (solid, remove dead copper, pour order 591): 617,3174
VSYS on Top Layer "VSYS_L01_P617" (solid, remove dead copper, pour order 617): 173,2940 770,2940 840,2870 840,2773 873,2740 1048.79,2740 1068.25,2720.54 1068.25,2555.25 1053,2540 747.63,2540 747.63,2541.3 720,2568.93 720,2606 672.76,2640 167,2640 167,2643 150,2660 150,2917
no net on Top Layer "NONET_L01_P597" (solid, remove dead copper, pour order 597): 2484.6,1645 2785.37,1645 2795.44,1634.93 2795.44,1608.92 2481.08,1608.92 2480,1610 2480,1641 2480.6,1641
no net on Top Layer "NONET_L01_P592" (solid, remove dead copper, pour order 592): 2867.43,1955.34
VOUT_B5 on Top Layer "VOUT_B5_L01_P618" (solid, remove dead copper, pour order 618): 3322.58,2028 4940,2028 4940,1474 3322.58,1474
VOUT_B4 on Top Layer "VOUT_B4_L01_P619" (solid, remove dead copper, pour order 619): 3076,2045.57 2415.45,2045.57 2415.45,3440 3076,3440
VOUT_B2 on Top Layer "VOUT_B2_L01_P620" (solid, remove dead copper, pour order 620): 3076,15 2414.74,15 2414.74,1465 3076,1465
VOUT_B1 on Top Layer "VOUT_B1_L01_P622" (solid, remove dead copper, pour order 622): 3079.83,1464.03 3752,1464.03 3752,15 3079.83,15
SW_B5 on Top Layer "SW_B5_L01_P596" (solid, remove dead copper, pour order 596): 3207,1734 3291.52,1734 3318.07,1707.45 3318.07,1649.55 3297.52,1629 3242,1629 3239.67,1631.33 3239.67,1714.33 3233,1721 3212,1721 3207,1726
no net on Top Layer "NONET_L01_P593" (solid, remove dead copper, pour order 593): 3925,4730
no net on Top Layer "NONET_L01_P590" (solid, remove dead copper, pour order 590): 3291,1598
no net on Top Layer "NONET_L01_P611" (solid, remove dead copper, pour order 611): 2937.2,2620 2955.2,2638 3239,2638 3255,2622 3255,2524 3237,2506 2956,2506 2937.2,2526
no net on Top Layer "NONET_L01_P615" (solid, remove dead copper, pour order 615): 2937.2,2895 2955.2,2913 3239,2913 3255,2897 3255,2799 3237,2781 2956,2781 2936,2801
no net on Top Layer "NONET_L01_P613" (solid, remove dead copper, pour order 613): 2944.2,973 2962.2,991 3246,991 3262,975 3262,877 3244,859 2963,859 2943,879
no net on Top Layer "NONET_L01_P603" (solid, remove dead copper, pour order 603): 2800,1418.29 2784.71,1403 2784.71,1197 2801,1180.71 2845,1180.71 2860.29,1196 2860.29,1402 2844,1418.29
no net on Top Layer "NONET_L01_P604" (solid, remove dead copper, pour order 604): 3293,1417.29 3277.71,1402 3277.71,1196 3294,1179.71 3338,1179.71 3353.29,1195 3353.29,1401 3337,1417.29
no net on Top Layer "NONET_L01_P605" (solid, remove dead copper, pour order 605): 3283.96,2343.5 3268.67,2328.2 3268.67,2122.2 3284.96,2105.91 3328.96,2105.91 3344.25,2121.2 3344.25,2327.2 3327.96,2343.5
no net on Top Layer "NONET_L01_P601" (solid, remove dead copper, pour order 601): 2810.04,2343.29 2794.75,2328 2794.75,2122 2811.04,2105.71 2855.04,2105.71 2869.78,2120.45 2869.78,2327.55 2854.04,2343.29
no net on Top Layer "NONET_L01_P599" (solid, remove dead copper, pour order 599): 3369.87,474.19 3369.87,518.59 3388.63,537.35 3388.63,580.65 3393.2,585.22 3411.47,585.22 3411.47,548.53 3425,535 3489,535 3489,575.88 3493.12,580 3500.46,580 3515,565.46 3515,449.93 3504.07,439 3405.06,439
no net on Top Layer "NONET_L01_P600" (solid, remove dead copper, pour order 600): 3545.71,3008.81 3545.71,2964.41 3526.95,2945.65 3526.95,2902.35 3522.38,2897.78 3504.11,2897.78 3504.11,2936.47 3475.06,2936.47 3433.58,2936.47 3433.58,2914.12 3422.47,2903 3412.08,2903 3412.08,2940.35 3411.06,2941.36 3411.06,3033.48 3421.58,3044 3510.52,3044
GND on Signal Layer 2 "GND_L04_P791" (solid, remove dead copper, pour order 791): 10,3440 4940,3440 4940,10 10,10
no net on Signal Layer 2 "NONET_L04_P729" (solid, remove dead copper, pour order 729): 20,3430
no net on Signal Layer 2 "NONET_L04_P637" (solid, remove dead copper, pour order 637): 30,3110
no net on Signal Layer 2 "NONET_L04_P636" (solid, remove dead copper, pour order 636): 2868,2323
GND on Bottom Layer "GND_L06_P793" (solid, remove dead copper, pour order 793): 4940,3440 10,3440 10,10 4940,10
VOUT_B5 on Bottom Layer "VOUT_B5_L06_P785" (solid, remove dead copper, pour order 785): 3719.97,2099.1 4937.09,2099.1 4939,2097.19 4938.59,2096.78 4938.59,1458.13 3721.29,1458.13 3719.11,1460.31 3719.97,1461.17
no net on Bottom Layer "NONET_L06_P783" (solid, remove dead copper, pour order 783): 4939,2097.19
MCUVCC on Bottom Layer "MCUVCC_L06_P781" (solid, remove dead copper, pour order 781): 268.36,2201.12 248.36,2181.12 248.36,473.12 268.36,453.12 758.36,453.12 758.36,505.65 1424.05,1171.33 1424.05,2179.53 1402.45,2201.12 1401.65,2200.32 268.36,2200.32
GND on Bottom Layer "GND_L06_P775" (solid, remove dead copper, pour order 775): 4480,2095.98 4482.21,2098.19 4940,2098.19 4939,2097.19 4939,1741.63 4924.99,1755.64 4480,1755.64
VOUT_B1 on Bottom Layer "VOUT_B1_L06_P669" (solid, remove dead copper, pour order 669): 3405.96,1726.52 3737.85,1726.52 3737.85,537.27 3405.97,537.27
VOUT_B3 on Bottom Layer "VOUT_B3_L06_P665" (solid, remove dead copper, pour order 665): 3409.7,2162.38 3733.15,2162.38 3733.15,1739.19 3726.12,1732.15 3409.7,1732.15
VCCA on Bottom Layer "VCCA_L06_P677" (solid, remove dead copper, pour order 677): 2409.96,3175 3434.16,2150.8 3434.16,1384.75 1506.25,1384.75 638.39,2252.61 638.39,3167.39 646,3175
no net on Bottom Layer "NONET_L06_P662" (solid, remove dead copper, pour order 662): 2945.85,1872.71 3185.53,1872.71 3188.25,1870 3188.25,1651.9 2944,1651.9 2945.85,1653.75
VOUT_B4 on Bottom Layer "VOUT_B4_L06_P674" (solid, remove dead copper, pour order 674): 2503.17,2138.17 2503.17,3060 2723.78,3060 2725,3061.22 2725,3440 3079,3440 3080.73,3438.27 3080.73,2138.17 2505.83,2138.17 2505.05,2137.39
VOUT_B3 on Bottom Layer "VOUT_B3_L06_P664" (solid, remove dead copper, pour order 664): 3750.8,3030 3750.99,3440 3466.54,3440 3466.54,3029.55 3469.5,3026.58 3472.93,3030
VSYS on Bottom Layer "VSYS_L06_P668" (solid, remove dead copper, pour order 668): 1060,2910 1080,2890 1080,2551.34 1062.66,2534 756.76,2534 736.76,2554 736.76,2614.08 735.92,2614.08 720,2630 160,2630 140,2650 140,2883 167,2910
no net on Bottom Layer "NONET_L06_P658" (solid, remove dead copper, pour order 658): 3293,1360 3338,1360 3338,1195 3337,1196 3293,1196
no net on Bottom Layer "NONET_L06_P659" (solid, remove dead copper, pour order 659): 2800,1403 2844.86,1403 2844.86,1196.14 2844,1197 2800,1197
no net on Bottom Layer "NONET_L06_P651" (solid, remove dead copper, pour order 651): 3714,3433
VOUT_B1 on Bottom Layer "VOUT_B1_L06_P670" (solid, remove dead copper, pour order 670): 3427.81,1402 3426.81,1403 3080,1403 3080,12.16 3474,12.16 3475,13.16 3475,1401 3474,1402
no net on Bottom Layer "NONET_L06_P667" (solid, remove dead copper, pour order 667): 2740.01,540 3080,540 3079,539 3079,20 2732.65,20 2731,21.65 2705.44,21.65 2705.44,535.6 2709.35,539.5
VOUT_B2 on Bottom Layer "VOUT_B2_L06_P671" (solid, remove dead copper, pour order 671): 3054.54,1404.8 2541.08,1404.8 2538.35,1402.07 2538.35,12.16 2731,12.16 2731,430 3054.54,430
no net on Bottom Layer "NONET_L06_P666" (solid, remove dead copper, pour order 666): 3689,537 3689,29 3680,20 3407.24,20 3407.24,531.71 3412.54,537
no net on Bottom Layer "NONET_L06_P649" (solid, remove dead copper, pour order 649): 40,1709
no net on Bottom Layer "NONET_L06_P646" (solid, remove dead copper, pour order 646): 20,1700
no net on Bottom Layer "NONET_L06_P643" (solid, remove dead copper, pour order 643): 20,1735
no net on Bottom Layer "NONET_L06_P650" (solid, remove dead copper, pour order 650): 3392.41,2107
VSYS on Bottom Layer "VSYS_L06_P660" (solid, remove dead copper, pour order 660): 1071,2735 1071,2558 1072,2557 1069,2554 856,2554 851,2559 851,2731.07 854.93,2735
no net on Bottom Layer "NONET_L06_P647" (solid, remove dead copper, pour order 647): 151,2680
VOUT_B3 on Bottom Layer "VOUT_B3_L06_P672" (solid, remove dead copper, pour order 672): 3092.1,2141.07 3753.31,2141.02 3753.31,3030 3092.77,3030
no net on Bottom Layer "NONET_L06_P648" (solid, remove dead copper, pour order 648): 163.69,3011.91
no net on Bottom Layer "NONET_L06_P642" (solid, remove dead copper, pour order 642): 220,360
no net on Bottom Layer "NONET_L06_P641" (solid, remove dead copper, pour order 641): 3347,1662
no net on Bottom Layer "NONET_L06_P652" (solid, remove dead copper, pour order 652): 2927,1989
no net on Bottom Layer "NONET_L06_P663" (solid, remove dead copper, pour order 663): 4939,2029 4939,1760 4930.58,1751.57 4574.42,1751.57 4542,1784 4542,2029
no net on Bottom Layer "NONET_L06_P645" (solid, remove dead copper, pour order 645): 2482.5,1750.63
no net on Bottom Layer "NONET_L06_P644" (solid, remove dead copper, pour order 644): 325,2250
no net on Bottom Layer "NONET_L06_P656" (solid, remove dead copper, pour order 656): 190,2327
no net on Bottom Layer "NONET_L06_P655" (solid, remove dead copper, pour order 655): 20,3420
VOUT_B1 on Bottom Layer "VOUT_B1_L06_P661" (solid, remove dead copper, pour order 661): 3388.69,1560.53 3389.21,1560 3647.22,1560 3647.22,1407.09 3626.83,1386.71 3388.69,1386.71
no net on Bottom Layer "NONET_L06_P657" (solid, remove dead copper, pour order 657): 3675,1678.16
no net on Bottom Layer "NONET_L06_P654" (solid, remove dead copper, pour order 654): 2540,3400
no net on Bottom Layer "NONET_L06_P653" (solid, remove dead copper, pour order 653): 20,3440
GND on Signal Layer 1 "GND_L03_P795" (solid, remove dead copper, pour order 795): 4937,3439 6,3439 6,14 10,10 4940,10 4940,3440
no net on Signal Layer 1 "NONET_L03_P625" (solid, remove dead copper, pour order 625): 2212,1560
VCCA on Signal Layer 1 "VCCA_L03_P634" (solid, remove dead copper, pour order 634): 3282.99,1952.47 3311,1924.46 3311,1588 3283,1560 2198,1560 2173,1585 2170,1585 2170,1932.47 2190,1952.47
VCCA on Signal Layer 1 "VCCA_L03_P627" (solid, remove dead copper, pour order 627): 3179,1735 3179,1769.1 3182.9,1773 3231,1773 3248.24,1755.76 3248.24,1739.24 3238.93,1729.93 3184.07,1729.93
VCCA on Signal Layer 1 "VCCA_L03_P632" (solid, remove dead copper, pour order 632): 3159.02,1624 3159.02,1589.94 2984,1589.94 2984,1624
VCCA on Signal Layer 1 "VCCA_L03_P633" (solid, remove dead copper, pour order 633): 3152.02,1934 3152.02,1894.41 2977,1894.41 2977,1930 2981,1934
no net on Signal Layer 1 "NONET_L03_P626" (solid, remove dead copper, pour order 626): 2993,1932
VCCA on Signal Layer 1 "VCCA_L03_P629" (solid, remove dead copper, pour order 629): 2944,1948 2998,1948 3001,1945 3001,1871 2995,1865 2946,1865 2939,1872 2939,1943
VCCA on Signal Layer 1 "VCCA_L03_P631" (solid, remove dead copper, pour order 631): 3135,1952.47 3189,1952.47 3192,1949.47 3192,1875.47 3186,1869.47 3137,1869.47 3130,1876.47 3130,1947.47
VCCA on Signal Layer 1 "VCCA_L03_P630" (solid, remove dead copper, pour order 630): 3135,1655 3189,1655 3192,1652 3192,1578 3186,1572 3137,1572 3130,1579 3130,1650
VCCA on Signal Layer 1 "VCCA_L03_P628" (solid, remove dead copper, pour order 628): 2936,1651 2990,1651 2993,1648 2993,1574 2987,1568 2938,1568 2931,1575 2931,1646
GND on GND Layer 1 "GND_L02_P757" (solid, remove dead copper, pour order 757): 10,3430 4930,3430 4930,20 10,20
GND on GND Layer 2 "GND_L05_P761" (solid, remove dead copper, pour order 761): 18.41,3430.11 4928.41,3430.11 4928.41,20.11 18.41,20.11

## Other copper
Top Layer:
  pour cut-out: 2175.2,2856.3 ccw(c2225.2,2856.3) 2225.2,2806.3 ccw(c2225.2,2856.3) 2275.2,2856.3 ccw(c2225.2,2856.3) 2225.2,2906.3 ccw(c2225.2,2856.3)
  pour cut-out: 2375.2,2856.3 ccw(c2425.2,2856.3) 2425.2,2806.3 ccw(c2425.2,2856.3) 2475.2,2856.3 ccw(c2425.2,2856.3) 2425.2,2906.3 ccw(c2425.2,2856.3)
  pour cut-out: 2375.2,3056.3 ccw(c2425.2,3056.3) 2425.2,3006.3 ccw(c2425.2,3056.3) 2475.2,3056.3 ccw(c2425.2,3056.3) 2425.2,3106.3 ccw(c2425.2,3056.3)
  pour cut-out: 2175.2,3056.3 ccw(c2225.2,3056.3) 2225.2,3006.3 ccw(c2225.2,3056.3) 2275.2,3056.3 ccw(c2225.2,3056.3) 2225.2,3106.3 ccw(c2225.2,3056.3)
  pour cut-out: 3754.2,2855.3 ccw(c3804.2,2855.3) 3804.2,2805.3 ccw(c3804.2,2855.3) 3854.2,2855.3 ccw(c3804.2,2855.3) 3804.2,2905.3 ccw(c3804.2,2855.3)
  pour cut-out: 3954.2,2855.3 ccw(c4004.2,2855.3) 4004.2,2805.3 ccw(c4004.2,2855.3) 4054.2,2855.3 ccw(c4004.2,2855.3) 4004.2,2905.3 ccw(c4004.2,2855.3)
  pour cut-out: 3954.2,3055.3 ccw(c4004.2,3055.3) 4004.2,3005.3 ccw(c4004.2,3055.3) 4054.2,3055.3 ccw(c4004.2,3055.3) 4004.2,3105.3 ccw(c4004.2,3055.3)
  pour cut-out: 3754.2,3055.3 ccw(c3804.2,3055.3) 3804.2,3005.3 ccw(c3804.2,3055.3) 3854.2,3055.3 ccw(c3804.2,3055.3) 3804.2,3105.3 ccw(c3804.2,3055.3)
  pour cut-out: 4472.2,2209.3 ccw(c4522.2,2209.3) 4522.2,2159.3 ccw(c4522.2,2209.3) 4572.2,2209.3 ccw(c4522.2,2209.3) 4522.2,2259.3 ccw(c4522.2,2209.3)
  pour cut-out: 4672.2,2209.3 ccw(c4722.2,2209.3) 4722.2,2159.3 ccw(c4722.2,2209.3) 4772.2,2209.3 ccw(c4722.2,2209.3) 4722.2,2259.3 ccw(c4722.2,2209.3)
  pour cut-out: 4672.2,2409.3 ccw(c4722.2,2409.3) 4722.2,2359.3 ccw(c4722.2,2409.3) 4772.2,2409.3 ccw(c4722.2,2409.3) 4722.2,2459.3 ccw(c4722.2,2409.3)
  pour cut-out: 4472.2,2409.3 ccw(c4522.2,2409.3) 4522.2,2359.3 ccw(c4522.2,2409.3) 4572.2,2409.3 ccw(c4522.2,2409.3) 4522.2,2459.3 ccw(c4522.2,2409.3)
  pour cut-out: 2167.2,456.3 ccw(c2217.2,456.3) 2217.2,406.3 ccw(c2217.2,456.3) 2267.2,456.3 ccw(c2217.2,456.3) 2217.2,506.3 ccw(c2217.2,456.3)
  pour cut-out: 2367.2,456.3 ccw(c2417.2,456.3) 2417.2,406.3 ccw(c2417.2,456.3) 2467.2,456.3 ccw(c2417.2,456.3) 2417.2,506.3 ccw(c2417.2,456.3)
  pour cut-out: 2367.2,656.3 ccw(c2417.2,656.3) 2417.2,606.3 ccw(c2417.2,656.3) 2467.2,656.3 ccw(c2417.2,656.3) 2417.2,706.3 ccw(c2417.2,656.3)
  pour cut-out: 2167.2,656.3 ccw(c2217.2,656.3) 2217.2,606.3 ccw(c2217.2,656.3) 2267.2,656.3 ccw(c2217.2,656.3) 2217.2,706.3 ccw(c2217.2,656.3)
  pour cut-out: 3761.2,659.91 ccw(c3811.2,659.91) 3811.2,609.91 ccw(c3811.2,659.91) 3861.2,659.91 ccw(c3811.2,659.91) 3811.2,709.91 ccw(c3811.2,659.91)
  pour cut-out: 3961.2,659.91 ccw(c4011.2,659.91) 4011.2,609.91 ccw(c4011.2,659.91) 4061.2,659.91 ccw(c4011.2,659.91) 4011.2,709.91 ccw(c4011.2,659.91)
  pour cut-out: 3961.2,459.91 ccw(c4011.2,459.91) 4011.2,409.91 ccw(c4011.2,459.91) 4061.2,459.91 ccw(c4011.2,459.91) 4011.2,509.91 ccw(c4011.2,459.91)
  pour cut-out: 3761.2,459.91 ccw(c3811.2,459.91) 3811.2,409.91 ccw(c3811.2,459.91) 3861.2,459.91 ccw(c3811.2,459.91) 3811.2,509.91 ccw(c3811.2,459.91)
  pour cut-out: 3056.83,1022 3063.64,1012.15 3062.81,1004.74 3058,998 3044.29,998 3038.29,1004 3038.29,1016.24 3044.05,1022
  pour cut-out: 3318.65,1029.85 3324.2,1021.81 3324.2,1011.85 3318.89,1005.85 3304.65,1005.85 3298.65,1011.85 3298.65,1024.09 3304.41,1029.85
  pour cut-out: 3253.24,2505 3258.83,2496.9 3257.81,2487.74 3253,2481 3239.29,2481 3233.29,2487 3233.29,2499.24 3239.05,2505
  pour cut-out: 3233,2496.24
  pour cut-out: 4880.02,1267.81
  pour cut-out: 2921,2509.91 2947,2509.91 2947,2485.91 2921,2485.91
  region: 2801,2050.6
  pour cut-out: 2898.29,1784.71 2904.46,1778.54 2945.45,1778.54 2950.63,1783.71 2950.63,1819.74 2946.42,1823.95 2907.95,1823.95 2898.29,1814.29
  pour cut-out: 2267.26,3320.55
  text ".Layer_Name" at 576,-862 h60
Signal Layer 1:
  text ".Layer_Name" at 569,-858 h60
Signal Layer 2:
  text ".Layer_Name" at 576,-863 h60
GND Layer 1:
  pour cut-out: 3389,565 3395,571 3407.88,571 3413,565.88 3413,554 3406,547 3396,547 3389,554
  pour cut-out: 2901,2445 2908,2452 2921.25,2452 2927,2446.25 2927,2435 2919,2427 2909,2427 2901,2435
  text ".Layer_Name" at 574,-858 h60
GND Layer 2:
  pour cut-out: 3330.98,1933
  text ".Layer_Name" at 576,-862 h60
Bottom Layer:
  rectangle net VOUT_B3: 3407,1745.54 3527,1839.39
  rectangle net VOUT_B4: 2999.69,2142 3045.93,2267
  rectangle net VOUT_B2: 2994.37,1284 3055.91,1404
  rectangle net VOUT_B1: 3080.04,1283 3153,1404
  pour cut-out: 2175.2,2856.3 ccw(c2225.2,2856.3) 2225.2,2806.3 ccw(c2225.2,2856.3) 2275.2,2856.3 ccw(c2225.2,2856.3) 2225.2,2906.3 ccw(c2225.2,2856.3)
  pour cut-out: 2375.2,2856.3 ccw(c2425.2,2856.3) 2425.2,2806.3 ccw(c2425.2,2856.3) 2475.2,2856.3 ccw(c2425.2,2856.3) 2425.2,2906.3 ccw(c2425.2,2856.3)
  pour cut-out: 2375.2,3056.3 ccw(c2425.2,3056.3) 2425.2,3006.3 ccw(c2425.2,3056.3) 2475.2,3056.3 ccw(c2425.2,3056.3) 2425.2,3106.3 ccw(c2425.2,3056.3)
  pour cut-out: 2175.2,3056.3 ccw(c2225.2,3056.3) 2225.2,3006.3 ccw(c2225.2,3056.3) 2275.2,3056.3 ccw(c2225.2,3056.3) 2225.2,3106.3 ccw(c2225.2,3056.3)
  pour cut-out: 3754.2,2855.3 ccw(c3804.2,2855.3) 3804.2,2805.3 ccw(c3804.2,2855.3) 3854.2,2855.3 ccw(c3804.2,2855.3) 3804.2,2905.3 ccw(c3804.2,2855.3)
  pour cut-out: 3954.2,2855.3 ccw(c4004.2,2855.3) 4004.2,2805.3 ccw(c4004.2,2855.3) 4054.2,2855.3 ccw(c4004.2,2855.3) 4004.2,2905.3 ccw(c4004.2,2855.3)
  pour cut-out: 3954.2,3055.3 ccw(c4004.2,3055.3) 4004.2,3005.3 ccw(c4004.2,3055.3) 4054.2,3055.3 ccw(c4004.2,3055.3) 4004.2,3105.3 ccw(c4004.2,3055.3)
  pour cut-out: 3754.2,3055.3 ccw(c3804.2,3055.3) 3804.2,3005.3 ccw(c3804.2,3055.3) 3854.2,3055.3 ccw(c3804.2,3055.3) 3804.2,3105.3 ccw(c3804.2,3055.3)
  pour cut-out: 2167.2,456.3 ccw(c2217.2,456.3) 2217.2,406.3 ccw(c2217.2,456.3) 2267.2,456.3 ccw(c2217.2,456.3) 2217.2,506.3 ccw(c2217.2,456.3)
  pour cut-out: 2367.2,456.3 ccw(c2417.2,456.3) 2417.2,406.3 ccw(c2417.2,456.3) 2467.2,456.3 ccw(c2417.2,456.3) 2417.2,506.3 ccw(c2417.2,456.3)
  pour cut-out: 2367.2,656.3 ccw(c2417.2,656.3) 2417.2,606.3 ccw(c2417.2,656.3) 2467.2,656.3 ccw(c2417.2,656.3) 2417.2,706.3 ccw(c2417.2,656.3)
  pour cut-out: 2167.2,656.3 ccw(c2217.2,656.3) 2217.2,606.3 ccw(c2217.2,656.3) 2267.2,656.3 ccw(c2217.2,656.3) 2217.2,706.3 ccw(c2217.2,656.3)
  pour cut-out: 3761.64,660.53 ccw(c3811.64,660.53) 3811.64,610.53 ccw(c3811.64,660.53) 3861.64,660.53 ccw(c3811.64,660.53) 3811.64,710.53 ccw(c3811.64,660.53)
  pour cut-out: 3960,659.88 ccw(c4010,659.88) 4010,609.88 ccw(c4010,659.88) 4060,659.88 ccw(c4010,659.88) 4010,709.88 ccw(c4010,659.88)
  pour cut-out: 3961.96,459.64 ccw(c4011.96,459.64) 4011.96,409.64 ccw(c4011.96,459.64) 4061.96,459.64 ccw(c4011.96,459.64) 4011.96,509.64 ccw(c4011.96,459.64)
  pour cut-out: 3761.64,461.52 ccw(c3811.64,461.52) 3811.64,411.52 ccw(c3811.64,461.52) 3861.64,461.52 ccw(c3811.64,461.52) 3811.64,511.52 ccw(c3811.64,461.52)
  pour cut-out: 3224,2452
  pour cut-out: 3274.31,1037.86 3325.69,1037.86 3325.69,999.86 3274.31,999.86
  pour cut-out: 3002.62,1062.28 3067.58,1062.28 3067.58,993.76 3002.62,993.76
  pour cut-out: 3224,2452.84 3224,2506.76 3262,2506.76 3262,2452.84
  pour cut-out: 2952,2509 2952,2458.24 2914,2458.24 2914,2509
  pour cut-out: 4360.91,50 4360.91,149.41 3849.09,149.41 3849.09,50
  pour cut-out: 2921.77,1788.15 2928.92,1781 2942,1781 2950.4,1789.4 2950.4,1804 2945.4,1809 2926.77,1809 2921.77,1804
  text "©" at 3860,65 h105
  text "2019" at 3949,65 h60
  text "TI" at 4225,65 h60
  text ".Layer_Name" at 576,-859 h60

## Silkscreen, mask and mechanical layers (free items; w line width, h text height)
Top Overlay:
  lines w4: 2782,1406 3418.74,1407.53 ; 3419.73,1408.52 3419.73,2116.24
  lines w5: 1188.76,1610 1863.39,1610 ; 1189.76,1708 1862.92,1708 ; 1189.76,1798 1864.39,1798 ; 1247.01,1523 1248.01,1851 ; 1524.28,1852 1526.28,1524 ; 1864.39,1585 1864.39,1587 ; 1917,1057 2536,1057 ; 1917,1117 2536,1117 ; 1917,1177 2536,1177 ; 1917,1237 2537,1237 ; 1917,1297 2537,1297 ; 1917,1357 2537,1357 ; 2067,997 2067,1412 ; 2217,997 2217,1411 ; 2370.17,1412 2372,997 ; 2536,997 1917,997 1917,1412 2537,1412 2537,998 ; 2537,1144 2537,1146 ; 2782,1406 2782,2074.48 2808.45,2100.92 2821.83,2113.56 3419.73,2116.24 ; 3561,1781 3561,1781.2 ; 1187.76,1524 1187.76,1853 1864.39,1853 1862.99,1524 1187.76,1524
  lines w6: 3420,2070 3700,2070
  lines w9: 940,740 940,960 ; 1240,740 1240,1080 ; 1440,736 1440,1080 ; 1640,736 1640,1060 ; 1840,736 1840,1100
  lines w10: 787.33,747.25 cw(c845,735) 902.97,745.73
  lines w11: 383,2876 498,2876 ; 443,2822.26 443,2930 443,2911 ; 697.31,3145 717.31,3165 1377.31,3165 1397.88,3144.43 ; 704.62,3346 719.62,3361 1379.19,3361 1395.19,3345 ; 2316,2116 2381.79,2116 ; 2416,214 2496.78,214 ; 2419,3251 2477.5,3251 ; 2456,167 2456,257 ; 2965,200.88 3040,200.88 ; 2971,3248 3058.07,3248 ; 3013,3205 3013,3290 ; 3145,206.94 3226.06,206.94 ; 3158,3250 3226.07,3250 ; 3187.3,165 3187.3,250 ; 3685,3249 3774,3248 ; 3690,206.94 3781.06,206.94 ; 3731,3204 3731,3286 ; 4685,1490 4775,1490 ; 4730,1449 4730,1525 ; 4740,1985 4740,2055
  lines w16: 446,2334 446,2427
  text "GND" at 970,3370 h72.83
  text "BUCK4" at 2950,3360.51 h72.83
  text "BUCK3" at 3674,3359 h72.83
  text "LDO1" at 1680,3296 h55 r270
  text "LDO2" at 1784.18,3296 h55 r270
  text "LDO3" at 1885.23,3296 h55 r270
  text "LDO4" at 1982.65,3296 h55 r270
  text "VINT" at 2183.66,3296 h55 r270
  text "GND_S" at 2282,3295.65 h55 r270
  text "VRTC" at 2086.24,3295 h55 r270
  text "VCCA" at 936,3176 h72.83
  text "GND" at 4394,3043 h72.83
  text "LDO OUTPUTS SENSE" at 1703.27,3040 h72.83
  text "C-Cell" at 4180,2927.88 h66
  text "VSYS" at 136.17,2923.84 h72.83
  text "GND" at 1836.7,2885 h72.83
  text "VBACKUP" at 3823.34,2688.78 h55 r270
  text "Load Module Connector" at 2740,2446 h77
  text "BMC047E3" at 1508.86,2409 h99
  text "VCCA" at 2210.62,2354.82 h66
  text "VIO_IN" at 3837.91,2350 h72.83
  text "VIO_IN Select" at 942,2315 h66
  text "EN_DRV" at 167.93,2245 h77
  text "FB_B4" at 2200,2230.23 h66
  text "1.8V" at 955,2229 h77
  text "3.3V" at 1157,2228 h77
  text "FB_B3" at 3844.27,2225.27 h66
  text "BUCK5" at 4824,2184 h72.83 r270
  text "nINT" at 167.93,2152 h77
  text "AMUXOUT" at 1998,2096 h72.83
  text "16x18 mm" at 3429,2078 h66
  text "Slave" at 1520,2069 h66
  text "Master" at 1699.64,2066 h66
  text "nRSTOUT" at 167.93,2052 h77
  text "SYNCCLKIN" at 3754,2022 h72.83
  text "M/S Select" at 1545.51,1995 h66
  text "nPWRON" at 167.93,1949 h77
  text "OVPGDRV" at 167.93,1841 h77
  text "J18" at 1358.82,1811 h50
  text "J19" at 1665.62,1809 h50
  text "VSYS_SENSE" at 168,1735 h77
  text "1" at 1210.76,1732 h55
  text "LDO4_IN_S" at 1256.76,1732 h55
  text "LDO4_OUT_S" at 1533.76,1732 h55
  text "V3V3" at 167.93,1646 h72.83
  text "GND_S" at 1303.76,1639 h55
  text "GND_S" at 1613.64,1639 h55
  text "2" at 1204.76,1638.31 h55
  text "LDO3_OUT_S" at 1533.35,1553 h55
  text "VSYS" at 168,1550 h77
  text "LDO3_IN_S" at 1255.76,1549 h55
  text "3" at 1204.76,1542 h55
  text "SCLK_SPMI" at 3949,1483 h50
  text "V5V0" at 168,1451 h77
  text "SDATA_SPMI" at 3944,1384.02 h50
  text "Input" at 2242,1371 h55
  text "Output" at 2377,1371.11 h55
  text "LDO #" at 1932,1366.11 h50
  text "VCCA" at 2082,1366.11 h50
  text "SCL2/CS" at 167.93,1352 h77
  text "VINT" at 1938,1309 h55
  text "N/A" at 2101,1309 h55
  text "J14-6" at 2392,1307 h55
  text "N/A" at 2248,1305 h55
  text "GND_S" at 4610,1290 h55
  text "nPWRON_S" at 3952,1288 h50
  text "BUCK OUTPUTS" at 4440,1265 h72.83 r270
  text "J14-5" at 2392,1252 h55
  text "GPIO1" at 167.93,1251 h77
  text "N/A" at 2101,1250 h55
  text "N/A" at 2249,1250 h55
  text "VRTC" at 1930,1249 h55
  text "GND" at 978,1217 h72.83
  text "J14-4" at 2392,1192 h55
  text "4" at 1975,1188 h55
  text "J20-1" at 2080,1187.13 h55
  text "J21-1" at 2234.89,1187.13 h55
  text "SDA1/SDI" at 3949,1184 h55
  text "VCCA_S" at 4580,1184 h55
  text "J14-3" at 2392,1132 h55
  text "3" at 1976,1128 h55
  text "J20-2" at 2081,1128 h55
  text "J21-2" at 2234,1128 h55
  text "SDA2/SDO" at 3948,1083 h55
  text "VOUT_B5" at 4554,1082 h55
  text "J14-2" at 2392,1072 h55
  text "2" at 1977,1068 h55
  text "J20-3" at 2082,1068 h55
  text "J21-3" at 2234,1068 h55
  text "Load Module Connector" at 2721,1016 h77
  text "J20-3" at 2081,1012 h55
  text "J21-3" at 2231,1007 h55
  text "J14-1" at 2392,1007 h55
  text "1" at 1977,1005 h55
  text "SCL1/SCK" at 3952,983 h55
  text "VOUT_B4" at 4554,982 h55
  text "SCL2/CS" at 3952,886 h55
  text "VOUT_B3" at 4554,880 h55
  text "SPI_EN" at 871,810 h72.83 r90
  text "VIO_IN" at 3953,786 h55
  text "VOUT_B2" at 4554,782 h55
  text "GPIO3" at 1421,752 h72.83 r90
  text "SDA2/SDO" at 1223,750 h72.83 r90
  text "nERR_SOC" at 1323,750 h72.83 r90
  text "nERR_MCU" at 1523,750 h72.83 r90
  text "GPIO7" at 1621,750 h72.83 r90
  text "GPIO2" at 1129,749 h72.83 r90
  text "TRIG_WDG" at 1724,749 h72.83 r90
  text "GPIO11" at 1823,747 h72.83 r90
  text "TRIG_WDG" at 1030,743 h72.83 r90
  text "PWR_BUT" at 200,690 h66 r270
  text "VOUT_B1" at 4554,685.61 h55
  text "Option" at 544,650 h77
  text "PU" at 628,473 h77
  text "GND" at 4638,441 h72.83
  text "GPIO" at 563,372 h72.83
  text "BUCK2" at 2965,360 h72.83
  text "BUCK1" at 3690,352 h72.83
  text "GND" at 347,314 h66
  text "PD" at 631,267 h77
  text "1" at 788,169 h72.83
  text "2" at 890,165 h72.83
  text "3" at 990,165 h72.83
  text "4" at 1085,165 h72.83
  text "5" at 1185,165 h72.83
  text "6" at 1285,165 h72.83
  text "7" at 1385,165 h72.83
  text "8" at 1485,165 h72.83
  text "9" at 1580,165 h72.83
  text "10" at 1665,165 h72.83
  text "11" at 1770,165 h72.83
  text "GPIO" at 553,60 h72.83
  text ".Layer_Name" at 573,-860 h60
Bottom Overlay:
  lines w5: 2645,711.5 3545,711 ; 2645,859.5 3544,859 ; 2645,907.5 3546,906 ; 2647,758.5 3546,758 ; 2647,811.5 3545,811 ; 2714,658.5 2714,962.5 ; 2791,658.5 2791,962.5 ; 2864,658.5 2864,963.5 ; 2975,660.5 2975,961.5 ; 3085,658.5 3085,962.5 ; 3198,659.26 3198,963.26 ; 3296,659 3296,963 ; 2645,658.5 2645,962.5 3546,963 3546,659 2645,658.5
  lines w6: 1135,1816 1135,1706.8 1164.2,1706.8 1186,1706.8 1186.6,1899.2
  text "S" at 2574,2549 h72.83
  text "M" at 2784.71,2549 h72.83
  text "M" at 3650,2549 h72.83
  text "S" at 3424,2547 h72.83
  text "S" at 2608.24,1176.49 h72.83
  text "M" at 2831.75,1172 h72.83
  text "J25" at 2705,921.5 h40
  text "J24" at 2780,921.5 h40
  text "J23" at 2853,921.5 h40
  text "R1" at 3268,921 h40
  text "Phase_Config" at 3525,921.5 h40
  text "R6/R7" at 2967,920.5 h40
  text "R4/R5" at 3077,920.5 h40
  text "R2/R3" at 3188,920.5 h40
  text "1 (4 Phases)" at 3517,871 h40
  text "-" at 2939,869.5 h44
  text "R1" at 3266,869 h40
  text "Y" at 2667,868.5 h44
  text "Y" at 2740,868.5 h44
  text "-" at 3053,868.5 h44
  text "Y" at 2813,867.5 h44
  text "R2" at 3162,867.5 h44
  text "N" at 2668,846.5 h44 r180
  text "2 (3 + 1)" at 3516,823 h40
  text "R1" at 3267,821 h40
  text "R2" at 3162,820.5 h44
  text "Y" at 2813,819.5 h44
  text "R7" at 2938,819.5 h44
  text "-" at 3053,819.5 h44
  text "Y" at 2738,818 h44
  text "N" at 2668,795.33 h44 r180
  text "N" at 2741,795.33 h44 r180
  text "3 (2 + 1 + 1)" at 3519,772 h40
  text "R1" at 3267,768.39 h40
  text "Y" at 2813,767.17 h44
  text "R7" at 2940,767.17 h44
  text "R5" at 3053,767.41 h44
  text "R2" at 3164,767.11 h44
  text "N" at 2666,746.83 h44 r180
  text "N" at 2737,746.83 h44 r180
  text "N" at 2816.62,746.83 h44 r180
  text "4 (1+1+1+1)" at 3520,723.5 h40
  text "R1" at 3267,719.89 h40
  text "R7" at 2938,718.67 h44
  text "R5" at 3054,718.91 h44
  text "R3" at 3163,718.85 h44
  text "N" at 2737,697.38 h44 r180
  text "5 (2 + 2)" at 3521,674.05 h40
  text "R1" at 3266,670.44 h40
  text "Y" at 2664,669.22 h44
  text "Y" at 2813,669.22 h44
  text "R6" at 2936,669.4 h44
  text "R5" at 3053,669.46 h44
  text "R2" at 3165,669.15 h44
  text "JTAG_CON" at 386,356 h66
  text ".Layer_Name" at 576,-859 h60
Top Paste:
  text ".Layer_Name" at 577,-858.49 h60
Bottom Paste:
  text ".Layer_Name" at 577,-858.49 h60
Top Solder:
  text ".Layer_Name" at 577,-858.49 h60
  text ".Layer_Name" at 577,-858.49 h60
Bottom Solder:
  rectangle: 3066,2143 3138,2269
  text ".Layer_Name" at 577,-858.49 h60
Drill Guide:
  text ".Layer_Name" at 577,-858.49 h60
M1 Board Outline:
  lines w7.87: 0,0 0,3448.82 4948.82,3448.82 4948.82,0 0,0
  text ".Layer_Name" at 577,-858.49 h60
M2 Board Dimensions:
  text ".Layer_Name" at 577,-858.49 h60
M3 3D STEP Top:
  text ".Layer_Name" at 577,-858.49 h60
M4 3D STEP Bottom:
  text ".Layer_Name" at 577,-858.49 h60
M5 Assembly Top:
  lines w7: 9870.89,-286.74 10995.89,-286.74 ; 9870.89,-164.24 10993.39,-164.24 ; 10185.89,-406.74 10185.89,-44.24 ; 10570.89,-406.74 9870.89,-406.74 ; 10570.89,-44.24 9870.89,-44.24 ; 9870.89,-406.74 10995.89,-406.74 10995.89,-44.24 9870.89,-44.24 ; 9870.89,-406.74 9870.89,-44.24
  lines w10: -292,-930.17 6308,-930.17 ; -292,-726.83 6310,-726.83 ; -292,-523.5 -292,-1133.5 3713,-1133.5 6310,-1133.5 6310,-523.5 -291.5,-523.5 -291.5,-1133.5 1284,-1133.5 ; 2173,-1133.5 2173,-523.5 ; 3440,-726.83 3440,-523.5 ; 4280,-726.83 4280,-523.5 ; 4902,-1140 4902,-937.17
  text "TABLE 1" at 10258.39,-9.24 h40
  text "Variant" at 9895.89,-119.24 h40
  text "Label text" at 10330.89,-119.24 h40
  text "001" at 9963.39,-239.24 h40
  text "TPS6594EVM" at 10240.89,-241.74 h40
  text "COMPONENTS MARKED 'DNP' SHOULD NOT BE POPULATED, AND MAY NOT BE IN BILL OF MATERIALS" at 1153.5,-318.5 h60
  text "ASSEMBLY VARIANT:" at 1153,-434 h60
  text ".VariantName" at 2189,-434 h60
  text "PCB VIEWED FROM TOP SIDE" at -228.5,-655.67 h60
  text "BOARD #:" at 2248,-655.67 h60
  text ".PRJ_Number" at 2793.5,-655.67 h60
  text "REV:" at 3638,-655.67 h60
  text ".PCB_Rev" at 3929.5,-655.67 h60
  text "SVN REV:" at 4476,-655.67 h60
  text ".VersionControl_RevNumber" at 4982,-655.67 h60
  text "IGNORE ->" at -228.5,-858.49 h60
  text "PLOT NAME =" at -228.5,-1064.34 h60
  text ".plot_File_Name" at 577,-1064.34 h60
  text "GENERATED    :" at 2250,-1064.34 h60
  text ".Print_Date" at 3119.5,-1064.34 h60
  text ".Print_Time" at 3848.5,-1064.34 h60
  text "TEXAS INSTRUMENTS" at 5113,-1064.34 h60
M6 Assembly Bottom:
  lines w10: -292.5,-727.33 6309.5,-727.33 ; -290.5,-930.67 6309.5,-930.67 ; 1115.5,-1140.5 1115.5,-937.67 ; 1737.5,-727.33 1737.5,-524 ; 2577.5,-727.33 2577.5,-524 ; 3844.5,-1134 3844.5,-524 ; 4733.5,-1134 6309,-1134 6309,-524 -292.5,-524 -292.5,-1134 2304.5,-1134 6309.5,-1134 6309.5,-524
  text "COMPONENTS MARKED 'DNP' SHOULD NOT BE POPULATED, AND MAY NOT BE IN BILL OF MATERIALS" at 6102,-318 h60
  text ".VariantName" at 5058,-434 h60
  text "ASSEMBLY VARIANT:" at 6097,-434 h60
  text ".VersionControl_RevNumber" at 1035.5,-656.17 h60
  text "SVN REV:" at 1541.5,-656.17 h60
  text ".PCB_Rev" at 2088,-656.17 h60
  text "REV:" at 2379.5,-656.17 h60
  text ".PRJ_Number" at 3224,-656.17 h60
  text "BOARD #:" at 3769.5,-656.17 h60
  text "PCB VIEWED FROM BOTTOM SIDE" at 6246,-656.17 h60
  text "IGNORE ->" at 2547.85,-858.49 h60
  text "TEXAS INSTRUMENTS" at 904.5,-1064.84 h60
  text ".Print_Time" at 2169,-1064.84 h60
  text ".Print_Date" at 2898,-1064.84 h60
  text "GENERATED    :" at 3767.5,-1064.84 h60
  text ".plot_File_Name" at 5440.5,-1064.84 h60
  text "PLOT NAME =" at 6246,-1064.84 h60
M9 Title Sheet:
  drawing of 57 lines, arcs and shapes, not listed
  text "1" at 739.84,8036.5 h70
  text "2" at 3235.5,8036.5 h70
  text "3" at 5724.84,8036.5 h70
  text "4" at 8231.51,8036.5 h70
  text "5" at 10730.5,8036.5 h70
  text "6" at 13235.5,8036.5 h70
  text "A" at -416.5,6893.5 h70
  text "A" at 14383.5,6893.5 h70
  text "B" at -416.5,4513.5 h70
  text "B" at 14383.5,4513.5 h70
  text "C" at -416.5,2138.5 h70
  text "C" at 14383.5,2138.5 h70
  text "PROJECT TITLE:" at 11343.5,277.5 h45
  text ".PRJ_Title" at 11357,132 h70
  text "DESIGNED FOR:" at 11343.5,-23.5 h45
  text ".PRJ_Customer" at 11393.5,-163.5 h70
  text "D" at -416.5,-231.5 h70
  text "D" at 14383.5,-231.5 h70
  text "FILE NAME:" at 11343.5,-323.5 h45
  text ".PCB_File_Name_No_Path" at 11393.5,-443.5 h70
  text "Texas Instruments (TI) and/or its licensors do not warrant the accuracy or completeness of this specification" at 6374,-605.34 h45
  text "ENGINEER:" at 11343.5,-613.5 h45
  text "LAYOUT BY:" at 12848.5,-613.5 h45
  text "or any information contained therein. TI and/or its licensors do not warrant that this design will meet" at 6329.01,-718 h45
  text ".PRJ_Engineer" at 11393.5,-768.49 h70
  text ".PCB_Layout" at 12899,-768.49 h70
  text "the specifications, will be suitable for your application or fit for any particular purpose, or will operate in" at 6329.01,-830.67 h45
  text ".Layer_Name" at 577,-858.49 h60
  text "ALTIUM DESIGNER VERSION:" at 12848.5,-923.5 h45
  text "an implementation. TI and/or its licensors do not warrant that the design is production worthy. You should" at 6329.01,-943.33 h45
  text "completely validate and test your design implementation to confirm the system functionality for your application." at 6374,-1056 h45
  text ".print_Scale" at 11393.5,-1056.83 h70
  text ".Application_BuildNumber" at 12899,-1056.83 h70
  text "1" at 739.84,-1263.5 h70
  text "2" at 3235.5,-1263.5 h70
  text "3" at 5724.84,-1263.5 h70
  text "4" at 8231.51,-1263.5 h70
  text "5" at 10730.5,-1263.5 h70
  text "6" at 13235.5,-1263.5 h70
M10 Fab Notes:
  drawing of 212 lines, arcs and shapes, not listed
  text "DESIGN INFORMATION" at 12381.02,6810 h60
  text "(REFER ALSO ARRAY/PANEL PROFILING INFORMATION)" at 12019.46,6648.29 h60
  text "BOARD SIZE" at 11333.46,6644 h60
  text "125.7mm" at 11795.78,6516.18 h60
  text "X" at 12301.46,6516.18 h60
  text "87.6mm" at 12532.78,6516.18 h60
  text "Number of Layers :" at 11736.46,6319 h60
  text "6" at 12831.27,6309 h60
  text "MIN. TRACK WIDTH:" at 11736.46,6180 h60
  text "MIL" at 12987.46,6180 h60
  text "4.9" at 12772.64,6179.13 h60
  text "MIN. CLEARANCE:" at 11736.46,6048 h60
  text "4" at 12832.7,6048 h60
  text "MIL" at 12987.46,6048 h60
  text "MIN. VIA PAD SIZE:" at 11736.46,5916 h60
  text "7.8" at 12802.71,5916 h60
  text "MIL" at 12987.46,5916 h60
  text "0.1mm (4MIL)" at 12431.46,5774.29 h60
  text "MINIMUM ANNULAR RING" at 11407.23,5770 h60
  text "EXTERNAL" at 13139.46,5770 h60
  text "PER" at 11607.23,5652 h60
  text "IPC-D-275 CLASS 2 LEVEL C" at 11827.23,5652 h60
  text "MIL, HOLES" at 13315.46,5539.71 h60
  text "+/-" at 12923,5539 h60
  text "+/-" at 13777,5539 h60
  text "REGISTRATION TOLERANCES:" at 11407.23,5534 h60
  text "METAL" at 12607,5534 h60
  text "5" at 13183.2,5534 h60
  text "3" at 14016.2,5534 h60
  text "MIL" at 14132.46,5534 h60
  text "MATERIAL:" at 11332.46,5324.54 h60
  text "FR-4 High Tg" at 12318.9,5184.21 h60
  text "FR-408" at 11753.46,5175.64 h60
  text "X" at 12165.46,5175.64 h60
  text "OTHER" at 13241.46,5175.64 h60
  text "62 MIL (1.6mm) +/-10%" at 12073.56,5012.92 h60
  text "THICKNESS:" at 11407.23,5008.64 h60
  text "OTHER" at 13358.46,5008.64 h60
  text "X" at 11947.46,5004.64 h60
  text "TOLERANCE:" at 11407.23,4850.64 h60
  text "X" at 12246.53,4850.64 h60
  text "ANSI IPC-6012 TYPE 3 CLASS 2" at 12433.48,4850.64 h60
  text "OTHER +/-" at 12433.46,4694.64 h60
  text "BOW & TWIST:" at 11407.23,4537.64 h60
  text "X" at 12246.53,4537.64 h60
  text "ANSI IPC-6012 TYPE 3 CLASS 2" at 12433.48,4537.64 h60
  text "OTHER +/-" at 12433.46,4379.13 h60
  text "COPPER THICKNESS (FINISHED):" at 11332.46,4243.64 h60
  text "1.4MIL (1oz)" at 12212.46,4090.92 h60
  text "2MIL (1.4oz)" at 12979.46,4090.92 h60
  text "2.8MIL (2oz)" at 13706.46,4090.92 h60
  text "OUTER:" at 11689.46,4086.64 h60
  text "X" at 13579,4082 h60
  text "1.4MIL (1oz)" at 12212.46,3933.92 h60
  text "2.8MIL (2oz)" at 12979.46,3933.92 h60
  text "N/A" at 13706,3934.29 h60
  text "INNER SIGNAL:" at 11400.38,3929.64 h60
  text "X" at 12085.42,3929.64 h60
  text "DRILLING:" at 11332.46,3790.64 h60
  text "REFERENCE:" at 11407.23,3673.64 h60
  text "X" at 12055.46,3673.64 h60
  text "AS SHOWN" at 12242.46,3673.64 h60
  text "X" at 12956.46,3673.64 h60
  text "NC_DRILL FILES" at 13093.46,3673.64 h60
  text "PTH MIN COPPER THICKNESS:" at 11407.23,3515.64 h60
  text "X" at 12757.46,3515.64 h60
  text "1MIL" at 12894.46,3515.64 h60
  text "OTHER" at 13391.46,3515.64 h60
  text "BOARD FINISH:" at 11332.46,3356.64 h60
  text "SILKSCREEN:" at 11487.68,3238.64 h60
  text "X" at 12436.46,3238.64 h60
  text "TOP" at 12562.46,3238.64 h60
  text "X" at 12946.46,3238.64 h60
  text "BOTTOM" at 13073.46,3238.64 h60
  text "SILKSCREEN COLOR:" at 11487.68,3071.64 h60
  text "X" at 12435.42,3071.64 h60
  text "WHITE" at 12562.46,3071.64 h60
  text "OTHER" at 13073.46,3071.64 h60
  text "SOLDER RESIST COLOR:" at 11487.68,2901.64 h60
  text "GREEN" at 12182.46,2742.44 h60
  text "X" at 12640,2742.44 h60
  text "BLUE" at 12773.46,2742.44 h60
  text "OTHER" at 13311.46,2742.44 h60
  text "IMMERSION GOLD (ENIG)" at 12393.46,2553.92 h60
  text "ENEPIG" at 13731,2550.64 h60
  text "SURFACE FINISH:" at 11332.46,2549.64 h60
  text "X" at 12206.51,2549.64 h60
  text "IMM. TIN/SILVER OR EQUIV" at 11662,2392.64 h60
  text "OTHER" at 13093.46,2392.64 h60
  text "ARRAY/PANEL:" at 11332.46,2213.64 h60
  text "CUT AND TRIM PER MECH LAYER 1" at 12393.46,2209.35 h60
  text "N.C. ROUTE" at 12393.46,2057.64 h60
  text "V. SCORE" at 13259.46,2057.64 h60
  text "X" at 13070,2048.44 h60
  text "CERTIFICATION:" at 11332.46,1920.64 h60
  text "MATERIALS AND WORKMANSHIP FOR ALL PCBS" at 12057.46,1920.64 h60
  text "TO MEET OR EXCEED THE REQUIREMENTS OF:" at 12057.46,1822.64 h60
  text "X" at 11683.96,1686.13 h60
  text "ANSI IPC-A-600F CLASS ->" at 11822.96,1686.13 h60
  text "X" at 13462.02,1686.13 h60
  text "2" at 13580.96,1686.14 h60
  text "1" at 13265.96,1684.64 h60
  text "3" at 13934.96,1684.64 h60
  text "OTHER" at 13298.3,1534.51 h60
  text "PER ORDER" at 13695.36,1534.51 h60
  text "X" at 11686.02,1526.64 h60
  text "UL 94V-0" at 11822.96,1526.64 h60
  text "X" at 12498.02,1526.64 h60
  text "RoHS" at 12634.96,1526.64 h60
  text "ADDITIONAL REQUIREMENTS:" at 11332.46,1385.64 h60
  text "MICROSECTION:" at 11407.23,1270.64 h60
  text "YES" at 12312.96,1270.64 h60
  text "REQUIRED" at 13193.4,1122.37 h60
  text "PER ORDER" at 13785.4,1119.51 h60
  text "BARE BOARD ELEC. TEST:" at 11407.23,1111.64 h60
  text "NONE" at 12712.96,1111.64 h60
  text "X" at 13047.46,1111.64 h60
  text "METAL" at 13083.71,958.23 h60
  text "X" at 13458.94,957.87 h60
  text "SILK" at 13595.4,958.23 h60
  text "MANUFACTURER'S UL:" at 11407.23,954.64 h60
  text "RAIL" at 12572.96,950.35 h60
  text ".Layer_Name" at 577,-858.49 h60
  text ".Layer_Name" at 577,-858.49 h60
M11 Gerber Information:
  lines w10: -292,-930.17 6308,-930.17 ; -292,-726.83 6310,-726.83 ; -292,-523.5 -292,-1133.5 3713,-1133.5 6310,-1133.5 6310,-523.5 -291.5,-523.5 -291.5,-1133.5 1284,-1133.5 ; 2173,-1133.5 2173,-523.5 ; 3440,-726.83 3440,-523.5 ; 4280,-726.83 4280,-523.5 ; 4902,-1140 4902,-937.17
  text "ALL ARTWORK VIEWED FROM TOP SIDE" at -228.5,-655.67 h60
  text "BOARD #:" at 2248,-655.67 h60
  text ".PRJ_Number" at 2793.5,-655.67 h60
  text "REV:" at 3638,-655.67 h60
  text ".PCB_Rev" at 3929.5,-655.67 h60
  text "SVN REV:" at 4476,-655.67 h60
  text ".VersionControl_RevNumber" at 4982,-655.67 h60
  text "LAYER NAME =" at -228.5,-858.49 h60
  text "PLOT NAME =" at -228.5,-1064.34 h60
  text ".plot_File_Name" at 577,-1064.34 h60
  text "GENERATED    :" at 2250,-1064.34 h60
  text ".Print_Date" at 3119.5,-1064.34 h60
  text ".Print_Time" at 3848.5,-1064.34 h60
  text "TEXAS INSTRUMENTS" at 5113,-1064.34 h60
M12 Stackup:
  drawing of 399 lines, arcs and shapes, not listed
  text "Layer" at 6654.58,6814 h60
  text "Name" at 7064.49,6814 h60
  text "Material" at 8004.23,6814 h60
  text "Thickness" at 8864,6814 h60
  text "Constant" at 9513.84,6814 h60
  text "Board Layer Stack" at 10083.7,6814 h60
  text "1" at 6654.58,6694 h60
  text "Top Overlay" at 7064.49,6694 h60
  text "2" at 6654.58,6574 h60
  text "Top Solder" at 7064.49,6574 h60
  text "Solder Resist" at 8004.23,6574 h60
  text "0.65mil" at 8864,6574 h60
  text "3.5" at 9513.84,6574 h60
  text "3" at 6654.58,6454 h60
  text "Top Layer" at 7064.49,6454 h60
  text "Copper" at 8004.23,6454 h60
  text "2.80mil" at 8864,6454 h60
  text "4" at 6654.58,6334 h60
  text "Dielectric1" at 7064.49,6334 h60
  text "FR-4" at 8004.23,6334 h60
  text "5.00mil" at 8864,6334 h60
  text "4.2" at 9513.84,6334 h60
  text "5" at 6654.58,6214 h60
  text "GND Layer 1" at 7064.49,6214 h60
  text "Copper" at 8004.23,6214 h60
  text "1.40mil" at 8864,6214 h60
  text "6" at 6654.58,6094 h60
  text "Dielectric 2" at 7064.49,6094 h60
  text "FR-4" at 8004.23,6094 h60
  text "5.00mil" at 8864,6094 h60
  text "4.2" at 9513.84,6094 h60
  text "7" at 6654.58,5974 h60
  text "Signal Layer 1" at 7064.49,5974 h60
  text "Copper" at 8004.23,5974 h60
  text "1.40mil" at 8864,5974 h60
  text "8" at 6654.58,5854 h60
  text "Dielectric 3" at 7064.49,5854 h60
  text "FR-4" at 8004.23,5854 h60
  text "29.50mil" at 8864,5854 h60
  text "4.2" at 9513.84,5854 h60
  text "9" at 6654.58,5734 h60
  text "Signal Layer 2" at 7064.49,5734 h60
  text "Copper" at 8004.23,5734 h60
  text "1.40mil" at 8864,5734 h60
  text "10" at 6654.58,5614 h60
  text "Dielectric 4" at 7064.49,5614 h60
  text "FR-4" at 8004.23,5614 h60
  text "5.00mil" at 8864,5614 h60
  text "4.2" at 9513.84,5614 h60
  text "11" at 6654.58,5494 h60
  text "GND Layer 2" at 7064.49,5494 h60
  text "Copper" at 8004.23,5494 h60
  text "1.40mil" at 8864,5494 h60
  text "12" at 6654.58,5374 h60
  text "Dielectric 5" at 7064.49,5374 h60
  text "FR-4" at 8004.23,5374 h60
  text "5.00mil" at 8864,5374 h60
  text "4.2" at 9513.84,5374 h60
  text "13" at 6654.58,5254 h60
  text "Bottom Layer" at 7064.49,5254 h60
  text "Copper" at 8004.23,5254 h60
  text "2.80mil" at 8864,5254 h60
  text "14" at 6654.58,5134 h60
  text "Bottom Solder" at 7064.49,5134 h60
  text "Solder Resist" at 8004.23,5134 h60
  text "0.65mil" at 8864,5134 h60
  text "3.5" at 9513.84,5134 h60
  text "15" at 6654.58,5014 h60
  text "Bottom Overlay" at 7064.49,5014 h60
  text ".Layer_Name" at 577,-858.49 h60
M13 Component Bodies Top:
  text ".Layer_Name" at 577,-858.49 h60
M14 Component Bodies Bottom:
  text ".Layer_Name" at 577,-858.49 h60
M15 Courtyards Top:
  text ".Layer_Name" at 577,-858.49 h60
M16 Courtyards Bottom:
  text ".Layer_Name" at 577,-858.49 h60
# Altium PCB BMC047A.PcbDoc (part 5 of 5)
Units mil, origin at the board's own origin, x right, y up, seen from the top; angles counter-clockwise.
Board outline 4950 x 3450 mil, 6 copper layers (Top Layer, GND Layer 1, Signal Layer 1, Signal Layer 2, GND Layer 2, Bottom Layer), stack 60.7 mil thick; 322 components, 160 nets, 1128 pads, 816 vias.

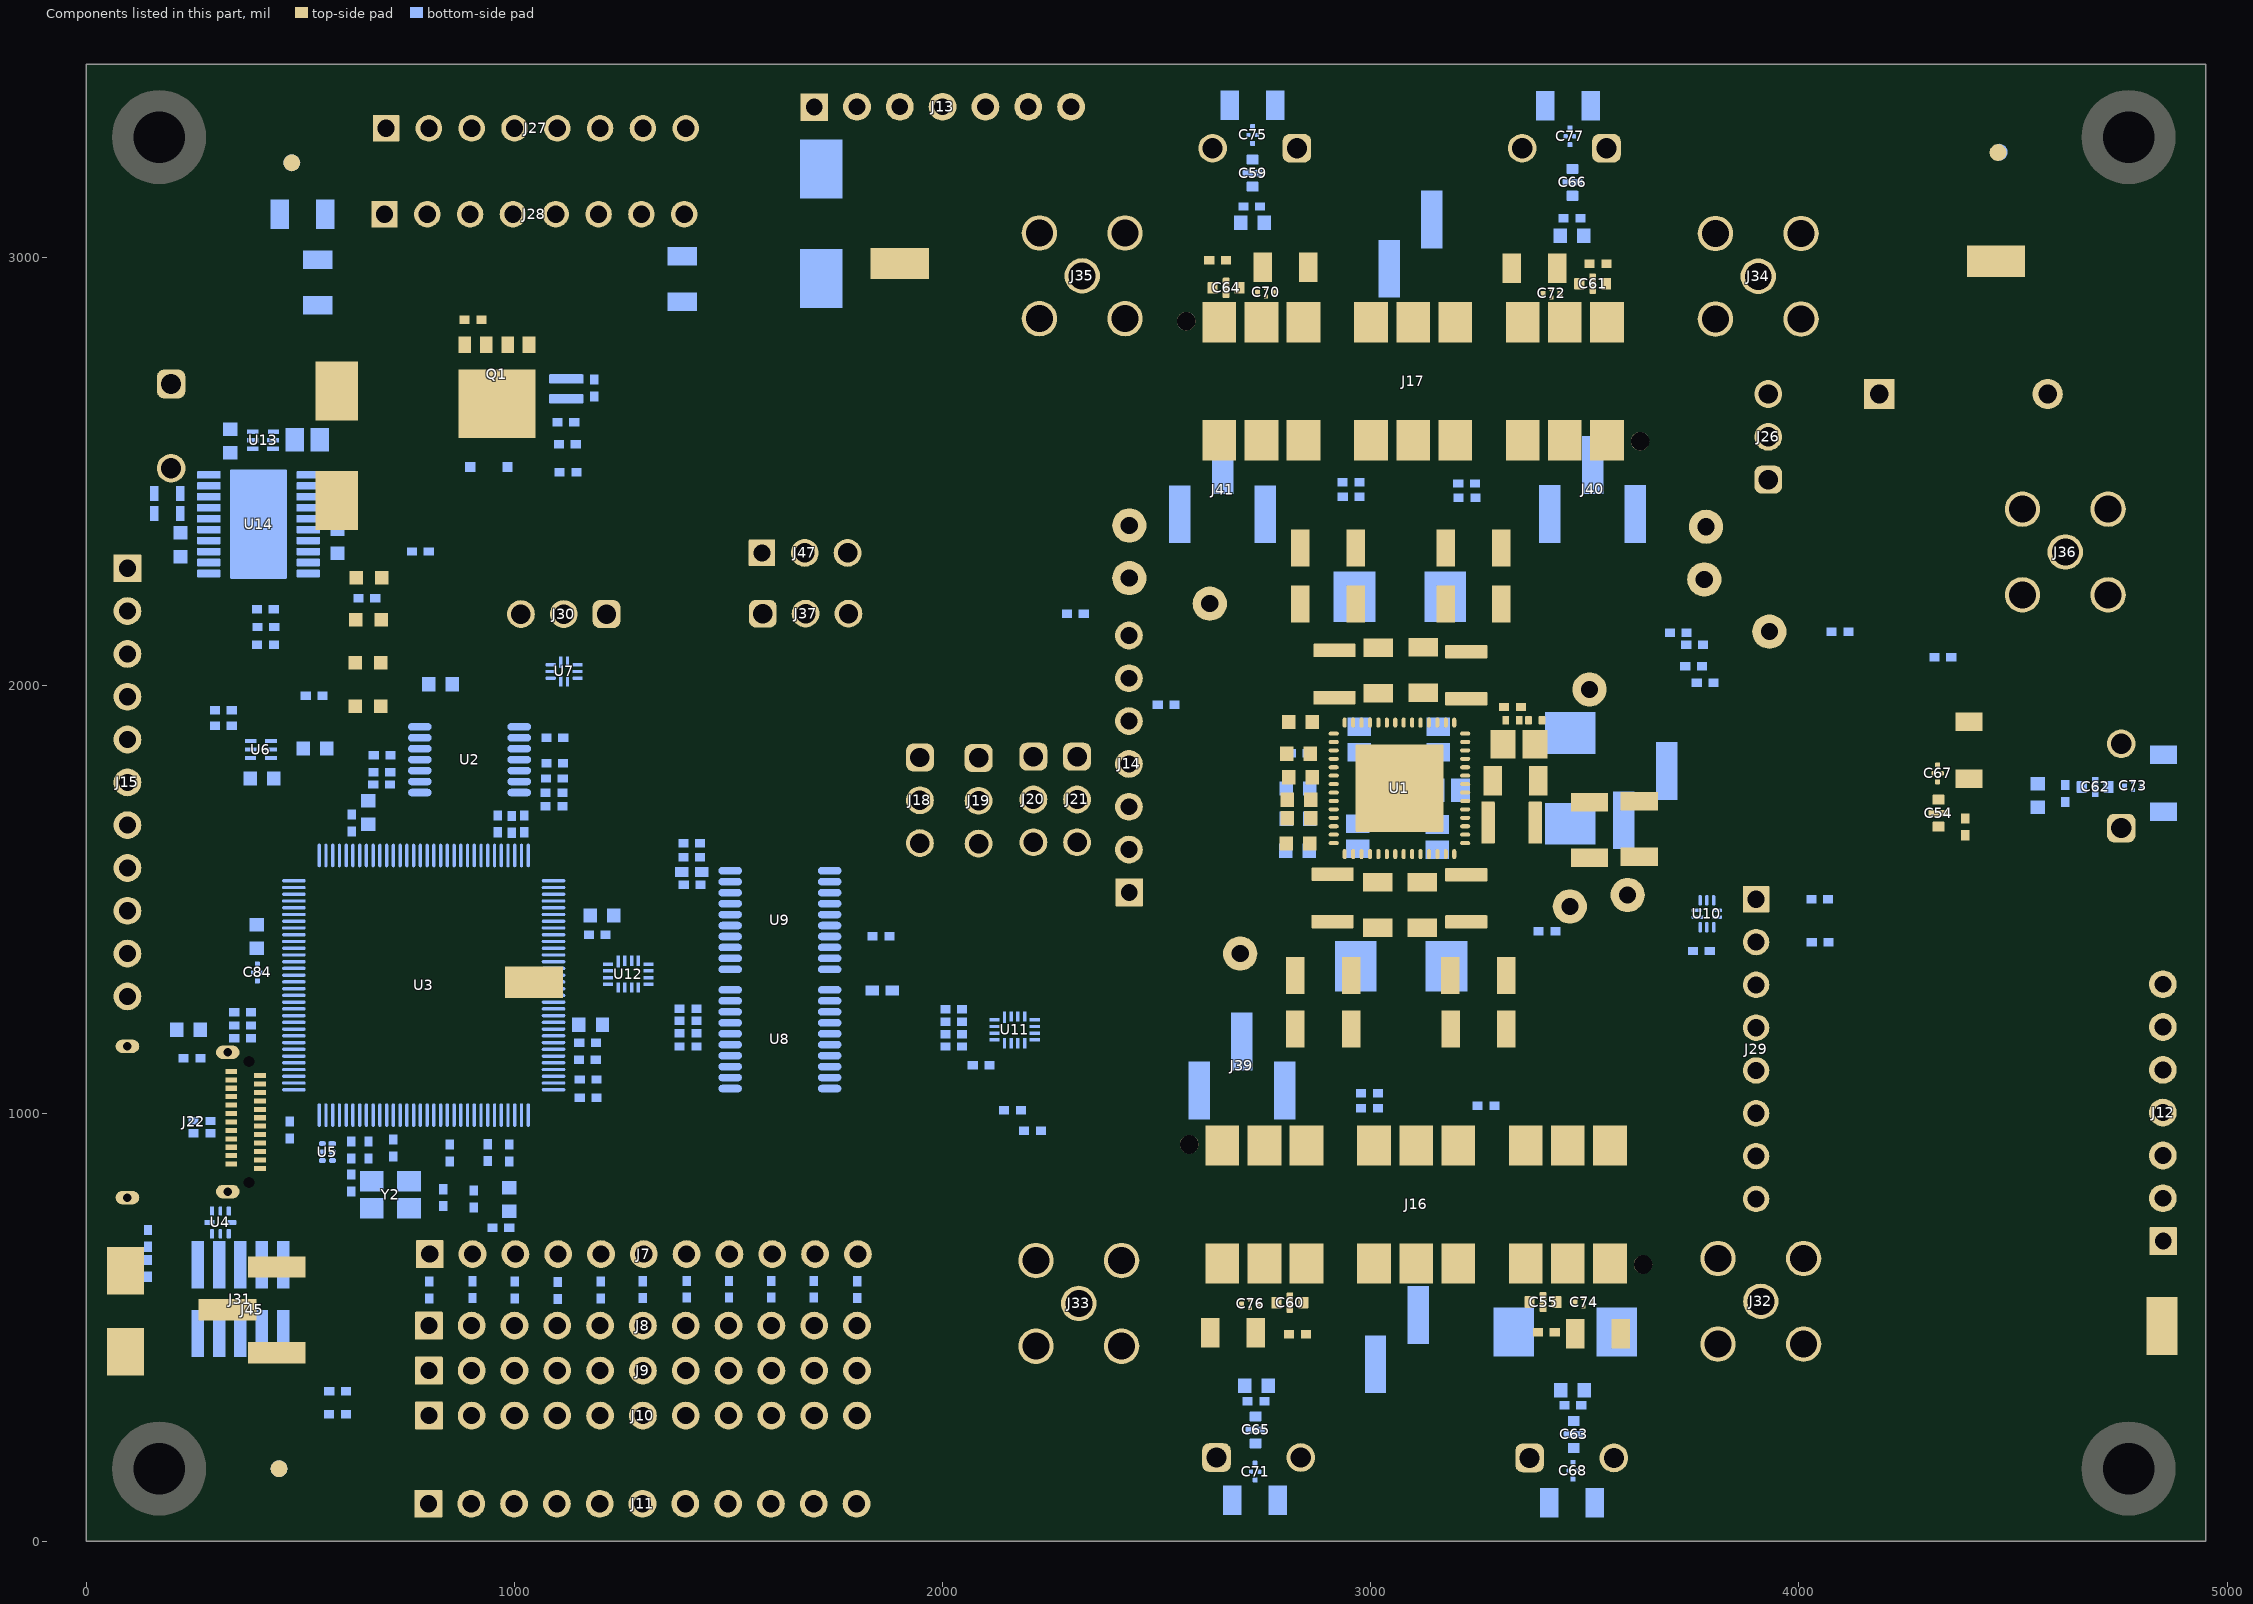
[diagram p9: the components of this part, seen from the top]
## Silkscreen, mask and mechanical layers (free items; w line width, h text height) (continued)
Drill Drawing:
  drawing of 184 lines, arcs and shapes, not listed
  text "Symbol" at 6663.21,4712.51 h72
  text "Quantity" at 6963.37,4712.51 h72
  text "Finished Hole Size" at 7295.06,4712.51 h72
  text "Plated" at 7930.91,4712.51 h72
  text "Hole Type" at 8189.71,4712.51 h72
  text "Drill Layer Pair" at 8564.46,4712.51 h72
  text "Hole Tolerance" at 9287,4712.51 h72
  text "1" at 6963.37,4588.49 h60
  text "25.59mil (0.650mm)" at 7295.06,4588.49 h60
  text "NPTH" at 7930.91,4588.49 h60
  text "Round" at 8189.71,4588.49 h60
  text "Top Layer - Bottom Layer" at 8564.46,4588.49 h60
  text "4" at 6963.37,4464.46 h60
  text "43.31mil (1.100mm)" at 7295.06,4464.46 h60
  text "NPTH" at 7930.91,4464.46 h60
  text "Round" at 8189.71,4464.46 h60
  text "Top Layer - Bottom Layer" at 8564.46,4464.46 h60
  text "15" at 6963.37,4340.43 h60
  text "7.87mil (0.200mm)" at 7295.06,4340.43 h60
  text "PTH" at 7930.91,4340.43 h60
  text "Round" at 8189.71,4340.43 h60
  text "Top Layer - Bottom Layer" at 8564.46,4340.43 h60
  text "499" at 6963.37,4216.41 h60
  text "8.00mil (0.203mm)" at 7295.06,4216.41 h60
  text "PTH" at 7930.91,4216.41 h60
  text "Round" at 8189.71,4216.41 h60
  text "Top Layer - Bottom Layer" at 8564.46,4216.41 h60
  text "40" at 6963.37,4092.38 h60
  text "10.00mil (0.254mm)" at 7295.06,4092.38 h60
  text "PTH" at 7930.91,4092.38 h60
  text "Round" at 8189.71,4092.38 h60
  text "Top Layer - Bottom Layer" at 8564.46,4092.38 h60
  text "261" at 6963.37,3968.35 h60
  text "11.00mil (0.279mm)" at 7295.06,3968.35 h60
  text "PTH" at 7930.91,3968.35 h60
  text "Round" at 8189.71,3968.35 h60
  text "Top Layer - Bottom Layer" at 8564.46,3968.35 h60
  text "B" at 6637.97,3958.36 h55.12
  text "21" at 6963.37,3844.33 h60
  text "39.37mil (1.000mm)" at 7295.06,3844.33 h60
  text "PTH" at 7930.91,3844.33 h60
  text "Round" at 8189.71,3844.33 h60
  text "Top Layer - Bottom Layer" at 8564.46,3844.33 h60
  text "77" at 6963.37,3720.3 h60
  text "40.00mil (1.016mm)" at 7295.06,3720.3 h60
  text "PTH" at 7930.91,3720.3 h60
  text "Round" at 8189.71,3720.3 h60
  text "Top Layer - Bottom Layer" at 8564.46,3720.3 h60
  text "25" at 6963.37,3596.27 h60
  text "40.16mil (1.020mm)" at 7295.06,3596.27 h60
  text "PTH" at 7930.91,3596.27 h60
  text "Round" at 8189.71,3596.27 h60
  text "Top Layer - Bottom Layer" at 8564.46,3596.27 h60
  text "2" at 6963.37,3472.25 h60
  text "43.31mil (1.100mm)" at 7295.06,3472.25 h60
  text "PTH" at 7930.91,3472.25 h60
  text "Round" at 8189.71,3472.25 h60
  text "Top Layer - Bottom Layer" at 8564.46,3472.25 h60
  text "23" at 6963.37,3348.22 h60
  text "45.28mil (1.150mm)" at 7295.06,3348.22 h60
  text "PTH" at 7930.91,3348.22 h60
  text "Round" at 8189.71,3348.22 h60
  text "Top Layer - Bottom Layer" at 8564.46,3348.22 h60
  text "12" at 6963.37,3224.19 h60
  text "47.24mil (1.200mm)" at 7295.06,3224.19 h60
  text "PTH" at 7930.91,3224.19 h60
  text "Round" at 8189.71,3224.19 h60
  text "Top Layer - Bottom Layer" at 8564.46,3224.19 h60
  text "25" at 6963.37,3100.17 h60
  text "62.99mil (1.600mm)" at 7295.06,3100.17 h60
  text "PTH" at 7930.91,3100.17 h60
  text "Round" at 8189.71,3100.17 h60
  text "Top Layer - Bottom Layer" at 8564.46,3100.17 h60
  text "4" at 6963.37,2976.14 h60
  text "120.00mil (3.048mm)" at 7295.06,2976.14 h60
  text "PTH" at 7930.91,2976.14 h60
  text "Round" at 8189.71,2976.14 h60
  text "Top Layer - Bottom Layer" at 8564.46,2976.14 h60
  text "1" at 6963.37,2852.11 h60
  text "25.59mil (0.650mm)" at 7295.06,2852.11 h60
  text "NPTH" at 7930.91,2852.11 h60
  text "Slot" at 8189.71,2852.11 h60
  text "Top Layer - Bottom Layer" at 8564.46,2852.11 h60
  text "4" at 6963.37,2728.09 h60
  text "19.69mil (0.500mm)" at 7295.06,2728.09 h60
  text "PTH" at 7930.91,2728.09 h60
  text "Slot" at 8189.71,2728.09 h60
  text "Top Layer - Bottom Layer" at 8564.46,2728.09 h60
  text "1014 Total" at 6963.37,2604.06 h60
  text "Slot definitions :" at 6663.21,2517.24 h60
  text "Routed Path Length" at 7112.65,2517.24 h60
  text "= Calculated from tool start centre position to tool end centre position." at 7651.01,2517.24 h60
  text "Hole Length" at 7112.65,2467.63 h60
  text "= Routed Path Length + Tool Size = Slot length as defined in the PCB layout" at 7451.7,2467.63 h60
  text ".Layer_Name" at 577,-858.49 h60
M20 Hard Gold Plating:
  text ".Layer_Name" at 577,-858.49 h60

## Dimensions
0,0 to 0,3450 on M2 Board Dimensions
0,0 to 4950,0 on M2 Board Dimensions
